VERSION 5.8 ;
BUSBITCHARS "[]" ;
DIVIDERCHAR "/" ;
UNITS
    DATABASE MICRONS 1000 ;
END UNITS

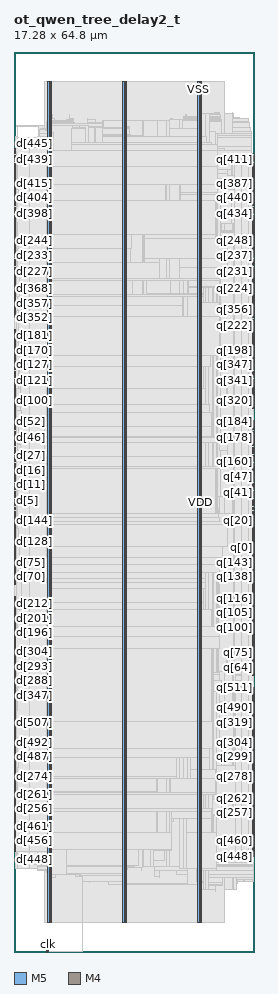
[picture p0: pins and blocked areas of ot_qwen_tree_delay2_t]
MACRO ot_qwen_tree_delay2_t
  FOREIGN ot_qwen_tree_delay2_t 0 0 ;
  CLASS BLOCK ;
  SIZE 17.28 BY 64.8 ;
  PIN clk
    DIRECTION INPUT ;
    USE SIGNAL ;
    PORT
      LAYER M5 ;
        RECT  2.352 0 2.376 0.084 ;
    END
    PORT
      LAYER M5 ;
        RECT  2.352 0.016 2.376 0.037 ;
    END
    PORT
      LAYER M5 ;
        RECT  2.352 0.037 2.472 0.179 ;
    END
  END clk
  PIN d[0]
    DIRECTION INPUT ;
    USE SIGNAL ;
    PORT
      LAYER M4 ;
        RECT  0 32.592 0.084 32.616 ;
    END
  END d[0]
  PIN d[100]
    DIRECTION INPUT ;
    USE SIGNAL ;
    PORT
      LAYER M4 ;
        RECT  0 39.12 0.084 39.144 ;
    END
  END d[100]
  PIN d[101]
    DIRECTION INPUT ;
    USE SIGNAL ;
    PORT
      LAYER M4 ;
        RECT  0 39.216 0.084 39.24 ;
    END
  END d[101]
  PIN d[102]
    DIRECTION INPUT ;
    USE SIGNAL ;
    PORT
      LAYER M4 ;
        RECT  0 39.312 0.084 39.336 ;
    END
  END d[102]
  PIN d[103]
    DIRECTION INPUT ;
    USE SIGNAL ;
    PORT
      LAYER M4 ;
        RECT  0 39.408 0.084 39.432 ;
    END
  END d[103]
  PIN d[104]
    DIRECTION INPUT ;
    USE SIGNAL ;
    PORT
      LAYER M4 ;
        RECT  0 39.504 0.084 39.528 ;
    END
  END d[104]
  PIN d[105]
    DIRECTION INPUT ;
    USE SIGNAL ;
    PORT
      LAYER M4 ;
        RECT  0 39.6 0.084 39.624 ;
    END
  END d[105]
  PIN d[106]
    DIRECTION INPUT ;
    USE SIGNAL ;
    PORT
      LAYER M4 ;
        RECT  0 39.696 0.084 39.72 ;
    END
  END d[106]
  PIN d[107]
    DIRECTION INPUT ;
    USE SIGNAL ;
    PORT
      LAYER M4 ;
        RECT  0 39.792 0.084 39.816 ;
    END
  END d[107]
  PIN d[108]
    DIRECTION INPUT ;
    USE SIGNAL ;
    PORT
      LAYER M4 ;
        RECT  0 39.888 0.084 39.912 ;
    END
  END d[108]
  PIN d[109]
    DIRECTION INPUT ;
    USE SIGNAL ;
    PORT
      LAYER M4 ;
        RECT  0 39.984 0.084 40.008 ;
    END
  END d[109]
  PIN d[10]
    DIRECTION INPUT ;
    USE SIGNAL ;
    PORT
      LAYER M4 ;
        RECT  0 33.552 0.084 33.576 ;
    END
  END d[10]
  PIN d[110]
    DIRECTION INPUT ;
    USE SIGNAL ;
    PORT
      LAYER M4 ;
        RECT  0 40.08 0.084 40.104 ;
    END
  END d[110]
  PIN d[111]
    DIRECTION INPUT ;
    USE SIGNAL ;
    PORT
      LAYER M4 ;
        RECT  0 40.176 0.084 40.2 ;
    END
  END d[111]
  PIN d[112]
    DIRECTION INPUT ;
    USE SIGNAL ;
    PORT
      LAYER M4 ;
        RECT  0 40.272 0.084 40.296 ;
    END
  END d[112]
  PIN d[113]
    DIRECTION INPUT ;
    USE SIGNAL ;
    PORT
      LAYER M4 ;
        RECT  0 40.368 0.084 40.392 ;
    END
  END d[113]
  PIN d[114]
    DIRECTION INPUT ;
    USE SIGNAL ;
    PORT
      LAYER M4 ;
        RECT  0 40.464 0.084 40.488 ;
    END
  END d[114]
  PIN d[115]
    DIRECTION INPUT ;
    USE SIGNAL ;
    PORT
      LAYER M4 ;
        RECT  0 40.56 0.084 40.584 ;
    END
  END d[115]
  PIN d[116]
    DIRECTION INPUT ;
    USE SIGNAL ;
    PORT
      LAYER M4 ;
        RECT  0 40.656 0.084 40.68 ;
    END
  END d[116]
  PIN d[117]
    DIRECTION INPUT ;
    USE SIGNAL ;
    PORT
      LAYER M4 ;
        RECT  0 40.752 0.084 40.776 ;
    END
  END d[117]
  PIN d[118]
    DIRECTION INPUT ;
    USE SIGNAL ;
    PORT
      LAYER M4 ;
        RECT  0 40.848 0.084 40.872 ;
    END
  END d[118]
  PIN d[119]
    DIRECTION INPUT ;
    USE SIGNAL ;
    PORT
      LAYER M4 ;
        RECT  0 40.944 0.084 40.968 ;
    END
  END d[119]
  PIN d[11]
    DIRECTION INPUT ;
    USE SIGNAL ;
    PORT
      LAYER M4 ;
        RECT  0 33.648 0.084 33.672 ;
    END
  END d[11]
  PIN d[120]
    DIRECTION INPUT ;
    USE SIGNAL ;
    PORT
      LAYER M4 ;
        RECT  0 41.04 0.084 41.064 ;
    END
  END d[120]
  PIN d[121]
    DIRECTION INPUT ;
    USE SIGNAL ;
    PORT
      LAYER M4 ;
        RECT  0 41.136 0.084 41.16 ;
    END
  END d[121]
  PIN d[122]
    DIRECTION INPUT ;
    USE SIGNAL ;
    PORT
      LAYER M4 ;
        RECT  0 41.232 0.084 41.256 ;
    END
  END d[122]
  PIN d[123]
    DIRECTION INPUT ;
    USE SIGNAL ;
    PORT
      LAYER M4 ;
        RECT  0 41.328 0.084 41.352 ;
    END
  END d[123]
  PIN d[124]
    DIRECTION INPUT ;
    USE SIGNAL ;
    PORT
      LAYER M4 ;
        RECT  0 41.424 0.084 41.448 ;
    END
  END d[124]
  PIN d[125]
    DIRECTION INPUT ;
    USE SIGNAL ;
    PORT
      LAYER M4 ;
        RECT  0 41.52 0.084 41.544 ;
    END
  END d[125]
  PIN d[126]
    DIRECTION INPUT ;
    USE SIGNAL ;
    PORT
      LAYER M4 ;
        RECT  0 41.616 0.084 41.64 ;
    END
  END d[126]
  PIN d[127]
    DIRECTION INPUT ;
    USE SIGNAL ;
    PORT
      LAYER M4 ;
        RECT  0 41.712 0.084 41.736 ;
    END
  END d[127]
  PIN d[128]
    DIRECTION INPUT ;
    USE SIGNAL ;
    PORT
      LAYER M4 ;
        RECT  0 29.52 0.084 29.544 ;
    END
  END d[128]
  PIN d[129]
    DIRECTION INPUT ;
    USE SIGNAL ;
    PORT
      LAYER M4 ;
        RECT  0 29.616 0.084 29.64 ;
    END
  END d[129]
  PIN d[12]
    DIRECTION INPUT ;
    USE SIGNAL ;
    PORT
      LAYER M4 ;
        RECT  0 33.744 0.084 33.768 ;
    END
  END d[12]
  PIN d[130]
    DIRECTION INPUT ;
    USE SIGNAL ;
    PORT
      LAYER M4 ;
        RECT  0 29.712 0.084 29.736 ;
    END
  END d[130]
  PIN d[131]
    DIRECTION INPUT ;
    USE SIGNAL ;
    PORT
      LAYER M4 ;
        RECT  0 29.808 0.084 29.832 ;
    END
  END d[131]
  PIN d[132]
    DIRECTION INPUT ;
    USE SIGNAL ;
    PORT
      LAYER M4 ;
        RECT  0 29.904 0.084 29.928 ;
    END
  END d[132]
  PIN d[133]
    DIRECTION INPUT ;
    USE SIGNAL ;
    PORT
      LAYER M4 ;
        RECT  0 30 0.084 30.024 ;
    END
  END d[133]
  PIN d[134]
    DIRECTION INPUT ;
    USE SIGNAL ;
    PORT
      LAYER M4 ;
        RECT  0 30.096 0.084 30.12 ;
    END
  END d[134]
  PIN d[135]
    DIRECTION INPUT ;
    USE SIGNAL ;
    PORT
      LAYER M4 ;
        RECT  0 30.192 0.084 30.216 ;
    END
  END d[135]
  PIN d[136]
    DIRECTION INPUT ;
    USE SIGNAL ;
    PORT
      LAYER M4 ;
        RECT  0 30.288 0.084 30.312 ;
    END
  END d[136]
  PIN d[137]
    DIRECTION INPUT ;
    USE SIGNAL ;
    PORT
      LAYER M4 ;
        RECT  0 30.384 0.084 30.408 ;
    END
  END d[137]
  PIN d[138]
    DIRECTION INPUT ;
    USE SIGNAL ;
    PORT
      LAYER M4 ;
        RECT  0 30.48 0.084 30.504 ;
    END
  END d[138]
  PIN d[139]
    DIRECTION INPUT ;
    USE SIGNAL ;
    PORT
      LAYER M4 ;
        RECT  0 30.576 0.084 30.6 ;
    END
  END d[139]
  PIN d[13]
    DIRECTION INPUT ;
    USE SIGNAL ;
    PORT
      LAYER M4 ;
        RECT  0 33.84 0.084 33.864 ;
    END
  END d[13]
  PIN d[140]
    DIRECTION INPUT ;
    USE SIGNAL ;
    PORT
      LAYER M4 ;
        RECT  0 30.672 0.084 30.696 ;
    END
  END d[140]
  PIN d[141]
    DIRECTION INPUT ;
    USE SIGNAL ;
    PORT
      LAYER M4 ;
        RECT  0 30.768 0.084 30.792 ;
    END
  END d[141]
  PIN d[142]
    DIRECTION INPUT ;
    USE SIGNAL ;
    PORT
      LAYER M4 ;
        RECT  0 30.864 0.084 30.888 ;
    END
  END d[142]
  PIN d[143]
    DIRECTION INPUT ;
    USE SIGNAL ;
    PORT
      LAYER M4 ;
        RECT  0 30.96 0.084 30.984 ;
    END
  END d[143]
  PIN d[144]
    DIRECTION INPUT ;
    USE SIGNAL ;
    PORT
      LAYER M4 ;
        RECT  0 31.056 0.084 31.08 ;
    END
  END d[144]
  PIN d[145]
    DIRECTION INPUT ;
    USE SIGNAL ;
    PORT
      LAYER M4 ;
        RECT  0 31.152 0.084 31.176 ;
    END
  END d[145]
  PIN d[146]
    DIRECTION INPUT ;
    USE SIGNAL ;
    PORT
      LAYER M4 ;
        RECT  0 31.248 0.084 31.272 ;
    END
  END d[146]
  PIN d[147]
    DIRECTION INPUT ;
    USE SIGNAL ;
    PORT
      LAYER M4 ;
        RECT  0 31.344 0.084 31.368 ;
    END
  END d[147]
  PIN d[148]
    DIRECTION INPUT ;
    USE SIGNAL ;
    PORT
      LAYER M4 ;
        RECT  0 31.44 0.084 31.464 ;
    END
  END d[148]
  PIN d[149]
    DIRECTION INPUT ;
    USE SIGNAL ;
    PORT
      LAYER M4 ;
        RECT  0 31.536 0.084 31.56 ;
    END
  END d[149]
  PIN d[14]
    DIRECTION INPUT ;
    USE SIGNAL ;
    PORT
      LAYER M4 ;
        RECT  0 33.936 0.084 33.96 ;
    END
  END d[14]
  PIN d[150]
    DIRECTION INPUT ;
    USE SIGNAL ;
    PORT
      LAYER M4 ;
        RECT  0 31.632 0.084 31.656 ;
    END
  END d[150]
  PIN d[151]
    DIRECTION INPUT ;
    USE SIGNAL ;
    PORT
      LAYER M4 ;
        RECT  0 31.728 0.084 31.752 ;
    END
  END d[151]
  PIN d[152]
    DIRECTION INPUT ;
    USE SIGNAL ;
    PORT
      LAYER M4 ;
        RECT  0 31.824 0.084 31.848 ;
    END
  END d[152]
  PIN d[153]
    DIRECTION INPUT ;
    USE SIGNAL ;
    PORT
      LAYER M4 ;
        RECT  0 31.92 0.084 31.944 ;
    END
  END d[153]
  PIN d[154]
    DIRECTION INPUT ;
    USE SIGNAL ;
    PORT
      LAYER M4 ;
        RECT  0 32.016 0.084 32.04 ;
    END
  END d[154]
  PIN d[155]
    DIRECTION INPUT ;
    USE SIGNAL ;
    PORT
      LAYER M4 ;
        RECT  0 32.112 0.084 32.136 ;
    END
  END d[155]
  PIN d[156]
    DIRECTION INPUT ;
    USE SIGNAL ;
    PORT
      LAYER M4 ;
        RECT  0 32.208 0.084 32.232 ;
    END
  END d[156]
  PIN d[157]
    DIRECTION INPUT ;
    USE SIGNAL ;
    PORT
      LAYER M4 ;
        RECT  0 32.304 0.084 32.328 ;
    END
  END d[157]
  PIN d[158]
    DIRECTION INPUT ;
    USE SIGNAL ;
    PORT
      LAYER M4 ;
        RECT  0 32.4 0.084 32.424 ;
    END
  END d[158]
  PIN d[159]
    DIRECTION INPUT ;
    USE SIGNAL ;
    PORT
      LAYER M4 ;
        RECT  0 32.496 0.084 32.52 ;
    END
  END d[159]
  PIN d[15]
    DIRECTION INPUT ;
    USE SIGNAL ;
    PORT
      LAYER M4 ;
        RECT  0 34.032 0.084 34.056 ;
    END
  END d[15]
  PIN d[160]
    DIRECTION INPUT ;
    USE SIGNAL ;
    PORT
      LAYER M4 ;
        RECT  0 41.808 0.084 41.832 ;
    END
  END d[160]
  PIN d[161]
    DIRECTION INPUT ;
    USE SIGNAL ;
    PORT
      LAYER M4 ;
        RECT  0 41.904 0.084 41.928 ;
    END
  END d[161]
  PIN d[162]
    DIRECTION INPUT ;
    USE SIGNAL ;
    PORT
      LAYER M4 ;
        RECT  0 42 0.084 42.024 ;
    END
  END d[162]
  PIN d[163]
    DIRECTION INPUT ;
    USE SIGNAL ;
    PORT
      LAYER M4 ;
        RECT  0 42.096 0.084 42.12 ;
    END
  END d[163]
  PIN d[164]
    DIRECTION INPUT ;
    USE SIGNAL ;
    PORT
      LAYER M4 ;
        RECT  0 42.192 0.084 42.216 ;
    END
  END d[164]
  PIN d[165]
    DIRECTION INPUT ;
    USE SIGNAL ;
    PORT
      LAYER M4 ;
        RECT  0 42.288 0.084 42.312 ;
    END
  END d[165]
  PIN d[166]
    DIRECTION INPUT ;
    USE SIGNAL ;
    PORT
      LAYER M4 ;
        RECT  0 42.384 0.084 42.408 ;
    END
  END d[166]
  PIN d[167]
    DIRECTION INPUT ;
    USE SIGNAL ;
    PORT
      LAYER M4 ;
        RECT  0 42.48 0.084 42.504 ;
    END
  END d[167]
  PIN d[168]
    DIRECTION INPUT ;
    USE SIGNAL ;
    PORT
      LAYER M4 ;
        RECT  0 42.576 0.084 42.6 ;
    END
  END d[168]
  PIN d[169]
    DIRECTION INPUT ;
    USE SIGNAL ;
    PORT
      LAYER M4 ;
        RECT  0 42.672 0.084 42.696 ;
    END
  END d[169]
  PIN d[16]
    DIRECTION INPUT ;
    USE SIGNAL ;
    PORT
      LAYER M4 ;
        RECT  0 34.128 0.084 34.152 ;
    END
  END d[16]
  PIN d[170]
    DIRECTION INPUT ;
    USE SIGNAL ;
    PORT
      LAYER M4 ;
        RECT  0 42.768 0.084 42.792 ;
    END
  END d[170]
  PIN d[171]
    DIRECTION INPUT ;
    USE SIGNAL ;
    PORT
      LAYER M4 ;
        RECT  0 42.864 0.084 42.888 ;
    END
  END d[171]
  PIN d[172]
    DIRECTION INPUT ;
    USE SIGNAL ;
    PORT
      LAYER M4 ;
        RECT  0 42.96 0.084 42.984 ;
    END
  END d[172]
  PIN d[173]
    DIRECTION INPUT ;
    USE SIGNAL ;
    PORT
      LAYER M4 ;
        RECT  0 43.056 0.084 43.08 ;
    END
  END d[173]
  PIN d[174]
    DIRECTION INPUT ;
    USE SIGNAL ;
    PORT
      LAYER M4 ;
        RECT  0 43.152 0.084 43.176 ;
    END
  END d[174]
  PIN d[175]
    DIRECTION INPUT ;
    USE SIGNAL ;
    PORT
      LAYER M4 ;
        RECT  0 43.248 0.084 43.272 ;
    END
  END d[175]
  PIN d[176]
    DIRECTION INPUT ;
    USE SIGNAL ;
    PORT
      LAYER M4 ;
        RECT  0 43.344 0.084 43.368 ;
    END
  END d[176]
  PIN d[177]
    DIRECTION INPUT ;
    USE SIGNAL ;
    PORT
      LAYER M4 ;
        RECT  0 43.44 0.084 43.464 ;
    END
  END d[177]
  PIN d[178]
    DIRECTION INPUT ;
    USE SIGNAL ;
    PORT
      LAYER M4 ;
        RECT  0 43.536 0.084 43.56 ;
    END
  END d[178]
  PIN d[179]
    DIRECTION INPUT ;
    USE SIGNAL ;
    PORT
      LAYER M4 ;
        RECT  0 43.632 0.084 43.656 ;
    END
  END d[179]
  PIN d[17]
    DIRECTION INPUT ;
    USE SIGNAL ;
    PORT
      LAYER M4 ;
        RECT  0 34.224 0.084 34.248 ;
    END
  END d[17]
  PIN d[180]
    DIRECTION INPUT ;
    USE SIGNAL ;
    PORT
      LAYER M4 ;
        RECT  0 43.728 0.084 43.752 ;
    END
  END d[180]
  PIN d[181]
    DIRECTION INPUT ;
    USE SIGNAL ;
    PORT
      LAYER M4 ;
        RECT  0 43.824 0.084 43.848 ;
    END
  END d[181]
  PIN d[182]
    DIRECTION INPUT ;
    USE SIGNAL ;
    PORT
      LAYER M4 ;
        RECT  0 43.92 0.084 43.944 ;
    END
  END d[182]
  PIN d[183]
    DIRECTION INPUT ;
    USE SIGNAL ;
    PORT
      LAYER M4 ;
        RECT  0 44.016 0.084 44.04 ;
    END
  END d[183]
  PIN d[184]
    DIRECTION INPUT ;
    USE SIGNAL ;
    PORT
      LAYER M4 ;
        RECT  0 44.112 0.084 44.136 ;
    END
  END d[184]
  PIN d[185]
    DIRECTION INPUT ;
    USE SIGNAL ;
    PORT
      LAYER M4 ;
        RECT  0 44.208 0.084 44.232 ;
    END
  END d[185]
  PIN d[186]
    DIRECTION INPUT ;
    USE SIGNAL ;
    PORT
      LAYER M4 ;
        RECT  0 44.304 0.084 44.328 ;
    END
  END d[186]
  PIN d[187]
    DIRECTION INPUT ;
    USE SIGNAL ;
    PORT
      LAYER M4 ;
        RECT  0 44.4 0.084 44.424 ;
    END
  END d[187]
  PIN d[188]
    DIRECTION INPUT ;
    USE SIGNAL ;
    PORT
      LAYER M4 ;
        RECT  0 44.496 0.084 44.52 ;
    END
  END d[188]
  PIN d[189]
    DIRECTION INPUT ;
    USE SIGNAL ;
    PORT
      LAYER M4 ;
        RECT  0 44.592 0.084 44.616 ;
    END
  END d[189]
  PIN d[18]
    DIRECTION INPUT ;
    USE SIGNAL ;
    PORT
      LAYER M4 ;
        RECT  0 34.32 0.084 34.344 ;
    END
  END d[18]
  PIN d[190]
    DIRECTION INPUT ;
    USE SIGNAL ;
    PORT
      LAYER M4 ;
        RECT  0 44.688 0.084 44.712 ;
    END
  END d[190]
  PIN d[191]
    DIRECTION INPUT ;
    USE SIGNAL ;
    PORT
      LAYER M4 ;
        RECT  0 44.784 0.084 44.808 ;
    END
  END d[191]
  PIN d[192]
    DIRECTION INPUT ;
    USE SIGNAL ;
    PORT
      LAYER M4 ;
        RECT  0 22.608 0.084 22.632 ;
    END
  END d[192]
  PIN d[193]
    DIRECTION INPUT ;
    USE SIGNAL ;
    PORT
      LAYER M4 ;
        RECT  0 22.704 0.084 22.728 ;
    END
  END d[193]
  PIN d[194]
    DIRECTION INPUT ;
    USE SIGNAL ;
    PORT
      LAYER M4 ;
        RECT  0 22.8 0.084 22.824 ;
    END
  END d[194]
  PIN d[195]
    DIRECTION INPUT ;
    USE SIGNAL ;
    PORT
      LAYER M4 ;
        RECT  0 22.896 0.084 22.92 ;
    END
  END d[195]
  PIN d[196]
    DIRECTION INPUT ;
    USE SIGNAL ;
    PORT
      LAYER M4 ;
        RECT  0 22.992 0.084 23.016 ;
    END
  END d[196]
  PIN d[197]
    DIRECTION INPUT ;
    USE SIGNAL ;
    PORT
      LAYER M4 ;
        RECT  0 23.088 0.084 23.112 ;
    END
  END d[197]
  PIN d[198]
    DIRECTION INPUT ;
    USE SIGNAL ;
    PORT
      LAYER M4 ;
        RECT  0 23.184 0.084 23.208 ;
    END
  END d[198]
  PIN d[199]
    DIRECTION INPUT ;
    USE SIGNAL ;
    PORT
      LAYER M4 ;
        RECT  0 23.28 0.084 23.304 ;
    END
  END d[199]
  PIN d[19]
    DIRECTION INPUT ;
    USE SIGNAL ;
    PORT
      LAYER M4 ;
        RECT  0 34.416 0.084 34.44 ;
    END
  END d[19]
  PIN d[1]
    DIRECTION INPUT ;
    USE SIGNAL ;
    PORT
      LAYER M4 ;
        RECT  0 32.688 0.084 32.712 ;
    END
  END d[1]
  PIN d[200]
    DIRECTION INPUT ;
    USE SIGNAL ;
    PORT
      LAYER M4 ;
        RECT  0 23.376 0.084 23.4 ;
    END
  END d[200]
  PIN d[201]
    DIRECTION INPUT ;
    USE SIGNAL ;
    PORT
      LAYER M4 ;
        RECT  0 23.472 0.084 23.496 ;
    END
  END d[201]
  PIN d[202]
    DIRECTION INPUT ;
    USE SIGNAL ;
    PORT
      LAYER M4 ;
        RECT  0 23.568 0.084 23.592 ;
    END
  END d[202]
  PIN d[203]
    DIRECTION INPUT ;
    USE SIGNAL ;
    PORT
      LAYER M4 ;
        RECT  0 23.664 0.084 23.688 ;
    END
  END d[203]
  PIN d[204]
    DIRECTION INPUT ;
    USE SIGNAL ;
    PORT
      LAYER M4 ;
        RECT  0 23.76 0.084 23.784 ;
    END
  END d[204]
  PIN d[205]
    DIRECTION INPUT ;
    USE SIGNAL ;
    PORT
      LAYER M4 ;
        RECT  0 23.856 0.084 23.88 ;
    END
  END d[205]
  PIN d[206]
    DIRECTION INPUT ;
    USE SIGNAL ;
    PORT
      LAYER M4 ;
        RECT  0 23.952 0.084 23.976 ;
    END
  END d[206]
  PIN d[207]
    DIRECTION INPUT ;
    USE SIGNAL ;
    PORT
      LAYER M4 ;
        RECT  0 24.048 0.084 24.072 ;
    END
  END d[207]
  PIN d[208]
    DIRECTION INPUT ;
    USE SIGNAL ;
    PORT
      LAYER M4 ;
        RECT  0 24.144 0.084 24.168 ;
    END
  END d[208]
  PIN d[209]
    DIRECTION INPUT ;
    USE SIGNAL ;
    PORT
      LAYER M4 ;
        RECT  0 24.24 0.084 24.264 ;
    END
  END d[209]
  PIN d[20]
    DIRECTION INPUT ;
    USE SIGNAL ;
    PORT
      LAYER M4 ;
        RECT  0 34.512 0.084 34.536 ;
    END
  END d[20]
  PIN d[210]
    DIRECTION INPUT ;
    USE SIGNAL ;
    PORT
      LAYER M4 ;
        RECT  0 24.336 0.084 24.36 ;
    END
  END d[210]
  PIN d[211]
    DIRECTION INPUT ;
    USE SIGNAL ;
    PORT
      LAYER M4 ;
        RECT  0 24.432 0.084 24.456 ;
    END
  END d[211]
  PIN d[212]
    DIRECTION INPUT ;
    USE SIGNAL ;
    PORT
      LAYER M4 ;
        RECT  0 24.528 0.084 24.552 ;
    END
  END d[212]
  PIN d[213]
    DIRECTION INPUT ;
    USE SIGNAL ;
    PORT
      LAYER M4 ;
        RECT  0 24.624 0.084 24.648 ;
    END
  END d[213]
  PIN d[214]
    DIRECTION INPUT ;
    USE SIGNAL ;
    PORT
      LAYER M4 ;
        RECT  0 24.72 0.084 24.744 ;
    END
  END d[214]
  PIN d[215]
    DIRECTION INPUT ;
    USE SIGNAL ;
    PORT
      LAYER M4 ;
        RECT  0 24.816 0.084 24.84 ;
    END
  END d[215]
  PIN d[216]
    DIRECTION INPUT ;
    USE SIGNAL ;
    PORT
      LAYER M4 ;
        RECT  0 24.912 0.084 24.936 ;
    END
  END d[216]
  PIN d[217]
    DIRECTION INPUT ;
    USE SIGNAL ;
    PORT
      LAYER M4 ;
        RECT  0 25.008 0.084 25.032 ;
    END
  END d[217]
  PIN d[218]
    DIRECTION INPUT ;
    USE SIGNAL ;
    PORT
      LAYER M4 ;
        RECT  0 25.104 0.084 25.128 ;
    END
  END d[218]
  PIN d[219]
    DIRECTION INPUT ;
    USE SIGNAL ;
    PORT
      LAYER M4 ;
        RECT  0 25.2 0.084 25.224 ;
    END
  END d[219]
  PIN d[21]
    DIRECTION INPUT ;
    USE SIGNAL ;
    PORT
      LAYER M4 ;
        RECT  0 34.608 0.084 34.632 ;
    END
  END d[21]
  PIN d[220]
    DIRECTION INPUT ;
    USE SIGNAL ;
    PORT
      LAYER M4 ;
        RECT  0 25.296 0.084 25.32 ;
    END
  END d[220]
  PIN d[221]
    DIRECTION INPUT ;
    USE SIGNAL ;
    PORT
      LAYER M4 ;
        RECT  0 25.392 0.084 25.416 ;
    END
  END d[221]
  PIN d[222]
    DIRECTION INPUT ;
    USE SIGNAL ;
    PORT
      LAYER M4 ;
        RECT  0 25.488 0.084 25.512 ;
    END
  END d[222]
  PIN d[223]
    DIRECTION INPUT ;
    USE SIGNAL ;
    PORT
      LAYER M4 ;
        RECT  0 25.584 0.084 25.608 ;
    END
  END d[223]
  PIN d[224]
    DIRECTION INPUT ;
    USE SIGNAL ;
    PORT
      LAYER M4 ;
        RECT  0 48.72 0.084 48.744 ;
    END
  END d[224]
  PIN d[225]
    DIRECTION INPUT ;
    USE SIGNAL ;
    PORT
      LAYER M4 ;
        RECT  0 48.816 0.084 48.84 ;
    END
  END d[225]
  PIN d[226]
    DIRECTION INPUT ;
    USE SIGNAL ;
    PORT
      LAYER M4 ;
        RECT  0 48.912 0.084 48.936 ;
    END
  END d[226]
  PIN d[227]
    DIRECTION INPUT ;
    USE SIGNAL ;
    PORT
      LAYER M4 ;
        RECT  0 49.008 0.084 49.032 ;
    END
  END d[227]
  PIN d[228]
    DIRECTION INPUT ;
    USE SIGNAL ;
    PORT
      LAYER M4 ;
        RECT  0 49.104 0.084 49.128 ;
    END
  END d[228]
  PIN d[229]
    DIRECTION INPUT ;
    USE SIGNAL ;
    PORT
      LAYER M4 ;
        RECT  0 49.2 0.084 49.224 ;
    END
  END d[229]
  PIN d[22]
    DIRECTION INPUT ;
    USE SIGNAL ;
    PORT
      LAYER M4 ;
        RECT  0 34.704 0.084 34.728 ;
    END
  END d[22]
  PIN d[230]
    DIRECTION INPUT ;
    USE SIGNAL ;
    PORT
      LAYER M4 ;
        RECT  0 49.296 0.084 49.32 ;
    END
  END d[230]
  PIN d[231]
    DIRECTION INPUT ;
    USE SIGNAL ;
    PORT
      LAYER M4 ;
        RECT  0 49.392 0.084 49.416 ;
    END
  END d[231]
  PIN d[232]
    DIRECTION INPUT ;
    USE SIGNAL ;
    PORT
      LAYER M4 ;
        RECT  0 49.488 0.084 49.512 ;
    END
  END d[232]
  PIN d[233]
    DIRECTION INPUT ;
    USE SIGNAL ;
    PORT
      LAYER M4 ;
        RECT  0 49.584 0.084 49.608 ;
    END
  END d[233]
  PIN d[234]
    DIRECTION INPUT ;
    USE SIGNAL ;
    PORT
      LAYER M4 ;
        RECT  0 49.68 0.084 49.704 ;
    END
  END d[234]
  PIN d[235]
    DIRECTION INPUT ;
    USE SIGNAL ;
    PORT
      LAYER M4 ;
        RECT  0 49.776 0.084 49.8 ;
    END
  END d[235]
  PIN d[236]
    DIRECTION INPUT ;
    USE SIGNAL ;
    PORT
      LAYER M4 ;
        RECT  0 49.872 0.084 49.896 ;
    END
  END d[236]
  PIN d[237]
    DIRECTION INPUT ;
    USE SIGNAL ;
    PORT
      LAYER M4 ;
        RECT  0 49.968 0.084 49.992 ;
    END
  END d[237]
  PIN d[238]
    DIRECTION INPUT ;
    USE SIGNAL ;
    PORT
      LAYER M4 ;
        RECT  0 50.064 0.084 50.088 ;
    END
  END d[238]
  PIN d[239]
    DIRECTION INPUT ;
    USE SIGNAL ;
    PORT
      LAYER M4 ;
        RECT  0 50.16 0.084 50.184 ;
    END
  END d[239]
  PIN d[23]
    DIRECTION INPUT ;
    USE SIGNAL ;
    PORT
      LAYER M4 ;
        RECT  0 34.8 0.084 34.824 ;
    END
  END d[23]
  PIN d[240]
    DIRECTION INPUT ;
    USE SIGNAL ;
    PORT
      LAYER M4 ;
        RECT  0 50.256 0.084 50.28 ;
    END
  END d[240]
  PIN d[241]
    DIRECTION INPUT ;
    USE SIGNAL ;
    PORT
      LAYER M4 ;
        RECT  0 50.352 0.084 50.376 ;
    END
  END d[241]
  PIN d[242]
    DIRECTION INPUT ;
    USE SIGNAL ;
    PORT
      LAYER M4 ;
        RECT  0 50.448 0.084 50.472 ;
    END
  END d[242]
  PIN d[243]
    DIRECTION INPUT ;
    USE SIGNAL ;
    PORT
      LAYER M4 ;
        RECT  0 50.544 0.084 50.568 ;
    END
  END d[243]
  PIN d[244]
    DIRECTION INPUT ;
    USE SIGNAL ;
    PORT
      LAYER M4 ;
        RECT  0 50.64 0.084 50.664 ;
    END
  END d[244]
  PIN d[245]
    DIRECTION INPUT ;
    USE SIGNAL ;
    PORT
      LAYER M4 ;
        RECT  0 50.736 0.084 50.76 ;
    END
  END d[245]
  PIN d[246]
    DIRECTION INPUT ;
    USE SIGNAL ;
    PORT
      LAYER M4 ;
        RECT  0 50.832 0.084 50.856 ;
    END
  END d[246]
  PIN d[247]
    DIRECTION INPUT ;
    USE SIGNAL ;
    PORT
      LAYER M4 ;
        RECT  0 50.928 0.084 50.952 ;
    END
  END d[247]
  PIN d[248]
    DIRECTION INPUT ;
    USE SIGNAL ;
    PORT
      LAYER M4 ;
        RECT  0 51.024 0.084 51.048 ;
    END
  END d[248]
  PIN d[249]
    DIRECTION INPUT ;
    USE SIGNAL ;
    PORT
      LAYER M4 ;
        RECT  0 51.12 0.084 51.144 ;
    END
  END d[249]
  PIN d[24]
    DIRECTION INPUT ;
    USE SIGNAL ;
    PORT
      LAYER M4 ;
        RECT  0 34.896 0.084 34.92 ;
    END
  END d[24]
  PIN d[250]
    DIRECTION INPUT ;
    USE SIGNAL ;
    PORT
      LAYER M4 ;
        RECT  0 51.216 0.084 51.24 ;
    END
  END d[250]
  PIN d[251]
    DIRECTION INPUT ;
    USE SIGNAL ;
    PORT
      LAYER M4 ;
        RECT  0 51.312 0.084 51.336 ;
    END
  END d[251]
  PIN d[252]
    DIRECTION INPUT ;
    USE SIGNAL ;
    PORT
      LAYER M4 ;
        RECT  0 51.408 0.084 51.432 ;
    END
  END d[252]
  PIN d[253]
    DIRECTION INPUT ;
    USE SIGNAL ;
    PORT
      LAYER M4 ;
        RECT  0 51.504 0.084 51.528 ;
    END
  END d[253]
  PIN d[254]
    DIRECTION INPUT ;
    USE SIGNAL ;
    PORT
      LAYER M4 ;
        RECT  0 51.6 0.084 51.624 ;
    END
  END d[254]
  PIN d[255]
    DIRECTION INPUT ;
    USE SIGNAL ;
    PORT
      LAYER M4 ;
        RECT  0 51.696 0.084 51.72 ;
    END
  END d[255]
  PIN d[256]
    DIRECTION INPUT ;
    USE SIGNAL ;
    PORT
      LAYER M4 ;
        RECT  0 10.32 0.084 10.344 ;
    END
  END d[256]
  PIN d[257]
    DIRECTION INPUT ;
    USE SIGNAL ;
    PORT
      LAYER M4 ;
        RECT  0 10.416 0.084 10.44 ;
    END
  END d[257]
  PIN d[258]
    DIRECTION INPUT ;
    USE SIGNAL ;
    PORT
      LAYER M4 ;
        RECT  0 10.512 0.084 10.536 ;
    END
  END d[258]
  PIN d[259]
    DIRECTION INPUT ;
    USE SIGNAL ;
    PORT
      LAYER M4 ;
        RECT  0 10.608 0.084 10.632 ;
    END
  END d[259]
  PIN d[25]
    DIRECTION INPUT ;
    USE SIGNAL ;
    PORT
      LAYER M4 ;
        RECT  0 34.992 0.084 35.016 ;
    END
  END d[25]
  PIN d[260]
    DIRECTION INPUT ;
    USE SIGNAL ;
    PORT
      LAYER M4 ;
        RECT  0 10.704 0.084 10.728 ;
    END
  END d[260]
  PIN d[261]
    DIRECTION INPUT ;
    USE SIGNAL ;
    PORT
      LAYER M4 ;
        RECT  0 10.8 0.084 10.824 ;
    END
  END d[261]
  PIN d[262]
    DIRECTION INPUT ;
    USE SIGNAL ;
    PORT
      LAYER M4 ;
        RECT  0 10.896 0.084 10.92 ;
    END
  END d[262]
  PIN d[263]
    DIRECTION INPUT ;
    USE SIGNAL ;
    PORT
      LAYER M4 ;
        RECT  0 10.992 0.084 11.016 ;
    END
  END d[263]
  PIN d[264]
    DIRECTION INPUT ;
    USE SIGNAL ;
    PORT
      LAYER M4 ;
        RECT  0 11.088 0.084 11.112 ;
    END
  END d[264]
  PIN d[265]
    DIRECTION INPUT ;
    USE SIGNAL ;
    PORT
      LAYER M4 ;
        RECT  0 11.184 0.084 11.208 ;
    END
  END d[265]
  PIN d[266]
    DIRECTION INPUT ;
    USE SIGNAL ;
    PORT
      LAYER M4 ;
        RECT  0 11.28 0.084 11.304 ;
    END
  END d[266]
  PIN d[267]
    DIRECTION INPUT ;
    USE SIGNAL ;
    PORT
      LAYER M4 ;
        RECT  0 11.376 0.084 11.4 ;
    END
  END d[267]
  PIN d[268]
    DIRECTION INPUT ;
    USE SIGNAL ;
    PORT
      LAYER M4 ;
        RECT  0 11.472 0.084 11.496 ;
    END
  END d[268]
  PIN d[269]
    DIRECTION INPUT ;
    USE SIGNAL ;
    PORT
      LAYER M4 ;
        RECT  0 11.568 0.084 11.592 ;
    END
  END d[269]
  PIN d[26]
    DIRECTION INPUT ;
    USE SIGNAL ;
    PORT
      LAYER M4 ;
        RECT  0 35.088 0.084 35.112 ;
    END
  END d[26]
  PIN d[270]
    DIRECTION INPUT ;
    USE SIGNAL ;
    PORT
      LAYER M4 ;
        RECT  0 11.664 0.084 11.688 ;
    END
  END d[270]
  PIN d[271]
    DIRECTION INPUT ;
    USE SIGNAL ;
    PORT
      LAYER M4 ;
        RECT  0 11.76 0.084 11.784 ;
    END
  END d[271]
  PIN d[272]
    DIRECTION INPUT ;
    USE SIGNAL ;
    PORT
      LAYER M4 ;
        RECT  0 11.856 0.084 11.88 ;
    END
  END d[272]
  PIN d[273]
    DIRECTION INPUT ;
    USE SIGNAL ;
    PORT
      LAYER M4 ;
        RECT  0 11.952 0.084 11.976 ;
    END
  END d[273]
  PIN d[274]
    DIRECTION INPUT ;
    USE SIGNAL ;
    PORT
      LAYER M4 ;
        RECT  0 12.048 0.084 12.072 ;
    END
  END d[274]
  PIN d[275]
    DIRECTION INPUT ;
    USE SIGNAL ;
    PORT
      LAYER M4 ;
        RECT  0 12.144 0.084 12.168 ;
    END
  END d[275]
  PIN d[276]
    DIRECTION INPUT ;
    USE SIGNAL ;
    PORT
      LAYER M4 ;
        RECT  0 12.24 0.084 12.264 ;
    END
  END d[276]
  PIN d[277]
    DIRECTION INPUT ;
    USE SIGNAL ;
    PORT
      LAYER M4 ;
        RECT  0 12.336 0.084 12.36 ;
    END
  END d[277]
  PIN d[278]
    DIRECTION INPUT ;
    USE SIGNAL ;
    PORT
      LAYER M4 ;
        RECT  0 12.432 0.084 12.456 ;
    END
  END d[278]
  PIN d[279]
    DIRECTION INPUT ;
    USE SIGNAL ;
    PORT
      LAYER M4 ;
        RECT  0 12.528 0.084 12.552 ;
    END
  END d[279]
  PIN d[27]
    DIRECTION INPUT ;
    USE SIGNAL ;
    PORT
      LAYER M4 ;
        RECT  0 35.184 0.084 35.208 ;
    END
  END d[27]
  PIN d[280]
    DIRECTION INPUT ;
    USE SIGNAL ;
    PORT
      LAYER M4 ;
        RECT  0 12.624 0.084 12.648 ;
    END
  END d[280]
  PIN d[281]
    DIRECTION INPUT ;
    USE SIGNAL ;
    PORT
      LAYER M4 ;
        RECT  0 12.72 0.084 12.744 ;
    END
  END d[281]
  PIN d[282]
    DIRECTION INPUT ;
    USE SIGNAL ;
    PORT
      LAYER M4 ;
        RECT  0 12.816 0.084 12.84 ;
    END
  END d[282]
  PIN d[283]
    DIRECTION INPUT ;
    USE SIGNAL ;
    PORT
      LAYER M4 ;
        RECT  0 12.912 0.084 12.936 ;
    END
  END d[283]
  PIN d[284]
    DIRECTION INPUT ;
    USE SIGNAL ;
    PORT
      LAYER M4 ;
        RECT  0 13.008 0.084 13.032 ;
    END
  END d[284]
  PIN d[285]
    DIRECTION INPUT ;
    USE SIGNAL ;
    PORT
      LAYER M4 ;
        RECT  0 13.104 0.084 13.128 ;
    END
  END d[285]
  PIN d[286]
    DIRECTION INPUT ;
    USE SIGNAL ;
    PORT
      LAYER M4 ;
        RECT  0 13.2 0.084 13.224 ;
    END
  END d[286]
  PIN d[287]
    DIRECTION INPUT ;
    USE SIGNAL ;
    PORT
      LAYER M4 ;
        RECT  0 13.296 0.084 13.32 ;
    END
  END d[287]
  PIN d[288]
    DIRECTION INPUT ;
    USE SIGNAL ;
    PORT
      LAYER M4 ;
        RECT  0 19.536 0.084 19.56 ;
    END
  END d[288]
  PIN d[289]
    DIRECTION INPUT ;
    USE SIGNAL ;
    PORT
      LAYER M4 ;
        RECT  0 19.632 0.084 19.656 ;
    END
  END d[289]
  PIN d[28]
    DIRECTION INPUT ;
    USE SIGNAL ;
    PORT
      LAYER M4 ;
        RECT  0 35.28 0.084 35.304 ;
    END
  END d[28]
  PIN d[290]
    DIRECTION INPUT ;
    USE SIGNAL ;
    PORT
      LAYER M4 ;
        RECT  0 19.728 0.084 19.752 ;
    END
  END d[290]
  PIN d[291]
    DIRECTION INPUT ;
    USE SIGNAL ;
    PORT
      LAYER M4 ;
        RECT  0 19.824 0.084 19.848 ;
    END
  END d[291]
  PIN d[292]
    DIRECTION INPUT ;
    USE SIGNAL ;
    PORT
      LAYER M4 ;
        RECT  0 19.92 0.084 19.944 ;
    END
  END d[292]
  PIN d[293]
    DIRECTION INPUT ;
    USE SIGNAL ;
    PORT
      LAYER M4 ;
        RECT  0 20.016 0.084 20.04 ;
    END
  END d[293]
  PIN d[294]
    DIRECTION INPUT ;
    USE SIGNAL ;
    PORT
      LAYER M4 ;
        RECT  0 20.112 0.084 20.136 ;
    END
  END d[294]
  PIN d[295]
    DIRECTION INPUT ;
    USE SIGNAL ;
    PORT
      LAYER M4 ;
        RECT  0 20.208 0.084 20.232 ;
    END
  END d[295]
  PIN d[296]
    DIRECTION INPUT ;
    USE SIGNAL ;
    PORT
      LAYER M4 ;
        RECT  0 20.304 0.084 20.328 ;
    END
  END d[296]
  PIN d[297]
    DIRECTION INPUT ;
    USE SIGNAL ;
    PORT
      LAYER M4 ;
        RECT  0 20.4 0.084 20.424 ;
    END
  END d[297]
  PIN d[298]
    DIRECTION INPUT ;
    USE SIGNAL ;
    PORT
      LAYER M4 ;
        RECT  0 20.496 0.084 20.52 ;
    END
  END d[298]
  PIN d[299]
    DIRECTION INPUT ;
    USE SIGNAL ;
    PORT
      LAYER M4 ;
        RECT  0 20.592 0.084 20.616 ;
    END
  END d[299]
  PIN d[29]
    DIRECTION INPUT ;
    USE SIGNAL ;
    PORT
      LAYER M4 ;
        RECT  0 35.376 0.084 35.4 ;
    END
  END d[29]
  PIN d[2]
    DIRECTION INPUT ;
    USE SIGNAL ;
    PORT
      LAYER M4 ;
        RECT  0 32.784 0.084 32.808 ;
    END
  END d[2]
  PIN d[300]
    DIRECTION INPUT ;
    USE SIGNAL ;
    PORT
      LAYER M4 ;
        RECT  0 20.688 0.084 20.712 ;
    END
  END d[300]
  PIN d[301]
    DIRECTION INPUT ;
    USE SIGNAL ;
    PORT
      LAYER M4 ;
        RECT  0 20.784 0.084 20.808 ;
    END
  END d[301]
  PIN d[302]
    DIRECTION INPUT ;
    USE SIGNAL ;
    PORT
      LAYER M4 ;
        RECT  0 20.88 0.084 20.904 ;
    END
  END d[302]
  PIN d[303]
    DIRECTION INPUT ;
    USE SIGNAL ;
    PORT
      LAYER M4 ;
        RECT  0 20.976 0.084 21 ;
    END
  END d[303]
  PIN d[304]
    DIRECTION INPUT ;
    USE SIGNAL ;
    PORT
      LAYER M4 ;
        RECT  0 21.072 0.084 21.096 ;
    END
  END d[304]
  PIN d[305]
    DIRECTION INPUT ;
    USE SIGNAL ;
    PORT
      LAYER M4 ;
        RECT  0 21.168 0.084 21.192 ;
    END
  END d[305]
  PIN d[306]
    DIRECTION INPUT ;
    USE SIGNAL ;
    PORT
      LAYER M4 ;
        RECT  0 21.264 0.084 21.288 ;
    END
  END d[306]
  PIN d[307]
    DIRECTION INPUT ;
    USE SIGNAL ;
    PORT
      LAYER M4 ;
        RECT  0 21.36 0.084 21.384 ;
    END
  END d[307]
  PIN d[308]
    DIRECTION INPUT ;
    USE SIGNAL ;
    PORT
      LAYER M4 ;
        RECT  0 21.456 0.084 21.48 ;
    END
  END d[308]
  PIN d[309]
    DIRECTION INPUT ;
    USE SIGNAL ;
    PORT
      LAYER M4 ;
        RECT  0 21.552 0.084 21.576 ;
    END
  END d[309]
  PIN d[30]
    DIRECTION INPUT ;
    USE SIGNAL ;
    PORT
      LAYER M4 ;
        RECT  0 35.472 0.084 35.496 ;
    END
  END d[30]
  PIN d[310]
    DIRECTION INPUT ;
    USE SIGNAL ;
    PORT
      LAYER M4 ;
        RECT  0 21.648 0.084 21.672 ;
    END
  END d[310]
  PIN d[311]
    DIRECTION INPUT ;
    USE SIGNAL ;
    PORT
      LAYER M4 ;
        RECT  0 21.744 0.084 21.768 ;
    END
  END d[311]
  PIN d[312]
    DIRECTION INPUT ;
    USE SIGNAL ;
    PORT
      LAYER M4 ;
        RECT  0 21.84 0.084 21.864 ;
    END
  END d[312]
  PIN d[313]
    DIRECTION INPUT ;
    USE SIGNAL ;
    PORT
      LAYER M4 ;
        RECT  0 21.936 0.084 21.96 ;
    END
  END d[313]
  PIN d[314]
    DIRECTION INPUT ;
    USE SIGNAL ;
    PORT
      LAYER M4 ;
        RECT  0 22.032 0.084 22.056 ;
    END
  END d[314]
  PIN d[315]
    DIRECTION INPUT ;
    USE SIGNAL ;
    PORT
      LAYER M4 ;
        RECT  0 22.128 0.084 22.152 ;
    END
  END d[315]
  PIN d[316]
    DIRECTION INPUT ;
    USE SIGNAL ;
    PORT
      LAYER M4 ;
        RECT  0 22.224 0.084 22.248 ;
    END
  END d[316]
  PIN d[317]
    DIRECTION INPUT ;
    USE SIGNAL ;
    PORT
      LAYER M4 ;
        RECT  0 22.32 0.084 22.344 ;
    END
  END d[317]
  PIN d[318]
    DIRECTION INPUT ;
    USE SIGNAL ;
    PORT
      LAYER M4 ;
        RECT  0 22.416 0.084 22.44 ;
    END
  END d[318]
  PIN d[319]
    DIRECTION INPUT ;
    USE SIGNAL ;
    PORT
      LAYER M4 ;
        RECT  0 22.512 0.084 22.536 ;
    END
  END d[319]
  PIN d[31]
    DIRECTION INPUT ;
    USE SIGNAL ;
    PORT
      LAYER M4 ;
        RECT  0 35.568 0.084 35.592 ;
    END
  END d[31]
  PIN d[320]
    DIRECTION INPUT ;
    USE SIGNAL ;
    PORT
      LAYER M4 ;
        RECT  0 16.464 0.084 16.488 ;
    END
  END d[320]
  PIN d[321]
    DIRECTION INPUT ;
    USE SIGNAL ;
    PORT
      LAYER M4 ;
        RECT  0 16.56 0.084 16.584 ;
    END
  END d[321]
  PIN d[322]
    DIRECTION INPUT ;
    USE SIGNAL ;
    PORT
      LAYER M4 ;
        RECT  0 16.656 0.084 16.68 ;
    END
  END d[322]
  PIN d[323]
    DIRECTION INPUT ;
    USE SIGNAL ;
    PORT
      LAYER M4 ;
        RECT  0 16.752 0.084 16.776 ;
    END
  END d[323]
  PIN d[324]
    DIRECTION INPUT ;
    USE SIGNAL ;
    PORT
      LAYER M4 ;
        RECT  0 16.848 0.084 16.872 ;
    END
  END d[324]
  PIN d[325]
    DIRECTION INPUT ;
    USE SIGNAL ;
    PORT
      LAYER M4 ;
        RECT  0 16.944 0.084 16.968 ;
    END
  END d[325]
  PIN d[326]
    DIRECTION INPUT ;
    USE SIGNAL ;
    PORT
      LAYER M4 ;
        RECT  0 17.04 0.084 17.064 ;
    END
  END d[326]
  PIN d[327]
    DIRECTION INPUT ;
    USE SIGNAL ;
    PORT
      LAYER M4 ;
        RECT  0 17.136 0.084 17.16 ;
    END
  END d[327]
  PIN d[328]
    DIRECTION INPUT ;
    USE SIGNAL ;
    PORT
      LAYER M4 ;
        RECT  0 17.232 0.084 17.256 ;
    END
  END d[328]
  PIN d[329]
    DIRECTION INPUT ;
    USE SIGNAL ;
    PORT
      LAYER M4 ;
        RECT  0 17.328 0.084 17.352 ;
    END
  END d[329]
  PIN d[32]
    DIRECTION INPUT ;
    USE SIGNAL ;
    PORT
      LAYER M4 ;
        RECT  0 35.664 0.084 35.688 ;
    END
  END d[32]
  PIN d[330]
    DIRECTION INPUT ;
    USE SIGNAL ;
    PORT
      LAYER M4 ;
        RECT  0 17.424 0.084 17.448 ;
    END
  END d[330]
  PIN d[331]
    DIRECTION INPUT ;
    USE SIGNAL ;
    PORT
      LAYER M4 ;
        RECT  0 17.52 0.084 17.544 ;
    END
  END d[331]
  PIN d[332]
    DIRECTION INPUT ;
    USE SIGNAL ;
    PORT
      LAYER M4 ;
        RECT  0 17.616 0.084 17.64 ;
    END
  END d[332]
  PIN d[333]
    DIRECTION INPUT ;
    USE SIGNAL ;
    PORT
      LAYER M4 ;
        RECT  0 17.712 0.084 17.736 ;
    END
  END d[333]
  PIN d[334]
    DIRECTION INPUT ;
    USE SIGNAL ;
    PORT
      LAYER M4 ;
        RECT  0 17.808 0.084 17.832 ;
    END
  END d[334]
  PIN d[335]
    DIRECTION INPUT ;
    USE SIGNAL ;
    PORT
      LAYER M4 ;
        RECT  0 17.904 0.084 17.928 ;
    END
  END d[335]
  PIN d[336]
    DIRECTION INPUT ;
    USE SIGNAL ;
    PORT
      LAYER M4 ;
        RECT  0 18 0.084 18.024 ;
    END
  END d[336]
  PIN d[337]
    DIRECTION INPUT ;
    USE SIGNAL ;
    PORT
      LAYER M4 ;
        RECT  0 18.096 0.084 18.12 ;
    END
  END d[337]
  PIN d[338]
    DIRECTION INPUT ;
    USE SIGNAL ;
    PORT
      LAYER M4 ;
        RECT  0 18.192 0.084 18.216 ;
    END
  END d[338]
  PIN d[339]
    DIRECTION INPUT ;
    USE SIGNAL ;
    PORT
      LAYER M4 ;
        RECT  0 18.288 0.084 18.312 ;
    END
  END d[339]
  PIN d[33]
    DIRECTION INPUT ;
    USE SIGNAL ;
    PORT
      LAYER M4 ;
        RECT  0 35.76 0.084 35.784 ;
    END
  END d[33]
  PIN d[340]
    DIRECTION INPUT ;
    USE SIGNAL ;
    PORT
      LAYER M4 ;
        RECT  0 18.384 0.084 18.408 ;
    END
  END d[340]
  PIN d[341]
    DIRECTION INPUT ;
    USE SIGNAL ;
    PORT
      LAYER M4 ;
        RECT  0 18.48 0.084 18.504 ;
    END
  END d[341]
  PIN d[342]
    DIRECTION INPUT ;
    USE SIGNAL ;
    PORT
      LAYER M4 ;
        RECT  0 18.576 0.084 18.6 ;
    END
  END d[342]
  PIN d[343]
    DIRECTION INPUT ;
    USE SIGNAL ;
    PORT
      LAYER M4 ;
        RECT  0 18.672 0.084 18.696 ;
    END
  END d[343]
  PIN d[344]
    DIRECTION INPUT ;
    USE SIGNAL ;
    PORT
      LAYER M4 ;
        RECT  0 18.768 0.084 18.792 ;
    END
  END d[344]
  PIN d[345]
    DIRECTION INPUT ;
    USE SIGNAL ;
    PORT
      LAYER M4 ;
        RECT  0 18.864 0.084 18.888 ;
    END
  END d[345]
  PIN d[346]
    DIRECTION INPUT ;
    USE SIGNAL ;
    PORT
      LAYER M4 ;
        RECT  0 18.96 0.084 18.984 ;
    END
  END d[346]
  PIN d[347]
    DIRECTION INPUT ;
    USE SIGNAL ;
    PORT
      LAYER M4 ;
        RECT  0 19.056 0.084 19.08 ;
    END
  END d[347]
  PIN d[348]
    DIRECTION INPUT ;
    USE SIGNAL ;
    PORT
      LAYER M4 ;
        RECT  0 19.152 0.084 19.176 ;
    END
  END d[348]
  PIN d[349]
    DIRECTION INPUT ;
    USE SIGNAL ;
    PORT
      LAYER M4 ;
        RECT  0 19.248 0.084 19.272 ;
    END
  END d[349]
  PIN d[34]
    DIRECTION INPUT ;
    USE SIGNAL ;
    PORT
      LAYER M4 ;
        RECT  0 35.856 0.084 35.88 ;
    END
  END d[34]
  PIN d[350]
    DIRECTION INPUT ;
    USE SIGNAL ;
    PORT
      LAYER M4 ;
        RECT  0 19.344 0.084 19.368 ;
    END
  END d[350]
  PIN d[351]
    DIRECTION INPUT ;
    USE SIGNAL ;
    PORT
      LAYER M4 ;
        RECT  0 19.44 0.084 19.464 ;
    END
  END d[351]
  PIN d[352]
    DIRECTION INPUT ;
    USE SIGNAL ;
    PORT
      LAYER M4 ;
        RECT  0 45.648 0.084 45.672 ;
    END
  END d[352]
  PIN d[353]
    DIRECTION INPUT ;
    USE SIGNAL ;
    PORT
      LAYER M4 ;
        RECT  0 45.744 0.084 45.768 ;
    END
  END d[353]
  PIN d[354]
    DIRECTION INPUT ;
    USE SIGNAL ;
    PORT
      LAYER M4 ;
        RECT  0 45.84 0.084 45.864 ;
    END
  END d[354]
  PIN d[355]
    DIRECTION INPUT ;
    USE SIGNAL ;
    PORT
      LAYER M4 ;
        RECT  0 45.936 0.084 45.96 ;
    END
  END d[355]
  PIN d[356]
    DIRECTION INPUT ;
    USE SIGNAL ;
    PORT
      LAYER M4 ;
        RECT  0 46.032 0.084 46.056 ;
    END
  END d[356]
  PIN d[357]
    DIRECTION INPUT ;
    USE SIGNAL ;
    PORT
      LAYER M4 ;
        RECT  0 46.128 0.084 46.152 ;
    END
  END d[357]
  PIN d[358]
    DIRECTION INPUT ;
    USE SIGNAL ;
    PORT
      LAYER M4 ;
        RECT  0 46.224 0.084 46.248 ;
    END
  END d[358]
  PIN d[359]
    DIRECTION INPUT ;
    USE SIGNAL ;
    PORT
      LAYER M4 ;
        RECT  0 46.32 0.084 46.344 ;
    END
  END d[359]
  PIN d[35]
    DIRECTION INPUT ;
    USE SIGNAL ;
    PORT
      LAYER M4 ;
        RECT  0 35.952 0.084 35.976 ;
    END
  END d[35]
  PIN d[360]
    DIRECTION INPUT ;
    USE SIGNAL ;
    PORT
      LAYER M4 ;
        RECT  0 46.416 0.084 46.44 ;
    END
  END d[360]
  PIN d[361]
    DIRECTION INPUT ;
    USE SIGNAL ;
    PORT
      LAYER M4 ;
        RECT  0 46.512 0.084 46.536 ;
    END
  END d[361]
  PIN d[362]
    DIRECTION INPUT ;
    USE SIGNAL ;
    PORT
      LAYER M4 ;
        RECT  0 46.608 0.084 46.632 ;
    END
  END d[362]
  PIN d[363]
    DIRECTION INPUT ;
    USE SIGNAL ;
    PORT
      LAYER M4 ;
        RECT  0 46.704 0.084 46.728 ;
    END
  END d[363]
  PIN d[364]
    DIRECTION INPUT ;
    USE SIGNAL ;
    PORT
      LAYER M4 ;
        RECT  0 46.8 0.084 46.824 ;
    END
  END d[364]
  PIN d[365]
    DIRECTION INPUT ;
    USE SIGNAL ;
    PORT
      LAYER M4 ;
        RECT  0 46.896 0.084 46.92 ;
    END
  END d[365]
  PIN d[366]
    DIRECTION INPUT ;
    USE SIGNAL ;
    PORT
      LAYER M4 ;
        RECT  0 46.992 0.084 47.016 ;
    END
  END d[366]
  PIN d[367]
    DIRECTION INPUT ;
    USE SIGNAL ;
    PORT
      LAYER M4 ;
        RECT  0 47.088 0.084 47.112 ;
    END
  END d[367]
  PIN d[368]
    DIRECTION INPUT ;
    USE SIGNAL ;
    PORT
      LAYER M4 ;
        RECT  0 47.184 0.084 47.208 ;
    END
  END d[368]
  PIN d[369]
    DIRECTION INPUT ;
    USE SIGNAL ;
    PORT
      LAYER M4 ;
        RECT  0 47.28 0.084 47.304 ;
    END
  END d[369]
  PIN d[36]
    DIRECTION INPUT ;
    USE SIGNAL ;
    PORT
      LAYER M4 ;
        RECT  0 36.048 0.084 36.072 ;
    END
  END d[36]
  PIN d[370]
    DIRECTION INPUT ;
    USE SIGNAL ;
    PORT
      LAYER M4 ;
        RECT  0 47.376 0.084 47.4 ;
    END
  END d[370]
  PIN d[371]
    DIRECTION INPUT ;
    USE SIGNAL ;
    PORT
      LAYER M4 ;
        RECT  0 47.472 0.084 47.496 ;
    END
  END d[371]
  PIN d[372]
    DIRECTION INPUT ;
    USE SIGNAL ;
    PORT
      LAYER M4 ;
        RECT  0 47.568 0.084 47.592 ;
    END
  END d[372]
  PIN d[373]
    DIRECTION INPUT ;
    USE SIGNAL ;
    PORT
      LAYER M4 ;
        RECT  0 47.664 0.084 47.688 ;
    END
  END d[373]
  PIN d[374]
    DIRECTION INPUT ;
    USE SIGNAL ;
    PORT
      LAYER M4 ;
        RECT  0 47.76 0.084 47.784 ;
    END
  END d[374]
  PIN d[375]
    DIRECTION INPUT ;
    USE SIGNAL ;
    PORT
      LAYER M4 ;
        RECT  0 47.856 0.084 47.88 ;
    END
  END d[375]
  PIN d[376]
    DIRECTION INPUT ;
    USE SIGNAL ;
    PORT
      LAYER M4 ;
        RECT  0 47.952 0.084 47.976 ;
    END
  END d[376]
  PIN d[377]
    DIRECTION INPUT ;
    USE SIGNAL ;
    PORT
      LAYER M4 ;
        RECT  0 48.048 0.084 48.072 ;
    END
  END d[377]
  PIN d[378]
    DIRECTION INPUT ;
    USE SIGNAL ;
    PORT
      LAYER M4 ;
        RECT  0 48.144 0.084 48.168 ;
    END
  END d[378]
  PIN d[379]
    DIRECTION INPUT ;
    USE SIGNAL ;
    PORT
      LAYER M4 ;
        RECT  0 48.24 0.084 48.264 ;
    END
  END d[379]
  PIN d[37]
    DIRECTION INPUT ;
    USE SIGNAL ;
    PORT
      LAYER M4 ;
        RECT  0 36.144 0.084 36.168 ;
    END
  END d[37]
  PIN d[380]
    DIRECTION INPUT ;
    USE SIGNAL ;
    PORT
      LAYER M4 ;
        RECT  0 48.336 0.084 48.36 ;
    END
  END d[380]
  PIN d[381]
    DIRECTION INPUT ;
    USE SIGNAL ;
    PORT
      LAYER M4 ;
        RECT  0 48.432 0.084 48.456 ;
    END
  END d[381]
  PIN d[382]
    DIRECTION INPUT ;
    USE SIGNAL ;
    PORT
      LAYER M4 ;
        RECT  0 48.528 0.084 48.552 ;
    END
  END d[382]
  PIN d[383]
    DIRECTION INPUT ;
    USE SIGNAL ;
    PORT
      LAYER M4 ;
        RECT  0 48.624 0.084 48.648 ;
    END
  END d[383]
  PIN d[384]
    DIRECTION INPUT ;
    USE SIGNAL ;
    PORT
      LAYER M4 ;
        RECT  0 51.792 0.084 51.816 ;
    END
  END d[384]
  PIN d[385]
    DIRECTION INPUT ;
    USE SIGNAL ;
    PORT
      LAYER M4 ;
        RECT  0 51.888 0.084 51.912 ;
    END
  END d[385]
  PIN d[386]
    DIRECTION INPUT ;
    USE SIGNAL ;
    PORT
      LAYER M4 ;
        RECT  0 51.984 0.084 52.008 ;
    END
  END d[386]
  PIN d[387]
    DIRECTION INPUT ;
    USE SIGNAL ;
    PORT
      LAYER M4 ;
        RECT  0 52.08 0.084 52.104 ;
    END
  END d[387]
  PIN d[388]
    DIRECTION INPUT ;
    USE SIGNAL ;
    PORT
      LAYER M4 ;
        RECT  0 52.176 0.084 52.2 ;
    END
  END d[388]
  PIN d[389]
    DIRECTION INPUT ;
    USE SIGNAL ;
    PORT
      LAYER M4 ;
        RECT  0 52.272 0.084 52.296 ;
    END
  END d[389]
  PIN d[38]
    DIRECTION INPUT ;
    USE SIGNAL ;
    PORT
      LAYER M4 ;
        RECT  0 36.24 0.084 36.264 ;
    END
  END d[38]
  PIN d[390]
    DIRECTION INPUT ;
    USE SIGNAL ;
    PORT
      LAYER M4 ;
        RECT  0 52.368 0.084 52.392 ;
    END
  END d[390]
  PIN d[391]
    DIRECTION INPUT ;
    USE SIGNAL ;
    PORT
      LAYER M4 ;
        RECT  0 52.464 0.084 52.488 ;
    END
  END d[391]
  PIN d[392]
    DIRECTION INPUT ;
    USE SIGNAL ;
    PORT
      LAYER M4 ;
        RECT  0 52.56 0.084 52.584 ;
    END
  END d[392]
  PIN d[393]
    DIRECTION INPUT ;
    USE SIGNAL ;
    PORT
      LAYER M4 ;
        RECT  0 52.656 0.084 52.68 ;
    END
  END d[393]
  PIN d[394]
    DIRECTION INPUT ;
    USE SIGNAL ;
    PORT
      LAYER M4 ;
        RECT  0 52.752 0.084 52.776 ;
    END
  END d[394]
  PIN d[395]
    DIRECTION INPUT ;
    USE SIGNAL ;
    PORT
      LAYER M4 ;
        RECT  0 52.848 0.084 52.872 ;
    END
  END d[395]
  PIN d[396]
    DIRECTION INPUT ;
    USE SIGNAL ;
    PORT
      LAYER M4 ;
        RECT  0 52.944 0.084 52.968 ;
    END
  END d[396]
  PIN d[397]
    DIRECTION INPUT ;
    USE SIGNAL ;
    PORT
      LAYER M4 ;
        RECT  0 53.04 0.084 53.064 ;
    END
  END d[397]
  PIN d[398]
    DIRECTION INPUT ;
    USE SIGNAL ;
    PORT
      LAYER M4 ;
        RECT  0 53.136 0.084 53.16 ;
    END
  END d[398]
  PIN d[399]
    DIRECTION INPUT ;
    USE SIGNAL ;
    PORT
      LAYER M4 ;
        RECT  0 53.232 0.084 53.256 ;
    END
  END d[399]
  PIN d[39]
    DIRECTION INPUT ;
    USE SIGNAL ;
    PORT
      LAYER M4 ;
        RECT  0 36.336 0.084 36.36 ;
    END
  END d[39]
  PIN d[3]
    DIRECTION INPUT ;
    USE SIGNAL ;
    PORT
      LAYER M4 ;
        RECT  0 32.88 0.084 32.904 ;
    END
  END d[3]
  PIN d[400]
    DIRECTION INPUT ;
    USE SIGNAL ;
    PORT
      LAYER M4 ;
        RECT  0 53.328 0.084 53.352 ;
    END
  END d[400]
  PIN d[401]
    DIRECTION INPUT ;
    USE SIGNAL ;
    PORT
      LAYER M4 ;
        RECT  0 53.424 0.084 53.448 ;
    END
  END d[401]
  PIN d[402]
    DIRECTION INPUT ;
    USE SIGNAL ;
    PORT
      LAYER M4 ;
        RECT  0 53.52 0.084 53.544 ;
    END
  END d[402]
  PIN d[403]
    DIRECTION INPUT ;
    USE SIGNAL ;
    PORT
      LAYER M4 ;
        RECT  0 53.616 0.084 53.64 ;
    END
  END d[403]
  PIN d[404]
    DIRECTION INPUT ;
    USE SIGNAL ;
    PORT
      LAYER M4 ;
        RECT  0 53.712 0.084 53.736 ;
    END
  END d[404]
  PIN d[405]
    DIRECTION INPUT ;
    USE SIGNAL ;
    PORT
      LAYER M4 ;
        RECT  0 53.808 0.084 53.832 ;
    END
  END d[405]
  PIN d[406]
    DIRECTION INPUT ;
    USE SIGNAL ;
    PORT
      LAYER M4 ;
        RECT  0 53.904 0.084 53.928 ;
    END
  END d[406]
  PIN d[407]
    DIRECTION INPUT ;
    USE SIGNAL ;
    PORT
      LAYER M4 ;
        RECT  0 54 0.084 54.024 ;
    END
  END d[407]
  PIN d[408]
    DIRECTION INPUT ;
    USE SIGNAL ;
    PORT
      LAYER M4 ;
        RECT  0 54.096 0.084 54.12 ;
    END
  END d[408]
  PIN d[409]
    DIRECTION INPUT ;
    USE SIGNAL ;
    PORT
      LAYER M4 ;
        RECT  0 54.192 0.084 54.216 ;
    END
  END d[409]
  PIN d[40]
    DIRECTION INPUT ;
    USE SIGNAL ;
    PORT
      LAYER M4 ;
        RECT  0 36.432 0.084 36.456 ;
    END
  END d[40]
  PIN d[410]
    DIRECTION INPUT ;
    USE SIGNAL ;
    PORT
      LAYER M4 ;
        RECT  0 54.288 0.084 54.312 ;
    END
  END d[410]
  PIN d[411]
    DIRECTION INPUT ;
    USE SIGNAL ;
    PORT
      LAYER M4 ;
        RECT  0 54.384 0.084 54.408 ;
    END
  END d[411]
  PIN d[412]
    DIRECTION INPUT ;
    USE SIGNAL ;
    PORT
      LAYER M4 ;
        RECT  0 54.48 0.084 54.504 ;
    END
  END d[412]
  PIN d[413]
    DIRECTION INPUT ;
    USE SIGNAL ;
    PORT
      LAYER M4 ;
        RECT  0 54.576 0.084 54.6 ;
    END
  END d[413]
  PIN d[414]
    DIRECTION INPUT ;
    USE SIGNAL ;
    PORT
      LAYER M4 ;
        RECT  0 54.672 0.084 54.696 ;
    END
  END d[414]
  PIN d[415]
    DIRECTION INPUT ;
    USE SIGNAL ;
    PORT
      LAYER M4 ;
        RECT  0 54.768 0.084 54.792 ;
    END
  END d[415]
  PIN d[416]
    DIRECTION INPUT ;
    USE SIGNAL ;
    PORT
      LAYER M4 ;
        RECT  0 54.864 0.084 54.888 ;
    END
  END d[416]
  PIN d[417]
    DIRECTION INPUT ;
    USE SIGNAL ;
    PORT
      LAYER M4 ;
        RECT  0 54.96 0.084 54.984 ;
    END
  END d[417]
  PIN d[418]
    DIRECTION INPUT ;
    USE SIGNAL ;
    PORT
      LAYER M4 ;
        RECT  0 55.056 0.084 55.08 ;
    END
  END d[418]
  PIN d[419]
    DIRECTION INPUT ;
    USE SIGNAL ;
    PORT
      LAYER M4 ;
        RECT  0 55.152 0.084 55.176 ;
    END
  END d[419]
  PIN d[41]
    DIRECTION INPUT ;
    USE SIGNAL ;
    PORT
      LAYER M4 ;
        RECT  0 36.528 0.084 36.552 ;
    END
  END d[41]
  PIN d[420]
    DIRECTION INPUT ;
    USE SIGNAL ;
    PORT
      LAYER M4 ;
        RECT  0 55.248 0.084 55.272 ;
    END
  END d[420]
  PIN d[421]
    DIRECTION INPUT ;
    USE SIGNAL ;
    PORT
      LAYER M4 ;
        RECT  0 55.344 0.084 55.368 ;
    END
  END d[421]
  PIN d[422]
    DIRECTION INPUT ;
    USE SIGNAL ;
    PORT
      LAYER M4 ;
        RECT  0 55.44 0.084 55.464 ;
    END
  END d[422]
  PIN d[423]
    DIRECTION INPUT ;
    USE SIGNAL ;
    PORT
      LAYER M4 ;
        RECT  0 55.536 0.084 55.56 ;
    END
  END d[423]
  PIN d[424]
    DIRECTION INPUT ;
    USE SIGNAL ;
    PORT
      LAYER M4 ;
        RECT  0 55.632 0.084 55.656 ;
    END
  END d[424]
  PIN d[425]
    DIRECTION INPUT ;
    USE SIGNAL ;
    PORT
      LAYER M4 ;
        RECT  0 55.728 0.084 55.752 ;
    END
  END d[425]
  PIN d[426]
    DIRECTION INPUT ;
    USE SIGNAL ;
    PORT
      LAYER M4 ;
        RECT  0 55.824 0.084 55.848 ;
    END
  END d[426]
  PIN d[427]
    DIRECTION INPUT ;
    USE SIGNAL ;
    PORT
      LAYER M4 ;
        RECT  0 55.92 0.084 55.944 ;
    END
  END d[427]
  PIN d[428]
    DIRECTION INPUT ;
    USE SIGNAL ;
    PORT
      LAYER M4 ;
        RECT  0 56.016 0.084 56.04 ;
    END
  END d[428]
  PIN d[429]
    DIRECTION INPUT ;
    USE SIGNAL ;
    PORT
      LAYER M4 ;
        RECT  0 56.112 0.084 56.136 ;
    END
  END d[429]
  PIN d[42]
    DIRECTION INPUT ;
    USE SIGNAL ;
    PORT
      LAYER M4 ;
        RECT  0 36.624 0.084 36.648 ;
    END
  END d[42]
  PIN d[430]
    DIRECTION INPUT ;
    USE SIGNAL ;
    PORT
      LAYER M4 ;
        RECT  0 56.208 0.084 56.232 ;
    END
  END d[430]
  PIN d[431]
    DIRECTION INPUT ;
    USE SIGNAL ;
    PORT
      LAYER M4 ;
        RECT  0 56.304 0.084 56.328 ;
    END
  END d[431]
  PIN d[432]
    DIRECTION INPUT ;
    USE SIGNAL ;
    PORT
      LAYER M4 ;
        RECT  0 56.4 0.084 56.424 ;
    END
  END d[432]
  PIN d[433]
    DIRECTION INPUT ;
    USE SIGNAL ;
    PORT
      LAYER M4 ;
        RECT  0 56.496 0.084 56.52 ;
    END
  END d[433]
  PIN d[434]
    DIRECTION INPUT ;
    USE SIGNAL ;
    PORT
      LAYER M4 ;
        RECT  0 56.592 0.084 56.616 ;
    END
  END d[434]
  PIN d[435]
    DIRECTION INPUT ;
    USE SIGNAL ;
    PORT
      LAYER M4 ;
        RECT  0 56.688 0.084 56.712 ;
    END
  END d[435]
  PIN d[436]
    DIRECTION INPUT ;
    USE SIGNAL ;
    PORT
      LAYER M4 ;
        RECT  0 56.784 0.084 56.808 ;
    END
  END d[436]
  PIN d[437]
    DIRECTION INPUT ;
    USE SIGNAL ;
    PORT
      LAYER M4 ;
        RECT  0 56.88 0.084 56.904 ;
    END
  END d[437]
  PIN d[438]
    DIRECTION INPUT ;
    USE SIGNAL ;
    PORT
      LAYER M4 ;
        RECT  0 56.976 0.084 57 ;
    END
  END d[438]
  PIN d[439]
    DIRECTION INPUT ;
    USE SIGNAL ;
    PORT
      LAYER M4 ;
        RECT  0 57.072 0.084 57.096 ;
    END
  END d[439]
  PIN d[43]
    DIRECTION INPUT ;
    USE SIGNAL ;
    PORT
      LAYER M4 ;
        RECT  0 36.72 0.084 36.744 ;
    END
  END d[43]
  PIN d[440]
    DIRECTION INPUT ;
    USE SIGNAL ;
    PORT
      LAYER M4 ;
        RECT  0 57.168 0.084 57.192 ;
    END
  END d[440]
  PIN d[441]
    DIRECTION INPUT ;
    USE SIGNAL ;
    PORT
      LAYER M4 ;
        RECT  0 57.264 0.084 57.288 ;
    END
  END d[441]
  PIN d[442]
    DIRECTION INPUT ;
    USE SIGNAL ;
    PORT
      LAYER M4 ;
        RECT  0 57.36 0.084 57.384 ;
    END
  END d[442]
  PIN d[443]
    DIRECTION INPUT ;
    USE SIGNAL ;
    PORT
      LAYER M4 ;
        RECT  0 57.456 0.084 57.48 ;
    END
  END d[443]
  PIN d[444]
    DIRECTION INPUT ;
    USE SIGNAL ;
    PORT
      LAYER M4 ;
        RECT  0 57.552 0.084 57.576 ;
    END
  END d[444]
  PIN d[445]
    DIRECTION INPUT ;
    USE SIGNAL ;
    PORT
      LAYER M4 ;
        RECT  0 57.648 0.084 57.672 ;
    END
  END d[445]
  PIN d[446]
    DIRECTION INPUT ;
    USE SIGNAL ;
    PORT
      LAYER M4 ;
        RECT  0 57.744 0.084 57.768 ;
    END
  END d[446]
  PIN d[447]
    DIRECTION INPUT ;
    USE SIGNAL ;
    PORT
      LAYER M4 ;
        RECT  0 57.84 0.084 57.864 ;
    END
  END d[447]
  PIN d[448]
    DIRECTION INPUT ;
    USE SIGNAL ;
    PORT
      LAYER M4 ;
        RECT  0 7.248 0.084 7.272 ;
    END
  END d[448]
  PIN d[449]
    DIRECTION INPUT ;
    USE SIGNAL ;
    PORT
      LAYER M4 ;
        RECT  0 7.344 0.084 7.368 ;
    END
  END d[449]
  PIN d[44]
    DIRECTION INPUT ;
    USE SIGNAL ;
    PORT
      LAYER M4 ;
        RECT  0 36.816 0.084 36.84 ;
    END
  END d[44]
  PIN d[450]
    DIRECTION INPUT ;
    USE SIGNAL ;
    PORT
      LAYER M4 ;
        RECT  0 7.44 0.084 7.464 ;
    END
  END d[450]
  PIN d[451]
    DIRECTION INPUT ;
    USE SIGNAL ;
    PORT
      LAYER M4 ;
        RECT  0 7.536 0.084 7.56 ;
    END
  END d[451]
  PIN d[452]
    DIRECTION INPUT ;
    USE SIGNAL ;
    PORT
      LAYER M4 ;
        RECT  0 7.632 0.084 7.656 ;
    END
  END d[452]
  PIN d[453]
    DIRECTION INPUT ;
    USE SIGNAL ;
    PORT
      LAYER M4 ;
        RECT  0 7.728 0.084 7.752 ;
    END
  END d[453]
  PIN d[454]
    DIRECTION INPUT ;
    USE SIGNAL ;
    PORT
      LAYER M4 ;
        RECT  0 7.824 0.084 7.848 ;
    END
  END d[454]
  PIN d[455]
    DIRECTION INPUT ;
    USE SIGNAL ;
    PORT
      LAYER M4 ;
        RECT  0 7.92 0.084 7.944 ;
    END
  END d[455]
  PIN d[456]
    DIRECTION INPUT ;
    USE SIGNAL ;
    PORT
      LAYER M4 ;
        RECT  0 8.016 0.084 8.04 ;
    END
  END d[456]
  PIN d[457]
    DIRECTION INPUT ;
    USE SIGNAL ;
    PORT
      LAYER M4 ;
        RECT  0 8.112 0.084 8.136 ;
    END
  END d[457]
  PIN d[458]
    DIRECTION INPUT ;
    USE SIGNAL ;
    PORT
      LAYER M4 ;
        RECT  0 8.208 0.084 8.232 ;
    END
  END d[458]
  PIN d[459]
    DIRECTION INPUT ;
    USE SIGNAL ;
    PORT
      LAYER M4 ;
        RECT  0 8.304 0.084 8.328 ;
    END
  END d[459]
  PIN d[45]
    DIRECTION INPUT ;
    USE SIGNAL ;
    PORT
      LAYER M4 ;
        RECT  0 36.912 0.084 36.936 ;
    END
  END d[45]
  PIN d[460]
    DIRECTION INPUT ;
    USE SIGNAL ;
    PORT
      LAYER M4 ;
        RECT  0 8.4 0.084 8.424 ;
    END
  END d[460]
  PIN d[461]
    DIRECTION INPUT ;
    USE SIGNAL ;
    PORT
      LAYER M4 ;
        RECT  0 8.496 0.084 8.52 ;
    END
  END d[461]
  PIN d[462]
    DIRECTION INPUT ;
    USE SIGNAL ;
    PORT
      LAYER M4 ;
        RECT  0 8.592 0.084 8.616 ;
    END
  END d[462]
  PIN d[463]
    DIRECTION INPUT ;
    USE SIGNAL ;
    PORT
      LAYER M4 ;
        RECT  0 8.688 0.084 8.712 ;
    END
  END d[463]
  PIN d[464]
    DIRECTION INPUT ;
    USE SIGNAL ;
    PORT
      LAYER M4 ;
        RECT  0 8.784 0.084 8.808 ;
    END
  END d[464]
  PIN d[465]
    DIRECTION INPUT ;
    USE SIGNAL ;
    PORT
      LAYER M4 ;
        RECT  0 8.88 0.084 8.904 ;
    END
  END d[465]
  PIN d[466]
    DIRECTION INPUT ;
    USE SIGNAL ;
    PORT
      LAYER M4 ;
        RECT  0 8.976 0.084 9 ;
    END
  END d[466]
  PIN d[467]
    DIRECTION INPUT ;
    USE SIGNAL ;
    PORT
      LAYER M4 ;
        RECT  0 9.072 0.084 9.096 ;
    END
  END d[467]
  PIN d[468]
    DIRECTION INPUT ;
    USE SIGNAL ;
    PORT
      LAYER M4 ;
        RECT  0 9.168 0.084 9.192 ;
    END
  END d[468]
  PIN d[469]
    DIRECTION INPUT ;
    USE SIGNAL ;
    PORT
      LAYER M4 ;
        RECT  0 9.264 0.084 9.288 ;
    END
  END d[469]
  PIN d[46]
    DIRECTION INPUT ;
    USE SIGNAL ;
    PORT
      LAYER M4 ;
        RECT  0 37.008 0.084 37.032 ;
    END
  END d[46]
  PIN d[470]
    DIRECTION INPUT ;
    USE SIGNAL ;
    PORT
      LAYER M4 ;
        RECT  0 9.36 0.084 9.384 ;
    END
  END d[470]
  PIN d[471]
    DIRECTION INPUT ;
    USE SIGNAL ;
    PORT
      LAYER M4 ;
        RECT  0 9.456 0.084 9.48 ;
    END
  END d[471]
  PIN d[472]
    DIRECTION INPUT ;
    USE SIGNAL ;
    PORT
      LAYER M4 ;
        RECT  0 9.552 0.084 9.576 ;
    END
  END d[472]
  PIN d[473]
    DIRECTION INPUT ;
    USE SIGNAL ;
    PORT
      LAYER M4 ;
        RECT  0 9.648 0.084 9.672 ;
    END
  END d[473]
  PIN d[474]
    DIRECTION INPUT ;
    USE SIGNAL ;
    PORT
      LAYER M4 ;
        RECT  0 9.744 0.084 9.768 ;
    END
  END d[474]
  PIN d[475]
    DIRECTION INPUT ;
    USE SIGNAL ;
    PORT
      LAYER M4 ;
        RECT  0 9.84 0.084 9.864 ;
    END
  END d[475]
  PIN d[476]
    DIRECTION INPUT ;
    USE SIGNAL ;
    PORT
      LAYER M4 ;
        RECT  0 9.936 0.084 9.96 ;
    END
  END d[476]
  PIN d[477]
    DIRECTION INPUT ;
    USE SIGNAL ;
    PORT
      LAYER M4 ;
        RECT  0 10.032 0.084 10.056 ;
    END
  END d[477]
  PIN d[478]
    DIRECTION INPUT ;
    USE SIGNAL ;
    PORT
      LAYER M4 ;
        RECT  0 10.128 0.084 10.152 ;
    END
  END d[478]
  PIN d[479]
    DIRECTION INPUT ;
    USE SIGNAL ;
    PORT
      LAYER M4 ;
        RECT  0 10.224 0.084 10.248 ;
    END
  END d[479]
  PIN d[47]
    DIRECTION INPUT ;
    USE SIGNAL ;
    PORT
      LAYER M4 ;
        RECT  0 37.104 0.084 37.128 ;
    END
  END d[47]
  PIN d[480]
    DIRECTION INPUT ;
    USE SIGNAL ;
    PORT
      LAYER M4 ;
        RECT  0 13.392 0.084 13.416 ;
    END
  END d[480]
  PIN d[481]
    DIRECTION INPUT ;
    USE SIGNAL ;
    PORT
      LAYER M4 ;
        RECT  0 13.488 0.084 13.512 ;
    END
  END d[481]
  PIN d[482]
    DIRECTION INPUT ;
    USE SIGNAL ;
    PORT
      LAYER M4 ;
        RECT  0 13.584 0.084 13.608 ;
    END
  END d[482]
  PIN d[483]
    DIRECTION INPUT ;
    USE SIGNAL ;
    PORT
      LAYER M4 ;
        RECT  0 13.68 0.084 13.704 ;
    END
  END d[483]
  PIN d[484]
    DIRECTION INPUT ;
    USE SIGNAL ;
    PORT
      LAYER M4 ;
        RECT  0 13.776 0.084 13.8 ;
    END
  END d[484]
  PIN d[485]
    DIRECTION INPUT ;
    USE SIGNAL ;
    PORT
      LAYER M4 ;
        RECT  0 13.872 0.084 13.896 ;
    END
  END d[485]
  PIN d[486]
    DIRECTION INPUT ;
    USE SIGNAL ;
    PORT
      LAYER M4 ;
        RECT  0 13.968 0.084 13.992 ;
    END
  END d[486]
  PIN d[487]
    DIRECTION INPUT ;
    USE SIGNAL ;
    PORT
      LAYER M4 ;
        RECT  0 14.064 0.084 14.088 ;
    END
  END d[487]
  PIN d[488]
    DIRECTION INPUT ;
    USE SIGNAL ;
    PORT
      LAYER M4 ;
        RECT  0 14.16 0.084 14.184 ;
    END
  END d[488]
  PIN d[489]
    DIRECTION INPUT ;
    USE SIGNAL ;
    PORT
      LAYER M4 ;
        RECT  0 14.256 0.084 14.28 ;
    END
  END d[489]
  PIN d[48]
    DIRECTION INPUT ;
    USE SIGNAL ;
    PORT
      LAYER M4 ;
        RECT  0 37.2 0.084 37.224 ;
    END
  END d[48]
  PIN d[490]
    DIRECTION INPUT ;
    USE SIGNAL ;
    PORT
      LAYER M4 ;
        RECT  0 14.352 0.084 14.376 ;
    END
  END d[490]
  PIN d[491]
    DIRECTION INPUT ;
    USE SIGNAL ;
    PORT
      LAYER M4 ;
        RECT  0 14.448 0.084 14.472 ;
    END
  END d[491]
  PIN d[492]
    DIRECTION INPUT ;
    USE SIGNAL ;
    PORT
      LAYER M4 ;
        RECT  0 14.544 0.084 14.568 ;
    END
  END d[492]
  PIN d[493]
    DIRECTION INPUT ;
    USE SIGNAL ;
    PORT
      LAYER M4 ;
        RECT  0 14.64 0.084 14.664 ;
    END
  END d[493]
  PIN d[494]
    DIRECTION INPUT ;
    USE SIGNAL ;
    PORT
      LAYER M4 ;
        RECT  0 14.736 0.084 14.76 ;
    END
  END d[494]
  PIN d[495]
    DIRECTION INPUT ;
    USE SIGNAL ;
    PORT
      LAYER M4 ;
        RECT  0 14.832 0.084 14.856 ;
    END
  END d[495]
  PIN d[496]
    DIRECTION INPUT ;
    USE SIGNAL ;
    PORT
      LAYER M4 ;
        RECT  0 14.928 0.084 14.952 ;
    END
  END d[496]
  PIN d[497]
    DIRECTION INPUT ;
    USE SIGNAL ;
    PORT
      LAYER M4 ;
        RECT  0 15.024 0.084 15.048 ;
    END
  END d[497]
  PIN d[498]
    DIRECTION INPUT ;
    USE SIGNAL ;
    PORT
      LAYER M4 ;
        RECT  0 15.12 0.084 15.144 ;
    END
  END d[498]
  PIN d[499]
    DIRECTION INPUT ;
    USE SIGNAL ;
    PORT
      LAYER M4 ;
        RECT  0 15.216 0.084 15.24 ;
    END
  END d[499]
  PIN d[49]
    DIRECTION INPUT ;
    USE SIGNAL ;
    PORT
      LAYER M4 ;
        RECT  0 37.296 0.084 37.32 ;
    END
  END d[49]
  PIN d[4]
    DIRECTION INPUT ;
    USE SIGNAL ;
    PORT
      LAYER M4 ;
        RECT  0 32.976 0.084 33 ;
    END
  END d[4]
  PIN d[500]
    DIRECTION INPUT ;
    USE SIGNAL ;
    PORT
      LAYER M4 ;
        RECT  0 15.312 0.084 15.336 ;
    END
  END d[500]
  PIN d[501]
    DIRECTION INPUT ;
    USE SIGNAL ;
    PORT
      LAYER M4 ;
        RECT  0 15.408 0.084 15.432 ;
    END
  END d[501]
  PIN d[502]
    DIRECTION INPUT ;
    USE SIGNAL ;
    PORT
      LAYER M4 ;
        RECT  0 15.504 0.084 15.528 ;
    END
  END d[502]
  PIN d[503]
    DIRECTION INPUT ;
    USE SIGNAL ;
    PORT
      LAYER M4 ;
        RECT  0 15.6 0.084 15.624 ;
    END
  END d[503]
  PIN d[504]
    DIRECTION INPUT ;
    USE SIGNAL ;
    PORT
      LAYER M4 ;
        RECT  0 15.696 0.084 15.72 ;
    END
  END d[504]
  PIN d[505]
    DIRECTION INPUT ;
    USE SIGNAL ;
    PORT
      LAYER M4 ;
        RECT  0 15.792 0.084 15.816 ;
    END
  END d[505]
  PIN d[506]
    DIRECTION INPUT ;
    USE SIGNAL ;
    PORT
      LAYER M4 ;
        RECT  0 15.888 0.084 15.912 ;
    END
  END d[506]
  PIN d[507]
    DIRECTION INPUT ;
    USE SIGNAL ;
    PORT
      LAYER M4 ;
        RECT  0 15.984 0.084 16.008 ;
    END
  END d[507]
  PIN d[508]
    DIRECTION INPUT ;
    USE SIGNAL ;
    PORT
      LAYER M4 ;
        RECT  0 16.08 0.084 16.104 ;
    END
  END d[508]
  PIN d[509]
    DIRECTION INPUT ;
    USE SIGNAL ;
    PORT
      LAYER M4 ;
        RECT  0 16.176 0.084 16.2 ;
    END
  END d[509]
  PIN d[50]
    DIRECTION INPUT ;
    USE SIGNAL ;
    PORT
      LAYER M4 ;
        RECT  0 37.392 0.084 37.416 ;
    END
  END d[50]
  PIN d[510]
    DIRECTION INPUT ;
    USE SIGNAL ;
    PORT
      LAYER M4 ;
        RECT  0 16.272 0.084 16.296 ;
    END
  END d[510]
  PIN d[511]
    DIRECTION INPUT ;
    USE SIGNAL ;
    PORT
      LAYER M4 ;
        RECT  0 16.368 0.084 16.392 ;
    END
  END d[511]
  PIN d[51]
    DIRECTION INPUT ;
    USE SIGNAL ;
    PORT
      LAYER M4 ;
        RECT  0 37.488 0.084 37.512 ;
    END
  END d[51]
  PIN d[52]
    DIRECTION INPUT ;
    USE SIGNAL ;
    PORT
      LAYER M4 ;
        RECT  0 37.584 0.084 37.608 ;
    END
  END d[52]
  PIN d[53]
    DIRECTION INPUT ;
    USE SIGNAL ;
    PORT
      LAYER M4 ;
        RECT  0 37.68 0.084 37.704 ;
    END
  END d[53]
  PIN d[54]
    DIRECTION INPUT ;
    USE SIGNAL ;
    PORT
      LAYER M4 ;
        RECT  0 37.776 0.084 37.8 ;
    END
  END d[54]
  PIN d[55]
    DIRECTION INPUT ;
    USE SIGNAL ;
    PORT
      LAYER M4 ;
        RECT  0 37.872 0.084 37.896 ;
    END
  END d[55]
  PIN d[56]
    DIRECTION INPUT ;
    USE SIGNAL ;
    PORT
      LAYER M4 ;
        RECT  0 37.968 0.084 37.992 ;
    END
  END d[56]
  PIN d[57]
    DIRECTION INPUT ;
    USE SIGNAL ;
    PORT
      LAYER M4 ;
        RECT  0 38.064 0.084 38.088 ;
    END
  END d[57]
  PIN d[58]
    DIRECTION INPUT ;
    USE SIGNAL ;
    PORT
      LAYER M4 ;
        RECT  0 38.16 0.084 38.184 ;
    END
  END d[58]
  PIN d[59]
    DIRECTION INPUT ;
    USE SIGNAL ;
    PORT
      LAYER M4 ;
        RECT  0 38.256 0.084 38.28 ;
    END
  END d[59]
  PIN d[5]
    DIRECTION INPUT ;
    USE SIGNAL ;
    PORT
      LAYER M4 ;
        RECT  0 33.072 0.084 33.096 ;
    END
  END d[5]
  PIN d[60]
    DIRECTION INPUT ;
    USE SIGNAL ;
    PORT
      LAYER M4 ;
        RECT  0 38.352 0.084 38.376 ;
    END
  END d[60]
  PIN d[61]
    DIRECTION INPUT ;
    USE SIGNAL ;
    PORT
      LAYER M4 ;
        RECT  0 38.448 0.084 38.472 ;
    END
  END d[61]
  PIN d[62]
    DIRECTION INPUT ;
    USE SIGNAL ;
    PORT
      LAYER M4 ;
        RECT  0 38.544 0.084 38.568 ;
    END
  END d[62]
  PIN d[63]
    DIRECTION INPUT ;
    USE SIGNAL ;
    PORT
      LAYER M4 ;
        RECT  0 38.64 0.084 38.664 ;
    END
  END d[63]
  PIN d[64]
    DIRECTION INPUT ;
    USE SIGNAL ;
    PORT
      LAYER M4 ;
        RECT  0 26.448 0.084 26.472 ;
    END
  END d[64]
  PIN d[65]
    DIRECTION INPUT ;
    USE SIGNAL ;
    PORT
      LAYER M4 ;
        RECT  0 26.544 0.084 26.568 ;
    END
  END d[65]
  PIN d[66]
    DIRECTION INPUT ;
    USE SIGNAL ;
    PORT
      LAYER M4 ;
        RECT  0 26.64 0.084 26.664 ;
    END
  END d[66]
  PIN d[67]
    DIRECTION INPUT ;
    USE SIGNAL ;
    PORT
      LAYER M4 ;
        RECT  0 26.736 0.084 26.76 ;
    END
  END d[67]
  PIN d[68]
    DIRECTION INPUT ;
    USE SIGNAL ;
    PORT
      LAYER M4 ;
        RECT  0 26.832 0.084 26.856 ;
    END
  END d[68]
  PIN d[69]
    DIRECTION INPUT ;
    USE SIGNAL ;
    PORT
      LAYER M4 ;
        RECT  0 26.928 0.084 26.952 ;
    END
  END d[69]
  PIN d[6]
    DIRECTION INPUT ;
    USE SIGNAL ;
    PORT
      LAYER M4 ;
        RECT  0 33.168 0.084 33.192 ;
    END
  END d[6]
  PIN d[70]
    DIRECTION INPUT ;
    USE SIGNAL ;
    PORT
      LAYER M4 ;
        RECT  0 27.024 0.084 27.048 ;
    END
  END d[70]
  PIN d[71]
    DIRECTION INPUT ;
    USE SIGNAL ;
    PORT
      LAYER M4 ;
        RECT  0 27.12 0.084 27.144 ;
    END
  END d[71]
  PIN d[72]
    DIRECTION INPUT ;
    USE SIGNAL ;
    PORT
      LAYER M4 ;
        RECT  0 27.216 0.084 27.24 ;
    END
  END d[72]
  PIN d[73]
    DIRECTION INPUT ;
    USE SIGNAL ;
    PORT
      LAYER M4 ;
        RECT  0 27.312 0.084 27.336 ;
    END
  END d[73]
  PIN d[74]
    DIRECTION INPUT ;
    USE SIGNAL ;
    PORT
      LAYER M4 ;
        RECT  0 27.408 0.084 27.432 ;
    END
  END d[74]
  PIN d[75]
    DIRECTION INPUT ;
    USE SIGNAL ;
    PORT
      LAYER M4 ;
        RECT  0 27.504 0.084 27.528 ;
    END
  END d[75]
  PIN d[76]
    DIRECTION INPUT ;
    USE SIGNAL ;
    PORT
      LAYER M4 ;
        RECT  0 27.6 0.084 27.624 ;
    END
  END d[76]
  PIN d[77]
    DIRECTION INPUT ;
    USE SIGNAL ;
    PORT
      LAYER M4 ;
        RECT  0 27.696 0.084 27.72 ;
    END
  END d[77]
  PIN d[78]
    DIRECTION INPUT ;
    USE SIGNAL ;
    PORT
      LAYER M4 ;
        RECT  0 27.792 0.084 27.816 ;
    END
  END d[78]
  PIN d[79]
    DIRECTION INPUT ;
    USE SIGNAL ;
    PORT
      LAYER M4 ;
        RECT  0 27.888 0.084 27.912 ;
    END
  END d[79]
  PIN d[7]
    DIRECTION INPUT ;
    USE SIGNAL ;
    PORT
      LAYER M4 ;
        RECT  0 33.264 0.084 33.288 ;
    END
  END d[7]
  PIN d[80]
    DIRECTION INPUT ;
    USE SIGNAL ;
    PORT
      LAYER M4 ;
        RECT  0 27.984 0.084 28.008 ;
    END
  END d[80]
  PIN d[81]
    DIRECTION INPUT ;
    USE SIGNAL ;
    PORT
      LAYER M4 ;
        RECT  0 28.08 0.084 28.104 ;
    END
  END d[81]
  PIN d[82]
    DIRECTION INPUT ;
    USE SIGNAL ;
    PORT
      LAYER M4 ;
        RECT  0 28.176 0.084 28.2 ;
    END
  END d[82]
  PIN d[83]
    DIRECTION INPUT ;
    USE SIGNAL ;
    PORT
      LAYER M4 ;
        RECT  0 28.272 0.084 28.296 ;
    END
  END d[83]
  PIN d[84]
    DIRECTION INPUT ;
    USE SIGNAL ;
    PORT
      LAYER M4 ;
        RECT  0 28.368 0.084 28.392 ;
    END
  END d[84]
  PIN d[85]
    DIRECTION INPUT ;
    USE SIGNAL ;
    PORT
      LAYER M4 ;
        RECT  0 28.464 0.084 28.488 ;
    END
  END d[85]
  PIN d[86]
    DIRECTION INPUT ;
    USE SIGNAL ;
    PORT
      LAYER M4 ;
        RECT  0 28.56 0.084 28.584 ;
    END
  END d[86]
  PIN d[87]
    DIRECTION INPUT ;
    USE SIGNAL ;
    PORT
      LAYER M4 ;
        RECT  0 28.656 0.084 28.68 ;
    END
  END d[87]
  PIN d[88]
    DIRECTION INPUT ;
    USE SIGNAL ;
    PORT
      LAYER M4 ;
        RECT  0 28.752 0.084 28.776 ;
    END
  END d[88]
  PIN d[89]
    DIRECTION INPUT ;
    USE SIGNAL ;
    PORT
      LAYER M4 ;
        RECT  0 28.848 0.084 28.872 ;
    END
  END d[89]
  PIN d[8]
    DIRECTION INPUT ;
    USE SIGNAL ;
    PORT
      LAYER M4 ;
        RECT  0 33.36 0.084 33.384 ;
    END
  END d[8]
  PIN d[90]
    DIRECTION INPUT ;
    USE SIGNAL ;
    PORT
      LAYER M4 ;
        RECT  0 28.944 0.084 28.968 ;
    END
  END d[90]
  PIN d[91]
    DIRECTION INPUT ;
    USE SIGNAL ;
    PORT
      LAYER M4 ;
        RECT  0 29.04 0.084 29.064 ;
    END
  END d[91]
  PIN d[92]
    DIRECTION INPUT ;
    USE SIGNAL ;
    PORT
      LAYER M4 ;
        RECT  0 29.136 0.084 29.16 ;
    END
  END d[92]
  PIN d[93]
    DIRECTION INPUT ;
    USE SIGNAL ;
    PORT
      LAYER M4 ;
        RECT  0 29.232 0.084 29.256 ;
    END
  END d[93]
  PIN d[94]
    DIRECTION INPUT ;
    USE SIGNAL ;
    PORT
      LAYER M4 ;
        RECT  0 29.328 0.084 29.352 ;
    END
  END d[94]
  PIN d[95]
    DIRECTION INPUT ;
    USE SIGNAL ;
    PORT
      LAYER M4 ;
        RECT  0 29.424 0.084 29.448 ;
    END
  END d[95]
  PIN d[96]
    DIRECTION INPUT ;
    USE SIGNAL ;
    PORT
      LAYER M4 ;
        RECT  0 38.736 0.084 38.76 ;
    END
  END d[96]
  PIN d[97]
    DIRECTION INPUT ;
    USE SIGNAL ;
    PORT
      LAYER M4 ;
        RECT  0 38.832 0.084 38.856 ;
    END
  END d[97]
  PIN d[98]
    DIRECTION INPUT ;
    USE SIGNAL ;
    PORT
      LAYER M4 ;
        RECT  0 38.928 0.084 38.952 ;
    END
  END d[98]
  PIN d[99]
    DIRECTION INPUT ;
    USE SIGNAL ;
    PORT
      LAYER M4 ;
        RECT  0 39.024 0.084 39.048 ;
    END
  END d[99]
  PIN d[9]
    DIRECTION INPUT ;
    USE SIGNAL ;
    PORT
      LAYER M4 ;
        RECT  0 33.456 0.084 33.48 ;
    END
  END d[9]
  PIN q[0]
    DIRECTION OUTPUT ;
    USE SIGNAL ;
    PORT
      LAYER M4 ;
        RECT  17.196 29.136 17.28 29.16 ;
    END
  END q[0]
  PIN q[100]
    DIRECTION OUTPUT ;
    USE SIGNAL ;
    PORT
      LAYER M4 ;
        RECT  17.196 23.376 17.28 23.4 ;
    END
  END q[100]
  PIN q[101]
    DIRECTION OUTPUT ;
    USE SIGNAL ;
    PORT
      LAYER M4 ;
        RECT  17.196 23.472 17.28 23.496 ;
    END
  END q[101]
  PIN q[102]
    DIRECTION OUTPUT ;
    USE SIGNAL ;
    PORT
      LAYER M4 ;
        RECT  17.196 23.568 17.28 23.592 ;
    END
  END q[102]
  PIN q[103]
    DIRECTION OUTPUT ;
    USE SIGNAL ;
    PORT
      LAYER M4 ;
        RECT  17.196 23.664 17.28 23.688 ;
    END
  END q[103]
  PIN q[104]
    DIRECTION OUTPUT ;
    USE SIGNAL ;
    PORT
      LAYER M4 ;
        RECT  17.196 23.76 17.28 23.784 ;
    END
  END q[104]
  PIN q[105]
    DIRECTION OUTPUT ;
    USE SIGNAL ;
    PORT
      LAYER M4 ;
        RECT  17.196 23.856 17.28 23.88 ;
    END
  END q[105]
  PIN q[106]
    DIRECTION OUTPUT ;
    USE SIGNAL ;
    PORT
      LAYER M4 ;
        RECT  17.196 23.952 17.28 23.976 ;
    END
  END q[106]
  PIN q[107]
    DIRECTION OUTPUT ;
    USE SIGNAL ;
    PORT
      LAYER M4 ;
        RECT  17.196 24.048 17.28 24.072 ;
    END
  END q[107]
  PIN q[108]
    DIRECTION OUTPUT ;
    USE SIGNAL ;
    PORT
      LAYER M4 ;
        RECT  17.196 24.144 17.28 24.168 ;
    END
  END q[108]
  PIN q[109]
    DIRECTION OUTPUT ;
    USE SIGNAL ;
    PORT
      LAYER M4 ;
        RECT  17.196 24.24 17.28 24.264 ;
    END
  END q[109]
  PIN q[10]
    DIRECTION OUTPUT ;
    USE SIGNAL ;
    PORT
      LAYER M4 ;
        RECT  17.196 30.096 17.28 30.12 ;
    END
  END q[10]
  PIN q[110]
    DIRECTION OUTPUT ;
    USE SIGNAL ;
    PORT
      LAYER M4 ;
        RECT  17.196 24.336 17.28 24.36 ;
    END
  END q[110]
  PIN q[111]
    DIRECTION OUTPUT ;
    USE SIGNAL ;
    PORT
      LAYER M4 ;
        RECT  17.196 24.432 17.28 24.456 ;
    END
  END q[111]
  PIN q[112]
    DIRECTION OUTPUT ;
    USE SIGNAL ;
    PORT
      LAYER M4 ;
        RECT  17.196 24.528 17.28 24.552 ;
    END
  END q[112]
  PIN q[113]
    DIRECTION OUTPUT ;
    USE SIGNAL ;
    PORT
      LAYER M4 ;
        RECT  17.196 24.624 17.28 24.648 ;
    END
  END q[113]
  PIN q[114]
    DIRECTION OUTPUT ;
    USE SIGNAL ;
    PORT
      LAYER M4 ;
        RECT  17.196 24.72 17.28 24.744 ;
    END
  END q[114]
  PIN q[115]
    DIRECTION OUTPUT ;
    USE SIGNAL ;
    PORT
      LAYER M4 ;
        RECT  17.196 24.816 17.28 24.84 ;
    END
  END q[115]
  PIN q[116]
    DIRECTION OUTPUT ;
    USE SIGNAL ;
    PORT
      LAYER M4 ;
        RECT  17.196 24.912 17.28 24.936 ;
    END
  END q[116]
  PIN q[117]
    DIRECTION OUTPUT ;
    USE SIGNAL ;
    PORT
      LAYER M4 ;
        RECT  17.196 25.008 17.28 25.032 ;
    END
  END q[117]
  PIN q[118]
    DIRECTION OUTPUT ;
    USE SIGNAL ;
    PORT
      LAYER M4 ;
        RECT  17.196 25.104 17.28 25.128 ;
    END
  END q[118]
  PIN q[119]
    DIRECTION OUTPUT ;
    USE SIGNAL ;
    PORT
      LAYER M4 ;
        RECT  17.196 25.2 17.28 25.224 ;
    END
  END q[119]
  PIN q[11]
    DIRECTION OUTPUT ;
    USE SIGNAL ;
    PORT
      LAYER M4 ;
        RECT  17.196 30.192 17.28 30.216 ;
    END
  END q[11]
  PIN q[120]
    DIRECTION OUTPUT ;
    USE SIGNAL ;
    PORT
      LAYER M4 ;
        RECT  17.196 25.296 17.28 25.32 ;
    END
  END q[120]
  PIN q[121]
    DIRECTION OUTPUT ;
    USE SIGNAL ;
    PORT
      LAYER M4 ;
        RECT  17.196 25.392 17.28 25.416 ;
    END
  END q[121]
  PIN q[122]
    DIRECTION OUTPUT ;
    USE SIGNAL ;
    PORT
      LAYER M4 ;
        RECT  17.196 25.488 17.28 25.512 ;
    END
  END q[122]
  PIN q[123]
    DIRECTION OUTPUT ;
    USE SIGNAL ;
    PORT
      LAYER M4 ;
        RECT  17.196 25.584 17.28 25.608 ;
    END
  END q[123]
  PIN q[124]
    DIRECTION OUTPUT ;
    USE SIGNAL ;
    PORT
      LAYER M4 ;
        RECT  17.196 25.68 17.28 25.704 ;
    END
  END q[124]
  PIN q[125]
    DIRECTION OUTPUT ;
    USE SIGNAL ;
    PORT
      LAYER M4 ;
        RECT  17.196 25.776 17.28 25.8 ;
    END
  END q[125]
  PIN q[126]
    DIRECTION OUTPUT ;
    USE SIGNAL ;
    PORT
      LAYER M4 ;
        RECT  17.196 25.872 17.28 25.896 ;
    END
  END q[126]
  PIN q[127]
    DIRECTION OUTPUT ;
    USE SIGNAL ;
    PORT
      LAYER M4 ;
        RECT  17.196 25.968 17.28 25.992 ;
    END
  END q[127]
  PIN q[128]
    DIRECTION OUTPUT ;
    USE SIGNAL ;
    PORT
      LAYER M4 ;
        RECT  17.196 26.064 17.28 26.088 ;
    END
  END q[128]
  PIN q[129]
    DIRECTION OUTPUT ;
    USE SIGNAL ;
    PORT
      LAYER M4 ;
        RECT  17.196 26.16 17.28 26.184 ;
    END
  END q[129]
  PIN q[12]
    DIRECTION OUTPUT ;
    USE SIGNAL ;
    PORT
      LAYER M4 ;
        RECT  17.196 30.288 17.28 30.312 ;
    END
  END q[12]
  PIN q[130]
    DIRECTION OUTPUT ;
    USE SIGNAL ;
    PORT
      LAYER M4 ;
        RECT  17.196 26.256 17.28 26.28 ;
    END
  END q[130]
  PIN q[131]
    DIRECTION OUTPUT ;
    USE SIGNAL ;
    PORT
      LAYER M4 ;
        RECT  17.196 26.352 17.28 26.376 ;
    END
  END q[131]
  PIN q[132]
    DIRECTION OUTPUT ;
    USE SIGNAL ;
    PORT
      LAYER M4 ;
        RECT  17.196 26.448 17.28 26.472 ;
    END
  END q[132]
  PIN q[133]
    DIRECTION OUTPUT ;
    USE SIGNAL ;
    PORT
      LAYER M4 ;
        RECT  17.196 26.544 17.28 26.568 ;
    END
  END q[133]
  PIN q[134]
    DIRECTION OUTPUT ;
    USE SIGNAL ;
    PORT
      LAYER M4 ;
        RECT  17.196 26.64 17.28 26.664 ;
    END
  END q[134]
  PIN q[135]
    DIRECTION OUTPUT ;
    USE SIGNAL ;
    PORT
      LAYER M4 ;
        RECT  17.196 26.736 17.28 26.76 ;
    END
  END q[135]
  PIN q[136]
    DIRECTION OUTPUT ;
    USE SIGNAL ;
    PORT
      LAYER M4 ;
        RECT  17.196 26.832 17.28 26.856 ;
    END
  END q[136]
  PIN q[137]
    DIRECTION OUTPUT ;
    USE SIGNAL ;
    PORT
      LAYER M4 ;
        RECT  17.196 26.928 17.28 26.952 ;
    END
  END q[137]
  PIN q[138]
    DIRECTION OUTPUT ;
    USE SIGNAL ;
    PORT
      LAYER M4 ;
        RECT  17.196 27.024 17.28 27.048 ;
    END
  END q[138]
  PIN q[139]
    DIRECTION OUTPUT ;
    USE SIGNAL ;
    PORT
      LAYER M4 ;
        RECT  17.196 27.12 17.28 27.144 ;
    END
  END q[139]
  PIN q[13]
    DIRECTION OUTPUT ;
    USE SIGNAL ;
    PORT
      LAYER M4 ;
        RECT  17.196 30.384 17.28 30.408 ;
    END
  END q[13]
  PIN q[140]
    DIRECTION OUTPUT ;
    USE SIGNAL ;
    PORT
      LAYER M4 ;
        RECT  17.196 27.216 17.28 27.24 ;
    END
  END q[140]
  PIN q[141]
    DIRECTION OUTPUT ;
    USE SIGNAL ;
    PORT
      LAYER M4 ;
        RECT  17.196 27.312 17.28 27.336 ;
    END
  END q[141]
  PIN q[142]
    DIRECTION OUTPUT ;
    USE SIGNAL ;
    PORT
      LAYER M4 ;
        RECT  17.196 27.408 17.28 27.432 ;
    END
  END q[142]
  PIN q[143]
    DIRECTION OUTPUT ;
    USE SIGNAL ;
    PORT
      LAYER M4 ;
        RECT  17.196 27.504 17.28 27.528 ;
    END
  END q[143]
  PIN q[144]
    DIRECTION OUTPUT ;
    USE SIGNAL ;
    PORT
      LAYER M4 ;
        RECT  17.196 27.6 17.28 27.624 ;
    END
  END q[144]
  PIN q[145]
    DIRECTION OUTPUT ;
    USE SIGNAL ;
    PORT
      LAYER M4 ;
        RECT  17.196 27.696 17.28 27.72 ;
    END
  END q[145]
  PIN q[146]
    DIRECTION OUTPUT ;
    USE SIGNAL ;
    PORT
      LAYER M4 ;
        RECT  17.196 27.792 17.28 27.816 ;
    END
  END q[146]
  PIN q[147]
    DIRECTION OUTPUT ;
    USE SIGNAL ;
    PORT
      LAYER M4 ;
        RECT  17.196 27.888 17.28 27.912 ;
    END
  END q[147]
  PIN q[148]
    DIRECTION OUTPUT ;
    USE SIGNAL ;
    PORT
      LAYER M4 ;
        RECT  17.196 27.984 17.28 28.008 ;
    END
  END q[148]
  PIN q[149]
    DIRECTION OUTPUT ;
    USE SIGNAL ;
    PORT
      LAYER M4 ;
        RECT  17.196 28.08 17.28 28.104 ;
    END
  END q[149]
  PIN q[14]
    DIRECTION OUTPUT ;
    USE SIGNAL ;
    PORT
      LAYER M4 ;
        RECT  17.196 30.48 17.28 30.504 ;
    END
  END q[14]
  PIN q[150]
    DIRECTION OUTPUT ;
    USE SIGNAL ;
    PORT
      LAYER M4 ;
        RECT  17.196 28.176 17.28 28.2 ;
    END
  END q[150]
  PIN q[151]
    DIRECTION OUTPUT ;
    USE SIGNAL ;
    PORT
      LAYER M4 ;
        RECT  17.196 28.272 17.28 28.296 ;
    END
  END q[151]
  PIN q[152]
    DIRECTION OUTPUT ;
    USE SIGNAL ;
    PORT
      LAYER M4 ;
        RECT  17.196 28.368 17.28 28.392 ;
    END
  END q[152]
  PIN q[153]
    DIRECTION OUTPUT ;
    USE SIGNAL ;
    PORT
      LAYER M4 ;
        RECT  17.196 28.464 17.28 28.488 ;
    END
  END q[153]
  PIN q[154]
    DIRECTION OUTPUT ;
    USE SIGNAL ;
    PORT
      LAYER M4 ;
        RECT  17.196 28.56 17.28 28.584 ;
    END
  END q[154]
  PIN q[155]
    DIRECTION OUTPUT ;
    USE SIGNAL ;
    PORT
      LAYER M4 ;
        RECT  17.196 28.656 17.28 28.68 ;
    END
  END q[155]
  PIN q[156]
    DIRECTION OUTPUT ;
    USE SIGNAL ;
    PORT
      LAYER M4 ;
        RECT  17.196 28.752 17.28 28.776 ;
    END
  END q[156]
  PIN q[157]
    DIRECTION OUTPUT ;
    USE SIGNAL ;
    PORT
      LAYER M4 ;
        RECT  17.196 28.848 17.28 28.872 ;
    END
  END q[157]
  PIN q[158]
    DIRECTION OUTPUT ;
    USE SIGNAL ;
    PORT
      LAYER M4 ;
        RECT  17.196 28.944 17.28 28.968 ;
    END
  END q[158]
  PIN q[159]
    DIRECTION OUTPUT ;
    USE SIGNAL ;
    PORT
      LAYER M4 ;
        RECT  17.196 29.04 17.28 29.064 ;
    END
  END q[159]
  PIN q[15]
    DIRECTION OUTPUT ;
    USE SIGNAL ;
    PORT
      LAYER M4 ;
        RECT  17.196 30.576 17.28 30.6 ;
    END
  END q[15]
  PIN q[160]
    DIRECTION OUTPUT ;
    USE SIGNAL ;
    PORT
      LAYER M4 ;
        RECT  17.196 35.28 17.28 35.304 ;
    END
  END q[160]
  PIN q[161]
    DIRECTION OUTPUT ;
    USE SIGNAL ;
    PORT
      LAYER M4 ;
        RECT  17.196 35.376 17.28 35.4 ;
    END
  END q[161]
  PIN q[162]
    DIRECTION OUTPUT ;
    USE SIGNAL ;
    PORT
      LAYER M4 ;
        RECT  17.196 35.472 17.28 35.496 ;
    END
  END q[162]
  PIN q[163]
    DIRECTION OUTPUT ;
    USE SIGNAL ;
    PORT
      LAYER M4 ;
        RECT  17.196 35.568 17.28 35.592 ;
    END
  END q[163]
  PIN q[164]
    DIRECTION OUTPUT ;
    USE SIGNAL ;
    PORT
      LAYER M4 ;
        RECT  17.196 35.664 17.28 35.688 ;
    END
  END q[164]
  PIN q[165]
    DIRECTION OUTPUT ;
    USE SIGNAL ;
    PORT
      LAYER M4 ;
        RECT  17.196 35.76 17.28 35.784 ;
    END
  END q[165]
  PIN q[166]
    DIRECTION OUTPUT ;
    USE SIGNAL ;
    PORT
      LAYER M4 ;
        RECT  17.196 35.856 17.28 35.88 ;
    END
  END q[166]
  PIN q[167]
    DIRECTION OUTPUT ;
    USE SIGNAL ;
    PORT
      LAYER M4 ;
        RECT  17.196 35.952 17.28 35.976 ;
    END
  END q[167]
  PIN q[168]
    DIRECTION OUTPUT ;
    USE SIGNAL ;
    PORT
      LAYER M4 ;
        RECT  17.196 36.048 17.28 36.072 ;
    END
  END q[168]
  PIN q[169]
    DIRECTION OUTPUT ;
    USE SIGNAL ;
    PORT
      LAYER M4 ;
        RECT  17.196 36.144 17.28 36.168 ;
    END
  END q[169]
  PIN q[16]
    DIRECTION OUTPUT ;
    USE SIGNAL ;
    PORT
      LAYER M4 ;
        RECT  17.196 30.672 17.28 30.696 ;
    END
  END q[16]
  PIN q[170]
    DIRECTION OUTPUT ;
    USE SIGNAL ;
    PORT
      LAYER M4 ;
        RECT  17.196 36.24 17.28 36.264 ;
    END
  END q[170]
  PIN q[171]
    DIRECTION OUTPUT ;
    USE SIGNAL ;
    PORT
      LAYER M4 ;
        RECT  17.196 36.336 17.28 36.36 ;
    END
  END q[171]
  PIN q[172]
    DIRECTION OUTPUT ;
    USE SIGNAL ;
    PORT
      LAYER M4 ;
        RECT  17.196 36.432 17.28 36.456 ;
    END
  END q[172]
  PIN q[173]
    DIRECTION OUTPUT ;
    USE SIGNAL ;
    PORT
      LAYER M4 ;
        RECT  17.196 36.528 17.28 36.552 ;
    END
  END q[173]
  PIN q[174]
    DIRECTION OUTPUT ;
    USE SIGNAL ;
    PORT
      LAYER M4 ;
        RECT  17.196 36.624 17.28 36.648 ;
    END
  END q[174]
  PIN q[175]
    DIRECTION OUTPUT ;
    USE SIGNAL ;
    PORT
      LAYER M4 ;
        RECT  17.196 36.72 17.28 36.744 ;
    END
  END q[175]
  PIN q[176]
    DIRECTION OUTPUT ;
    USE SIGNAL ;
    PORT
      LAYER M4 ;
        RECT  17.196 36.816 17.28 36.84 ;
    END
  END q[176]
  PIN q[177]
    DIRECTION OUTPUT ;
    USE SIGNAL ;
    PORT
      LAYER M4 ;
        RECT  17.196 36.912 17.28 36.936 ;
    END
  END q[177]
  PIN q[178]
    DIRECTION OUTPUT ;
    USE SIGNAL ;
    PORT
      LAYER M4 ;
        RECT  17.196 37.008 17.28 37.032 ;
    END
  END q[178]
  PIN q[179]
    DIRECTION OUTPUT ;
    USE SIGNAL ;
    PORT
      LAYER M4 ;
        RECT  17.196 37.104 17.28 37.128 ;
    END
  END q[179]
  PIN q[17]
    DIRECTION OUTPUT ;
    USE SIGNAL ;
    PORT
      LAYER M4 ;
        RECT  17.196 30.768 17.28 30.792 ;
    END
  END q[17]
  PIN q[180]
    DIRECTION OUTPUT ;
    USE SIGNAL ;
    PORT
      LAYER M4 ;
        RECT  17.196 37.2 17.28 37.224 ;
    END
  END q[180]
  PIN q[181]
    DIRECTION OUTPUT ;
    USE SIGNAL ;
    PORT
      LAYER M4 ;
        RECT  17.196 37.296 17.28 37.32 ;
    END
  END q[181]
  PIN q[182]
    DIRECTION OUTPUT ;
    USE SIGNAL ;
    PORT
      LAYER M4 ;
        RECT  17.196 37.392 17.28 37.416 ;
    END
  END q[182]
  PIN q[183]
    DIRECTION OUTPUT ;
    USE SIGNAL ;
    PORT
      LAYER M4 ;
        RECT  17.196 37.488 17.28 37.512 ;
    END
  END q[183]
  PIN q[184]
    DIRECTION OUTPUT ;
    USE SIGNAL ;
    PORT
      LAYER M4 ;
        RECT  17.196 37.584 17.28 37.608 ;
    END
  END q[184]
  PIN q[185]
    DIRECTION OUTPUT ;
    USE SIGNAL ;
    PORT
      LAYER M4 ;
        RECT  17.196 37.68 17.28 37.704 ;
    END
  END q[185]
  PIN q[186]
    DIRECTION OUTPUT ;
    USE SIGNAL ;
    PORT
      LAYER M4 ;
        RECT  17.196 37.776 17.28 37.8 ;
    END
  END q[186]
  PIN q[187]
    DIRECTION OUTPUT ;
    USE SIGNAL ;
    PORT
      LAYER M4 ;
        RECT  17.196 37.872 17.28 37.896 ;
    END
  END q[187]
  PIN q[188]
    DIRECTION OUTPUT ;
    USE SIGNAL ;
    PORT
      LAYER M4 ;
        RECT  17.196 37.968 17.28 37.992 ;
    END
  END q[188]
  PIN q[189]
    DIRECTION OUTPUT ;
    USE SIGNAL ;
    PORT
      LAYER M4 ;
        RECT  17.196 38.064 17.28 38.088 ;
    END
  END q[189]
  PIN q[18]
    DIRECTION OUTPUT ;
    USE SIGNAL ;
    PORT
      LAYER M4 ;
        RECT  17.196 30.864 17.28 30.888 ;
    END
  END q[18]
  PIN q[190]
    DIRECTION OUTPUT ;
    USE SIGNAL ;
    PORT
      LAYER M4 ;
        RECT  17.196 38.16 17.28 38.184 ;
    END
  END q[190]
  PIN q[191]
    DIRECTION OUTPUT ;
    USE SIGNAL ;
    PORT
      LAYER M4 ;
        RECT  17.196 38.256 17.28 38.28 ;
    END
  END q[191]
  PIN q[192]
    DIRECTION OUTPUT ;
    USE SIGNAL ;
    PORT
      LAYER M4 ;
        RECT  17.196 42.192 17.28 42.216 ;
    END
  END q[192]
  PIN q[193]
    DIRECTION OUTPUT ;
    USE SIGNAL ;
    PORT
      LAYER M4 ;
        RECT  17.196 42.288 17.28 42.312 ;
    END
  END q[193]
  PIN q[194]
    DIRECTION OUTPUT ;
    USE SIGNAL ;
    PORT
      LAYER M4 ;
        RECT  17.196 42.384 17.28 42.408 ;
    END
  END q[194]
  PIN q[195]
    DIRECTION OUTPUT ;
    USE SIGNAL ;
    PORT
      LAYER M4 ;
        RECT  17.196 42.48 17.28 42.504 ;
    END
  END q[195]
  PIN q[196]
    DIRECTION OUTPUT ;
    USE SIGNAL ;
    PORT
      LAYER M4 ;
        RECT  17.196 42.576 17.28 42.6 ;
    END
  END q[196]
  PIN q[197]
    DIRECTION OUTPUT ;
    USE SIGNAL ;
    PORT
      LAYER M4 ;
        RECT  17.196 42.672 17.28 42.696 ;
    END
  END q[197]
  PIN q[198]
    DIRECTION OUTPUT ;
    USE SIGNAL ;
    PORT
      LAYER M4 ;
        RECT  17.196 42.768 17.28 42.792 ;
    END
  END q[198]
  PIN q[199]
    DIRECTION OUTPUT ;
    USE SIGNAL ;
    PORT
      LAYER M4 ;
        RECT  17.196 42.864 17.28 42.888 ;
    END
  END q[199]
  PIN q[19]
    DIRECTION OUTPUT ;
    USE SIGNAL ;
    PORT
      LAYER M4 ;
        RECT  17.196 30.96 17.28 30.984 ;
    END
  END q[19]
  PIN q[1]
    DIRECTION OUTPUT ;
    USE SIGNAL ;
    PORT
      LAYER M4 ;
        RECT  17.196 29.232 17.28 29.256 ;
    END
  END q[1]
  PIN q[200]
    DIRECTION OUTPUT ;
    USE SIGNAL ;
    PORT
      LAYER M4 ;
        RECT  17.196 42.96 17.28 42.984 ;
    END
  END q[200]
  PIN q[201]
    DIRECTION OUTPUT ;
    USE SIGNAL ;
    PORT
      LAYER M4 ;
        RECT  17.196 43.056 17.28 43.08 ;
    END
  END q[201]
  PIN q[202]
    DIRECTION OUTPUT ;
    USE SIGNAL ;
    PORT
      LAYER M4 ;
        RECT  17.196 43.152 17.28 43.176 ;
    END
  END q[202]
  PIN q[203]
    DIRECTION OUTPUT ;
    USE SIGNAL ;
    PORT
      LAYER M4 ;
        RECT  17.196 43.248 17.28 43.272 ;
    END
  END q[203]
  PIN q[204]
    DIRECTION OUTPUT ;
    USE SIGNAL ;
    PORT
      LAYER M4 ;
        RECT  17.196 43.344 17.28 43.368 ;
    END
  END q[204]
  PIN q[205]
    DIRECTION OUTPUT ;
    USE SIGNAL ;
    PORT
      LAYER M4 ;
        RECT  17.196 43.44 17.28 43.464 ;
    END
  END q[205]
  PIN q[206]
    DIRECTION OUTPUT ;
    USE SIGNAL ;
    PORT
      LAYER M4 ;
        RECT  17.196 43.536 17.28 43.56 ;
    END
  END q[206]
  PIN q[207]
    DIRECTION OUTPUT ;
    USE SIGNAL ;
    PORT
      LAYER M4 ;
        RECT  17.196 43.632 17.28 43.656 ;
    END
  END q[207]
  PIN q[208]
    DIRECTION OUTPUT ;
    USE SIGNAL ;
    PORT
      LAYER M4 ;
        RECT  17.196 43.728 17.28 43.752 ;
    END
  END q[208]
  PIN q[209]
    DIRECTION OUTPUT ;
    USE SIGNAL ;
    PORT
      LAYER M4 ;
        RECT  17.196 43.824 17.28 43.848 ;
    END
  END q[209]
  PIN q[20]
    DIRECTION OUTPUT ;
    USE SIGNAL ;
    PORT
      LAYER M4 ;
        RECT  17.196 31.056 17.28 31.08 ;
    END
  END q[20]
  PIN q[210]
    DIRECTION OUTPUT ;
    USE SIGNAL ;
    PORT
      LAYER M4 ;
        RECT  17.196 43.92 17.28 43.944 ;
    END
  END q[210]
  PIN q[211]
    DIRECTION OUTPUT ;
    USE SIGNAL ;
    PORT
      LAYER M4 ;
        RECT  17.196 44.016 17.28 44.04 ;
    END
  END q[211]
  PIN q[212]
    DIRECTION OUTPUT ;
    USE SIGNAL ;
    PORT
      LAYER M4 ;
        RECT  17.196 44.112 17.28 44.136 ;
    END
  END q[212]
  PIN q[213]
    DIRECTION OUTPUT ;
    USE SIGNAL ;
    PORT
      LAYER M4 ;
        RECT  17.196 44.208 17.28 44.232 ;
    END
  END q[213]
  PIN q[214]
    DIRECTION OUTPUT ;
    USE SIGNAL ;
    PORT
      LAYER M4 ;
        RECT  17.196 44.304 17.28 44.328 ;
    END
  END q[214]
  PIN q[215]
    DIRECTION OUTPUT ;
    USE SIGNAL ;
    PORT
      LAYER M4 ;
        RECT  17.196 44.4 17.28 44.424 ;
    END
  END q[215]
  PIN q[216]
    DIRECTION OUTPUT ;
    USE SIGNAL ;
    PORT
      LAYER M4 ;
        RECT  17.196 44.496 17.28 44.52 ;
    END
  END q[216]
  PIN q[217]
    DIRECTION OUTPUT ;
    USE SIGNAL ;
    PORT
      LAYER M4 ;
        RECT  17.196 44.592 17.28 44.616 ;
    END
  END q[217]
  PIN q[218]
    DIRECTION OUTPUT ;
    USE SIGNAL ;
    PORT
      LAYER M4 ;
        RECT  17.196 44.688 17.28 44.712 ;
    END
  END q[218]
  PIN q[219]
    DIRECTION OUTPUT ;
    USE SIGNAL ;
    PORT
      LAYER M4 ;
        RECT  17.196 44.784 17.28 44.808 ;
    END
  END q[219]
  PIN q[21]
    DIRECTION OUTPUT ;
    USE SIGNAL ;
    PORT
      LAYER M4 ;
        RECT  17.196 31.152 17.28 31.176 ;
    END
  END q[21]
  PIN q[220]
    DIRECTION OUTPUT ;
    USE SIGNAL ;
    PORT
      LAYER M4 ;
        RECT  17.196 44.88 17.28 44.904 ;
    END
  END q[220]
  PIN q[221]
    DIRECTION OUTPUT ;
    USE SIGNAL ;
    PORT
      LAYER M4 ;
        RECT  17.196 44.976 17.28 45 ;
    END
  END q[221]
  PIN q[222]
    DIRECTION OUTPUT ;
    USE SIGNAL ;
    PORT
      LAYER M4 ;
        RECT  17.196 45.072 17.28 45.096 ;
    END
  END q[222]
  PIN q[223]
    DIRECTION OUTPUT ;
    USE SIGNAL ;
    PORT
      LAYER M4 ;
        RECT  17.196 45.168 17.28 45.192 ;
    END
  END q[223]
  PIN q[224]
    DIRECTION OUTPUT ;
    USE SIGNAL ;
    PORT
      LAYER M4 ;
        RECT  17.196 48.336 17.28 48.36 ;
    END
  END q[224]
  PIN q[225]
    DIRECTION OUTPUT ;
    USE SIGNAL ;
    PORT
      LAYER M4 ;
        RECT  17.196 48.432 17.28 48.456 ;
    END
  END q[225]
  PIN q[226]
    DIRECTION OUTPUT ;
    USE SIGNAL ;
    PORT
      LAYER M4 ;
        RECT  17.196 48.528 17.28 48.552 ;
    END
  END q[226]
  PIN q[227]
    DIRECTION OUTPUT ;
    USE SIGNAL ;
    PORT
      LAYER M4 ;
        RECT  17.196 48.624 17.28 48.648 ;
    END
  END q[227]
  PIN q[228]
    DIRECTION OUTPUT ;
    USE SIGNAL ;
    PORT
      LAYER M4 ;
        RECT  17.196 48.72 17.28 48.744 ;
    END
  END q[228]
  PIN q[229]
    DIRECTION OUTPUT ;
    USE SIGNAL ;
    PORT
      LAYER M4 ;
        RECT  17.196 48.816 17.28 48.84 ;
    END
  END q[229]
  PIN q[22]
    DIRECTION OUTPUT ;
    USE SIGNAL ;
    PORT
      LAYER M4 ;
        RECT  17.196 31.248 17.28 31.272 ;
    END
  END q[22]
  PIN q[230]
    DIRECTION OUTPUT ;
    USE SIGNAL ;
    PORT
      LAYER M4 ;
        RECT  17.196 48.912 17.28 48.936 ;
    END
  END q[230]
  PIN q[231]
    DIRECTION OUTPUT ;
    USE SIGNAL ;
    PORT
      LAYER M4 ;
        RECT  17.196 49.008 17.28 49.032 ;
    END
  END q[231]
  PIN q[232]
    DIRECTION OUTPUT ;
    USE SIGNAL ;
    PORT
      LAYER M4 ;
        RECT  17.196 49.104 17.28 49.128 ;
    END
  END q[232]
  PIN q[233]
    DIRECTION OUTPUT ;
    USE SIGNAL ;
    PORT
      LAYER M4 ;
        RECT  17.196 49.2 17.28 49.224 ;
    END
  END q[233]
  PIN q[234]
    DIRECTION OUTPUT ;
    USE SIGNAL ;
    PORT
      LAYER M4 ;
        RECT  17.196 49.296 17.28 49.32 ;
    END
  END q[234]
  PIN q[235]
    DIRECTION OUTPUT ;
    USE SIGNAL ;
    PORT
      LAYER M4 ;
        RECT  17.196 49.392 17.28 49.416 ;
    END
  END q[235]
  PIN q[236]
    DIRECTION OUTPUT ;
    USE SIGNAL ;
    PORT
      LAYER M4 ;
        RECT  17.196 49.488 17.28 49.512 ;
    END
  END q[236]
  PIN q[237]
    DIRECTION OUTPUT ;
    USE SIGNAL ;
    PORT
      LAYER M4 ;
        RECT  17.196 49.584 17.28 49.608 ;
    END
  END q[237]
  PIN q[238]
    DIRECTION OUTPUT ;
    USE SIGNAL ;
    PORT
      LAYER M4 ;
        RECT  17.196 49.68 17.28 49.704 ;
    END
  END q[238]
  PIN q[239]
    DIRECTION OUTPUT ;
    USE SIGNAL ;
    PORT
      LAYER M4 ;
        RECT  17.196 49.776 17.28 49.8 ;
    END
  END q[239]
  PIN q[23]
    DIRECTION OUTPUT ;
    USE SIGNAL ;
    PORT
      LAYER M4 ;
        RECT  17.196 31.344 17.28 31.368 ;
    END
  END q[23]
  PIN q[240]
    DIRECTION OUTPUT ;
    USE SIGNAL ;
    PORT
      LAYER M4 ;
        RECT  17.196 49.872 17.28 49.896 ;
    END
  END q[240]
  PIN q[241]
    DIRECTION OUTPUT ;
    USE SIGNAL ;
    PORT
      LAYER M4 ;
        RECT  17.196 49.968 17.28 49.992 ;
    END
  END q[241]
  PIN q[242]
    DIRECTION OUTPUT ;
    USE SIGNAL ;
    PORT
      LAYER M4 ;
        RECT  17.196 50.064 17.28 50.088 ;
    END
  END q[242]
  PIN q[243]
    DIRECTION OUTPUT ;
    USE SIGNAL ;
    PORT
      LAYER M4 ;
        RECT  17.196 50.16 17.28 50.184 ;
    END
  END q[243]
  PIN q[244]
    DIRECTION OUTPUT ;
    USE SIGNAL ;
    PORT
      LAYER M4 ;
        RECT  17.196 50.256 17.28 50.28 ;
    END
  END q[244]
  PIN q[245]
    DIRECTION OUTPUT ;
    USE SIGNAL ;
    PORT
      LAYER M4 ;
        RECT  17.196 50.352 17.28 50.376 ;
    END
  END q[245]
  PIN q[246]
    DIRECTION OUTPUT ;
    USE SIGNAL ;
    PORT
      LAYER M4 ;
        RECT  17.196 50.448 17.28 50.472 ;
    END
  END q[246]
  PIN q[247]
    DIRECTION OUTPUT ;
    USE SIGNAL ;
    PORT
      LAYER M4 ;
        RECT  17.196 50.544 17.28 50.568 ;
    END
  END q[247]
  PIN q[248]
    DIRECTION OUTPUT ;
    USE SIGNAL ;
    PORT
      LAYER M4 ;
        RECT  17.196 50.64 17.28 50.664 ;
    END
  END q[248]
  PIN q[249]
    DIRECTION OUTPUT ;
    USE SIGNAL ;
    PORT
      LAYER M4 ;
        RECT  17.196 50.736 17.28 50.76 ;
    END
  END q[249]
  PIN q[24]
    DIRECTION OUTPUT ;
    USE SIGNAL ;
    PORT
      LAYER M4 ;
        RECT  17.196 31.44 17.28 31.464 ;
    END
  END q[24]
  PIN q[250]
    DIRECTION OUTPUT ;
    USE SIGNAL ;
    PORT
      LAYER M4 ;
        RECT  17.196 50.832 17.28 50.856 ;
    END
  END q[250]
  PIN q[251]
    DIRECTION OUTPUT ;
    USE SIGNAL ;
    PORT
      LAYER M4 ;
        RECT  17.196 50.928 17.28 50.952 ;
    END
  END q[251]
  PIN q[252]
    DIRECTION OUTPUT ;
    USE SIGNAL ;
    PORT
      LAYER M4 ;
        RECT  17.196 51.024 17.28 51.048 ;
    END
  END q[252]
  PIN q[253]
    DIRECTION OUTPUT ;
    USE SIGNAL ;
    PORT
      LAYER M4 ;
        RECT  17.196 51.12 17.28 51.144 ;
    END
  END q[253]
  PIN q[254]
    DIRECTION OUTPUT ;
    USE SIGNAL ;
    PORT
      LAYER M4 ;
        RECT  17.196 51.216 17.28 51.24 ;
    END
  END q[254]
  PIN q[255]
    DIRECTION OUTPUT ;
    USE SIGNAL ;
    PORT
      LAYER M4 ;
        RECT  17.196 51.312 17.28 51.336 ;
    END
  END q[255]
  PIN q[256]
    DIRECTION OUTPUT ;
    USE SIGNAL ;
    PORT
      LAYER M4 ;
        RECT  17.196 9.936 17.28 9.96 ;
    END
  END q[256]
  PIN q[257]
    DIRECTION OUTPUT ;
    USE SIGNAL ;
    PORT
      LAYER M4 ;
        RECT  17.196 10.032 17.28 10.056 ;
    END
  END q[257]
  PIN q[258]
    DIRECTION OUTPUT ;
    USE SIGNAL ;
    PORT
      LAYER M4 ;
        RECT  17.196 10.128 17.28 10.152 ;
    END
  END q[258]
  PIN q[259]
    DIRECTION OUTPUT ;
    USE SIGNAL ;
    PORT
      LAYER M4 ;
        RECT  17.196 10.224 17.28 10.248 ;
    END
  END q[259]
  PIN q[25]
    DIRECTION OUTPUT ;
    USE SIGNAL ;
    PORT
      LAYER M4 ;
        RECT  17.196 31.536 17.28 31.56 ;
    END
  END q[25]
  PIN q[260]
    DIRECTION OUTPUT ;
    USE SIGNAL ;
    PORT
      LAYER M4 ;
        RECT  17.196 10.32 17.28 10.344 ;
    END
  END q[260]
  PIN q[261]
    DIRECTION OUTPUT ;
    USE SIGNAL ;
    PORT
      LAYER M4 ;
        RECT  17.196 10.416 17.28 10.44 ;
    END
  END q[261]
  PIN q[262]
    DIRECTION OUTPUT ;
    USE SIGNAL ;
    PORT
      LAYER M4 ;
        RECT  17.196 10.512 17.28 10.536 ;
    END
  END q[262]
  PIN q[263]
    DIRECTION OUTPUT ;
    USE SIGNAL ;
    PORT
      LAYER M4 ;
        RECT  17.196 10.608 17.28 10.632 ;
    END
  END q[263]
  PIN q[264]
    DIRECTION OUTPUT ;
    USE SIGNAL ;
    PORT
      LAYER M4 ;
        RECT  17.196 10.704 17.28 10.728 ;
    END
  END q[264]
  PIN q[265]
    DIRECTION OUTPUT ;
    USE SIGNAL ;
    PORT
      LAYER M4 ;
        RECT  17.196 10.8 17.28 10.824 ;
    END
  END q[265]
  PIN q[266]
    DIRECTION OUTPUT ;
    USE SIGNAL ;
    PORT
      LAYER M4 ;
        RECT  17.196 10.896 17.28 10.92 ;
    END
  END q[266]
  PIN q[267]
    DIRECTION OUTPUT ;
    USE SIGNAL ;
    PORT
      LAYER M4 ;
        RECT  17.196 10.992 17.28 11.016 ;
    END
  END q[267]
  PIN q[268]
    DIRECTION OUTPUT ;
    USE SIGNAL ;
    PORT
      LAYER M4 ;
        RECT  17.196 11.088 17.28 11.112 ;
    END
  END q[268]
  PIN q[269]
    DIRECTION OUTPUT ;
    USE SIGNAL ;
    PORT
      LAYER M4 ;
        RECT  17.196 11.184 17.28 11.208 ;
    END
  END q[269]
  PIN q[26]
    DIRECTION OUTPUT ;
    USE SIGNAL ;
    PORT
      LAYER M4 ;
        RECT  17.196 31.632 17.28 31.656 ;
    END
  END q[26]
  PIN q[270]
    DIRECTION OUTPUT ;
    USE SIGNAL ;
    PORT
      LAYER M4 ;
        RECT  17.196 11.28 17.28 11.304 ;
    END
  END q[270]
  PIN q[271]
    DIRECTION OUTPUT ;
    USE SIGNAL ;
    PORT
      LAYER M4 ;
        RECT  17.196 11.376 17.28 11.4 ;
    END
  END q[271]
  PIN q[272]
    DIRECTION OUTPUT ;
    USE SIGNAL ;
    PORT
      LAYER M4 ;
        RECT  17.196 11.472 17.28 11.496 ;
    END
  END q[272]
  PIN q[273]
    DIRECTION OUTPUT ;
    USE SIGNAL ;
    PORT
      LAYER M4 ;
        RECT  17.196 11.568 17.28 11.592 ;
    END
  END q[273]
  PIN q[274]
    DIRECTION OUTPUT ;
    USE SIGNAL ;
    PORT
      LAYER M4 ;
        RECT  17.196 11.664 17.28 11.688 ;
    END
  END q[274]
  PIN q[275]
    DIRECTION OUTPUT ;
    USE SIGNAL ;
    PORT
      LAYER M4 ;
        RECT  17.196 11.76 17.28 11.784 ;
    END
  END q[275]
  PIN q[276]
    DIRECTION OUTPUT ;
    USE SIGNAL ;
    PORT
      LAYER M4 ;
        RECT  17.196 11.856 17.28 11.88 ;
    END
  END q[276]
  PIN q[277]
    DIRECTION OUTPUT ;
    USE SIGNAL ;
    PORT
      LAYER M4 ;
        RECT  17.196 11.952 17.28 11.976 ;
    END
  END q[277]
  PIN q[278]
    DIRECTION OUTPUT ;
    USE SIGNAL ;
    PORT
      LAYER M4 ;
        RECT  17.196 12.048 17.28 12.072 ;
    END
  END q[278]
  PIN q[279]
    DIRECTION OUTPUT ;
    USE SIGNAL ;
    PORT
      LAYER M4 ;
        RECT  17.196 12.144 17.28 12.168 ;
    END
  END q[279]
  PIN q[27]
    DIRECTION OUTPUT ;
    USE SIGNAL ;
    PORT
      LAYER M4 ;
        RECT  17.196 31.728 17.28 31.752 ;
    END
  END q[27]
  PIN q[280]
    DIRECTION OUTPUT ;
    USE SIGNAL ;
    PORT
      LAYER M4 ;
        RECT  17.196 12.24 17.28 12.264 ;
    END
  END q[280]
  PIN q[281]
    DIRECTION OUTPUT ;
    USE SIGNAL ;
    PORT
      LAYER M4 ;
        RECT  17.196 12.336 17.28 12.36 ;
    END
  END q[281]
  PIN q[282]
    DIRECTION OUTPUT ;
    USE SIGNAL ;
    PORT
      LAYER M4 ;
        RECT  17.196 12.432 17.28 12.456 ;
    END
  END q[282]
  PIN q[283]
    DIRECTION OUTPUT ;
    USE SIGNAL ;
    PORT
      LAYER M4 ;
        RECT  17.196 12.528 17.28 12.552 ;
    END
  END q[283]
  PIN q[284]
    DIRECTION OUTPUT ;
    USE SIGNAL ;
    PORT
      LAYER M4 ;
        RECT  17.196 12.624 17.28 12.648 ;
    END
  END q[284]
  PIN q[285]
    DIRECTION OUTPUT ;
    USE SIGNAL ;
    PORT
      LAYER M4 ;
        RECT  17.196 12.72 17.28 12.744 ;
    END
  END q[285]
  PIN q[286]
    DIRECTION OUTPUT ;
    USE SIGNAL ;
    PORT
      LAYER M4 ;
        RECT  17.196 12.816 17.28 12.84 ;
    END
  END q[286]
  PIN q[287]
    DIRECTION OUTPUT ;
    USE SIGNAL ;
    PORT
      LAYER M4 ;
        RECT  17.196 12.912 17.28 12.936 ;
    END
  END q[287]
  PIN q[288]
    DIRECTION OUTPUT ;
    USE SIGNAL ;
    PORT
      LAYER M4 ;
        RECT  17.196 13.008 17.28 13.032 ;
    END
  END q[288]
  PIN q[289]
    DIRECTION OUTPUT ;
    USE SIGNAL ;
    PORT
      LAYER M4 ;
        RECT  17.196 13.104 17.28 13.128 ;
    END
  END q[289]
  PIN q[28]
    DIRECTION OUTPUT ;
    USE SIGNAL ;
    PORT
      LAYER M4 ;
        RECT  17.196 31.824 17.28 31.848 ;
    END
  END q[28]
  PIN q[290]
    DIRECTION OUTPUT ;
    USE SIGNAL ;
    PORT
      LAYER M4 ;
        RECT  17.196 13.2 17.28 13.224 ;
    END
  END q[290]
  PIN q[291]
    DIRECTION OUTPUT ;
    USE SIGNAL ;
    PORT
      LAYER M4 ;
        RECT  17.196 13.296 17.28 13.32 ;
    END
  END q[291]
  PIN q[292]
    DIRECTION OUTPUT ;
    USE SIGNAL ;
    PORT
      LAYER M4 ;
        RECT  17.196 13.392 17.28 13.416 ;
    END
  END q[292]
  PIN q[293]
    DIRECTION OUTPUT ;
    USE SIGNAL ;
    PORT
      LAYER M4 ;
        RECT  17.196 13.488 17.28 13.512 ;
    END
  END q[293]
  PIN q[294]
    DIRECTION OUTPUT ;
    USE SIGNAL ;
    PORT
      LAYER M4 ;
        RECT  17.196 13.584 17.28 13.608 ;
    END
  END q[294]
  PIN q[295]
    DIRECTION OUTPUT ;
    USE SIGNAL ;
    PORT
      LAYER M4 ;
        RECT  17.196 13.68 17.28 13.704 ;
    END
  END q[295]
  PIN q[296]
    DIRECTION OUTPUT ;
    USE SIGNAL ;
    PORT
      LAYER M4 ;
        RECT  17.196 13.776 17.28 13.8 ;
    END
  END q[296]
  PIN q[297]
    DIRECTION OUTPUT ;
    USE SIGNAL ;
    PORT
      LAYER M4 ;
        RECT  17.196 13.872 17.28 13.896 ;
    END
  END q[297]
  PIN q[298]
    DIRECTION OUTPUT ;
    USE SIGNAL ;
    PORT
      LAYER M4 ;
        RECT  17.196 13.968 17.28 13.992 ;
    END
  END q[298]
  PIN q[299]
    DIRECTION OUTPUT ;
    USE SIGNAL ;
    PORT
      LAYER M4 ;
        RECT  17.196 14.064 17.28 14.088 ;
    END
  END q[299]
  PIN q[29]
    DIRECTION OUTPUT ;
    USE SIGNAL ;
    PORT
      LAYER M4 ;
        RECT  17.196 31.92 17.28 31.944 ;
    END
  END q[29]
  PIN q[2]
    DIRECTION OUTPUT ;
    USE SIGNAL ;
    PORT
      LAYER M4 ;
        RECT  17.196 29.328 17.28 29.352 ;
    END
  END q[2]
  PIN q[300]
    DIRECTION OUTPUT ;
    USE SIGNAL ;
    PORT
      LAYER M4 ;
        RECT  17.196 14.16 17.28 14.184 ;
    END
  END q[300]
  PIN q[301]
    DIRECTION OUTPUT ;
    USE SIGNAL ;
    PORT
      LAYER M4 ;
        RECT  17.196 14.256 17.28 14.28 ;
    END
  END q[301]
  PIN q[302]
    DIRECTION OUTPUT ;
    USE SIGNAL ;
    PORT
      LAYER M4 ;
        RECT  17.196 14.352 17.28 14.376 ;
    END
  END q[302]
  PIN q[303]
    DIRECTION OUTPUT ;
    USE SIGNAL ;
    PORT
      LAYER M4 ;
        RECT  17.196 14.448 17.28 14.472 ;
    END
  END q[303]
  PIN q[304]
    DIRECTION OUTPUT ;
    USE SIGNAL ;
    PORT
      LAYER M4 ;
        RECT  17.196 14.544 17.28 14.568 ;
    END
  END q[304]
  PIN q[305]
    DIRECTION OUTPUT ;
    USE SIGNAL ;
    PORT
      LAYER M4 ;
        RECT  17.196 14.64 17.28 14.664 ;
    END
  END q[305]
  PIN q[306]
    DIRECTION OUTPUT ;
    USE SIGNAL ;
    PORT
      LAYER M4 ;
        RECT  17.196 14.736 17.28 14.76 ;
    END
  END q[306]
  PIN q[307]
    DIRECTION OUTPUT ;
    USE SIGNAL ;
    PORT
      LAYER M4 ;
        RECT  17.196 14.832 17.28 14.856 ;
    END
  END q[307]
  PIN q[308]
    DIRECTION OUTPUT ;
    USE SIGNAL ;
    PORT
      LAYER M4 ;
        RECT  17.196 14.928 17.28 14.952 ;
    END
  END q[308]
  PIN q[309]
    DIRECTION OUTPUT ;
    USE SIGNAL ;
    PORT
      LAYER M4 ;
        RECT  17.196 15.024 17.28 15.048 ;
    END
  END q[309]
  PIN q[30]
    DIRECTION OUTPUT ;
    USE SIGNAL ;
    PORT
      LAYER M4 ;
        RECT  17.196 32.016 17.28 32.04 ;
    END
  END q[30]
  PIN q[310]
    DIRECTION OUTPUT ;
    USE SIGNAL ;
    PORT
      LAYER M4 ;
        RECT  17.196 15.12 17.28 15.144 ;
    END
  END q[310]
  PIN q[311]
    DIRECTION OUTPUT ;
    USE SIGNAL ;
    PORT
      LAYER M4 ;
        RECT  17.196 15.216 17.28 15.24 ;
    END
  END q[311]
  PIN q[312]
    DIRECTION OUTPUT ;
    USE SIGNAL ;
    PORT
      LAYER M4 ;
        RECT  17.196 15.312 17.28 15.336 ;
    END
  END q[312]
  PIN q[313]
    DIRECTION OUTPUT ;
    USE SIGNAL ;
    PORT
      LAYER M4 ;
        RECT  17.196 15.408 17.28 15.432 ;
    END
  END q[313]
  PIN q[314]
    DIRECTION OUTPUT ;
    USE SIGNAL ;
    PORT
      LAYER M4 ;
        RECT  17.196 15.504 17.28 15.528 ;
    END
  END q[314]
  PIN q[315]
    DIRECTION OUTPUT ;
    USE SIGNAL ;
    PORT
      LAYER M4 ;
        RECT  17.196 15.6 17.28 15.624 ;
    END
  END q[315]
  PIN q[316]
    DIRECTION OUTPUT ;
    USE SIGNAL ;
    PORT
      LAYER M4 ;
        RECT  17.196 15.696 17.28 15.72 ;
    END
  END q[316]
  PIN q[317]
    DIRECTION OUTPUT ;
    USE SIGNAL ;
    PORT
      LAYER M4 ;
        RECT  17.196 15.792 17.28 15.816 ;
    END
  END q[317]
  PIN q[318]
    DIRECTION OUTPUT ;
    USE SIGNAL ;
    PORT
      LAYER M4 ;
        RECT  17.196 15.888 17.28 15.912 ;
    END
  END q[318]
  PIN q[319]
    DIRECTION OUTPUT ;
    USE SIGNAL ;
    PORT
      LAYER M4 ;
        RECT  17.196 15.984 17.28 16.008 ;
    END
  END q[319]
  PIN q[31]
    DIRECTION OUTPUT ;
    USE SIGNAL ;
    PORT
      LAYER M4 ;
        RECT  17.196 32.112 17.28 32.136 ;
    END
  END q[31]
  PIN q[320]
    DIRECTION OUTPUT ;
    USE SIGNAL ;
    PORT
      LAYER M4 ;
        RECT  17.196 39.12 17.28 39.144 ;
    END
  END q[320]
  PIN q[321]
    DIRECTION OUTPUT ;
    USE SIGNAL ;
    PORT
      LAYER M4 ;
        RECT  17.196 39.216 17.28 39.24 ;
    END
  END q[321]
  PIN q[322]
    DIRECTION OUTPUT ;
    USE SIGNAL ;
    PORT
      LAYER M4 ;
        RECT  17.196 39.312 17.28 39.336 ;
    END
  END q[322]
  PIN q[323]
    DIRECTION OUTPUT ;
    USE SIGNAL ;
    PORT
      LAYER M4 ;
        RECT  17.196 39.408 17.28 39.432 ;
    END
  END q[323]
  PIN q[324]
    DIRECTION OUTPUT ;
    USE SIGNAL ;
    PORT
      LAYER M4 ;
        RECT  17.196 39.504 17.28 39.528 ;
    END
  END q[324]
  PIN q[325]
    DIRECTION OUTPUT ;
    USE SIGNAL ;
    PORT
      LAYER M4 ;
        RECT  17.196 39.6 17.28 39.624 ;
    END
  END q[325]
  PIN q[326]
    DIRECTION OUTPUT ;
    USE SIGNAL ;
    PORT
      LAYER M4 ;
        RECT  17.196 39.696 17.28 39.72 ;
    END
  END q[326]
  PIN q[327]
    DIRECTION OUTPUT ;
    USE SIGNAL ;
    PORT
      LAYER M4 ;
        RECT  17.196 39.792 17.28 39.816 ;
    END
  END q[327]
  PIN q[328]
    DIRECTION OUTPUT ;
    USE SIGNAL ;
    PORT
      LAYER M4 ;
        RECT  17.196 39.888 17.28 39.912 ;
    END
  END q[328]
  PIN q[329]
    DIRECTION OUTPUT ;
    USE SIGNAL ;
    PORT
      LAYER M4 ;
        RECT  17.196 39.984 17.28 40.008 ;
    END
  END q[329]
  PIN q[32]
    DIRECTION OUTPUT ;
    USE SIGNAL ;
    PORT
      LAYER M4 ;
        RECT  17.196 32.208 17.28 32.232 ;
    END
  END q[32]
  PIN q[330]
    DIRECTION OUTPUT ;
    USE SIGNAL ;
    PORT
      LAYER M4 ;
        RECT  17.196 40.08 17.28 40.104 ;
    END
  END q[330]
  PIN q[331]
    DIRECTION OUTPUT ;
    USE SIGNAL ;
    PORT
      LAYER M4 ;
        RECT  17.196 40.176 17.28 40.2 ;
    END
  END q[331]
  PIN q[332]
    DIRECTION OUTPUT ;
    USE SIGNAL ;
    PORT
      LAYER M4 ;
        RECT  17.196 40.272 17.28 40.296 ;
    END
  END q[332]
  PIN q[333]
    DIRECTION OUTPUT ;
    USE SIGNAL ;
    PORT
      LAYER M4 ;
        RECT  17.196 40.368 17.28 40.392 ;
    END
  END q[333]
  PIN q[334]
    DIRECTION OUTPUT ;
    USE SIGNAL ;
    PORT
      LAYER M4 ;
        RECT  17.196 40.464 17.28 40.488 ;
    END
  END q[334]
  PIN q[335]
    DIRECTION OUTPUT ;
    USE SIGNAL ;
    PORT
      LAYER M4 ;
        RECT  17.196 40.56 17.28 40.584 ;
    END
  END q[335]
  PIN q[336]
    DIRECTION OUTPUT ;
    USE SIGNAL ;
    PORT
      LAYER M4 ;
        RECT  17.196 40.656 17.28 40.68 ;
    END
  END q[336]
  PIN q[337]
    DIRECTION OUTPUT ;
    USE SIGNAL ;
    PORT
      LAYER M4 ;
        RECT  17.196 40.752 17.28 40.776 ;
    END
  END q[337]
  PIN q[338]
    DIRECTION OUTPUT ;
    USE SIGNAL ;
    PORT
      LAYER M4 ;
        RECT  17.196 40.848 17.28 40.872 ;
    END
  END q[338]
  PIN q[339]
    DIRECTION OUTPUT ;
    USE SIGNAL ;
    PORT
      LAYER M4 ;
        RECT  17.196 40.944 17.28 40.968 ;
    END
  END q[339]
  PIN q[33]
    DIRECTION OUTPUT ;
    USE SIGNAL ;
    PORT
      LAYER M4 ;
        RECT  17.196 32.304 17.28 32.328 ;
    END
  END q[33]
  PIN q[340]
    DIRECTION OUTPUT ;
    USE SIGNAL ;
    PORT
      LAYER M4 ;
        RECT  17.196 41.04 17.28 41.064 ;
    END
  END q[340]
  PIN q[341]
    DIRECTION OUTPUT ;
    USE SIGNAL ;
    PORT
      LAYER M4 ;
        RECT  17.196 41.136 17.28 41.16 ;
    END
  END q[341]
  PIN q[342]
    DIRECTION OUTPUT ;
    USE SIGNAL ;
    PORT
      LAYER M4 ;
        RECT  17.196 41.232 17.28 41.256 ;
    END
  END q[342]
  PIN q[343]
    DIRECTION OUTPUT ;
    USE SIGNAL ;
    PORT
      LAYER M4 ;
        RECT  17.196 41.328 17.28 41.352 ;
    END
  END q[343]
  PIN q[344]
    DIRECTION OUTPUT ;
    USE SIGNAL ;
    PORT
      LAYER M4 ;
        RECT  17.196 41.424 17.28 41.448 ;
    END
  END q[344]
  PIN q[345]
    DIRECTION OUTPUT ;
    USE SIGNAL ;
    PORT
      LAYER M4 ;
        RECT  17.196 41.52 17.28 41.544 ;
    END
  END q[345]
  PIN q[346]
    DIRECTION OUTPUT ;
    USE SIGNAL ;
    PORT
      LAYER M4 ;
        RECT  17.196 41.616 17.28 41.64 ;
    END
  END q[346]
  PIN q[347]
    DIRECTION OUTPUT ;
    USE SIGNAL ;
    PORT
      LAYER M4 ;
        RECT  17.196 41.712 17.28 41.736 ;
    END
  END q[347]
  PIN q[348]
    DIRECTION OUTPUT ;
    USE SIGNAL ;
    PORT
      LAYER M4 ;
        RECT  17.196 41.808 17.28 41.832 ;
    END
  END q[348]
  PIN q[349]
    DIRECTION OUTPUT ;
    USE SIGNAL ;
    PORT
      LAYER M4 ;
        RECT  17.196 41.904 17.28 41.928 ;
    END
  END q[349]
  PIN q[34]
    DIRECTION OUTPUT ;
    USE SIGNAL ;
    PORT
      LAYER M4 ;
        RECT  17.196 32.4 17.28 32.424 ;
    END
  END q[34]
  PIN q[350]
    DIRECTION OUTPUT ;
    USE SIGNAL ;
    PORT
      LAYER M4 ;
        RECT  17.196 42 17.28 42.024 ;
    END
  END q[350]
  PIN q[351]
    DIRECTION OUTPUT ;
    USE SIGNAL ;
    PORT
      LAYER M4 ;
        RECT  17.196 42.096 17.28 42.12 ;
    END
  END q[351]
  PIN q[352]
    DIRECTION OUTPUT ;
    USE SIGNAL ;
    PORT
      LAYER M4 ;
        RECT  17.196 45.264 17.28 45.288 ;
    END
  END q[352]
  PIN q[353]
    DIRECTION OUTPUT ;
    USE SIGNAL ;
    PORT
      LAYER M4 ;
        RECT  17.196 45.36 17.28 45.384 ;
    END
  END q[353]
  PIN q[354]
    DIRECTION OUTPUT ;
    USE SIGNAL ;
    PORT
      LAYER M4 ;
        RECT  17.196 45.456 17.28 45.48 ;
    END
  END q[354]
  PIN q[355]
    DIRECTION OUTPUT ;
    USE SIGNAL ;
    PORT
      LAYER M4 ;
        RECT  17.196 45.552 17.28 45.576 ;
    END
  END q[355]
  PIN q[356]
    DIRECTION OUTPUT ;
    USE SIGNAL ;
    PORT
      LAYER M4 ;
        RECT  17.196 45.648 17.28 45.672 ;
    END
  END q[356]
  PIN q[357]
    DIRECTION OUTPUT ;
    USE SIGNAL ;
    PORT
      LAYER M4 ;
        RECT  17.196 45.744 17.28 45.768 ;
    END
  END q[357]
  PIN q[358]
    DIRECTION OUTPUT ;
    USE SIGNAL ;
    PORT
      LAYER M4 ;
        RECT  17.196 45.84 17.28 45.864 ;
    END
  END q[358]
  PIN q[359]
    DIRECTION OUTPUT ;
    USE SIGNAL ;
    PORT
      LAYER M4 ;
        RECT  17.196 45.936 17.28 45.96 ;
    END
  END q[359]
  PIN q[35]
    DIRECTION OUTPUT ;
    USE SIGNAL ;
    PORT
      LAYER M4 ;
        RECT  17.196 32.496 17.28 32.52 ;
    END
  END q[35]
  PIN q[360]
    DIRECTION OUTPUT ;
    USE SIGNAL ;
    PORT
      LAYER M4 ;
        RECT  17.196 46.032 17.28 46.056 ;
    END
  END q[360]
  PIN q[361]
    DIRECTION OUTPUT ;
    USE SIGNAL ;
    PORT
      LAYER M4 ;
        RECT  17.196 46.128 17.28 46.152 ;
    END
  END q[361]
  PIN q[362]
    DIRECTION OUTPUT ;
    USE SIGNAL ;
    PORT
      LAYER M4 ;
        RECT  17.196 46.224 17.28 46.248 ;
    END
  END q[362]
  PIN q[363]
    DIRECTION OUTPUT ;
    USE SIGNAL ;
    PORT
      LAYER M4 ;
        RECT  17.196 46.32 17.28 46.344 ;
    END
  END q[363]
  PIN q[364]
    DIRECTION OUTPUT ;
    USE SIGNAL ;
    PORT
      LAYER M4 ;
        RECT  17.196 46.416 17.28 46.44 ;
    END
  END q[364]
  PIN q[365]
    DIRECTION OUTPUT ;
    USE SIGNAL ;
    PORT
      LAYER M4 ;
        RECT  17.196 46.512 17.28 46.536 ;
    END
  END q[365]
  PIN q[366]
    DIRECTION OUTPUT ;
    USE SIGNAL ;
    PORT
      LAYER M4 ;
        RECT  17.196 46.608 17.28 46.632 ;
    END
  END q[366]
  PIN q[367]
    DIRECTION OUTPUT ;
    USE SIGNAL ;
    PORT
      LAYER M4 ;
        RECT  17.196 46.704 17.28 46.728 ;
    END
  END q[367]
  PIN q[368]
    DIRECTION OUTPUT ;
    USE SIGNAL ;
    PORT
      LAYER M4 ;
        RECT  17.196 46.8 17.28 46.824 ;
    END
  END q[368]
  PIN q[369]
    DIRECTION OUTPUT ;
    USE SIGNAL ;
    PORT
      LAYER M4 ;
        RECT  17.196 46.896 17.28 46.92 ;
    END
  END q[369]
  PIN q[36]
    DIRECTION OUTPUT ;
    USE SIGNAL ;
    PORT
      LAYER M4 ;
        RECT  17.196 32.592 17.28 32.616 ;
    END
  END q[36]
  PIN q[370]
    DIRECTION OUTPUT ;
    USE SIGNAL ;
    PORT
      LAYER M4 ;
        RECT  17.196 46.992 17.28 47.016 ;
    END
  END q[370]
  PIN q[371]
    DIRECTION OUTPUT ;
    USE SIGNAL ;
    PORT
      LAYER M4 ;
        RECT  17.196 47.088 17.28 47.112 ;
    END
  END q[371]
  PIN q[372]
    DIRECTION OUTPUT ;
    USE SIGNAL ;
    PORT
      LAYER M4 ;
        RECT  17.196 47.184 17.28 47.208 ;
    END
  END q[372]
  PIN q[373]
    DIRECTION OUTPUT ;
    USE SIGNAL ;
    PORT
      LAYER M4 ;
        RECT  17.196 47.28 17.28 47.304 ;
    END
  END q[373]
  PIN q[374]
    DIRECTION OUTPUT ;
    USE SIGNAL ;
    PORT
      LAYER M4 ;
        RECT  17.196 47.376 17.28 47.4 ;
    END
  END q[374]
  PIN q[375]
    DIRECTION OUTPUT ;
    USE SIGNAL ;
    PORT
      LAYER M4 ;
        RECT  17.196 47.472 17.28 47.496 ;
    END
  END q[375]
  PIN q[376]
    DIRECTION OUTPUT ;
    USE SIGNAL ;
    PORT
      LAYER M4 ;
        RECT  17.196 47.568 17.28 47.592 ;
    END
  END q[376]
  PIN q[377]
    DIRECTION OUTPUT ;
    USE SIGNAL ;
    PORT
      LAYER M4 ;
        RECT  17.196 47.664 17.28 47.688 ;
    END
  END q[377]
  PIN q[378]
    DIRECTION OUTPUT ;
    USE SIGNAL ;
    PORT
      LAYER M4 ;
        RECT  17.196 47.76 17.28 47.784 ;
    END
  END q[378]
  PIN q[379]
    DIRECTION OUTPUT ;
    USE SIGNAL ;
    PORT
      LAYER M4 ;
        RECT  17.196 47.856 17.28 47.88 ;
    END
  END q[379]
  PIN q[37]
    DIRECTION OUTPUT ;
    USE SIGNAL ;
    PORT
      LAYER M4 ;
        RECT  17.196 32.688 17.28 32.712 ;
    END
  END q[37]
  PIN q[380]
    DIRECTION OUTPUT ;
    USE SIGNAL ;
    PORT
      LAYER M4 ;
        RECT  17.196 47.952 17.28 47.976 ;
    END
  END q[380]
  PIN q[381]
    DIRECTION OUTPUT ;
    USE SIGNAL ;
    PORT
      LAYER M4 ;
        RECT  17.196 48.048 17.28 48.072 ;
    END
  END q[381]
  PIN q[382]
    DIRECTION OUTPUT ;
    USE SIGNAL ;
    PORT
      LAYER M4 ;
        RECT  17.196 48.144 17.28 48.168 ;
    END
  END q[382]
  PIN q[383]
    DIRECTION OUTPUT ;
    USE SIGNAL ;
    PORT
      LAYER M4 ;
        RECT  17.196 48.24 17.28 48.264 ;
    END
  END q[383]
  PIN q[384]
    DIRECTION OUTPUT ;
    USE SIGNAL ;
    PORT
      LAYER M4 ;
        RECT  17.196 54.48 17.28 54.504 ;
    END
  END q[384]
  PIN q[385]
    DIRECTION OUTPUT ;
    USE SIGNAL ;
    PORT
      LAYER M4 ;
        RECT  17.196 54.576 17.28 54.6 ;
    END
  END q[385]
  PIN q[386]
    DIRECTION OUTPUT ;
    USE SIGNAL ;
    PORT
      LAYER M4 ;
        RECT  17.196 54.672 17.28 54.696 ;
    END
  END q[386]
  PIN q[387]
    DIRECTION OUTPUT ;
    USE SIGNAL ;
    PORT
      LAYER M4 ;
        RECT  17.196 54.768 17.28 54.792 ;
    END
  END q[387]
  PIN q[388]
    DIRECTION OUTPUT ;
    USE SIGNAL ;
    PORT
      LAYER M4 ;
        RECT  17.196 54.864 17.28 54.888 ;
    END
  END q[388]
  PIN q[389]
    DIRECTION OUTPUT ;
    USE SIGNAL ;
    PORT
      LAYER M4 ;
        RECT  17.196 54.96 17.28 54.984 ;
    END
  END q[389]
  PIN q[38]
    DIRECTION OUTPUT ;
    USE SIGNAL ;
    PORT
      LAYER M4 ;
        RECT  17.196 32.784 17.28 32.808 ;
    END
  END q[38]
  PIN q[390]
    DIRECTION OUTPUT ;
    USE SIGNAL ;
    PORT
      LAYER M4 ;
        RECT  17.196 55.056 17.28 55.08 ;
    END
  END q[390]
  PIN q[391]
    DIRECTION OUTPUT ;
    USE SIGNAL ;
    PORT
      LAYER M4 ;
        RECT  17.196 55.152 17.28 55.176 ;
    END
  END q[391]
  PIN q[392]
    DIRECTION OUTPUT ;
    USE SIGNAL ;
    PORT
      LAYER M4 ;
        RECT  17.196 55.248 17.28 55.272 ;
    END
  END q[392]
  PIN q[393]
    DIRECTION OUTPUT ;
    USE SIGNAL ;
    PORT
      LAYER M4 ;
        RECT  17.196 55.344 17.28 55.368 ;
    END
  END q[393]
  PIN q[394]
    DIRECTION OUTPUT ;
    USE SIGNAL ;
    PORT
      LAYER M4 ;
        RECT  17.196 55.44 17.28 55.464 ;
    END
  END q[394]
  PIN q[395]
    DIRECTION OUTPUT ;
    USE SIGNAL ;
    PORT
      LAYER M4 ;
        RECT  17.196 55.536 17.28 55.56 ;
    END
  END q[395]
  PIN q[396]
    DIRECTION OUTPUT ;
    USE SIGNAL ;
    PORT
      LAYER M4 ;
        RECT  17.196 55.632 17.28 55.656 ;
    END
  END q[396]
  PIN q[397]
    DIRECTION OUTPUT ;
    USE SIGNAL ;
    PORT
      LAYER M4 ;
        RECT  17.196 55.728 17.28 55.752 ;
    END
  END q[397]
  PIN q[398]
    DIRECTION OUTPUT ;
    USE SIGNAL ;
    PORT
      LAYER M4 ;
        RECT  17.196 55.824 17.28 55.848 ;
    END
  END q[398]
  PIN q[399]
    DIRECTION OUTPUT ;
    USE SIGNAL ;
    PORT
      LAYER M4 ;
        RECT  17.196 55.92 17.28 55.944 ;
    END
  END q[399]
  PIN q[39]
    DIRECTION OUTPUT ;
    USE SIGNAL ;
    PORT
      LAYER M4 ;
        RECT  17.196 32.88 17.28 32.904 ;
    END
  END q[39]
  PIN q[3]
    DIRECTION OUTPUT ;
    USE SIGNAL ;
    PORT
      LAYER M4 ;
        RECT  17.196 29.424 17.28 29.448 ;
    END
  END q[3]
  PIN q[400]
    DIRECTION OUTPUT ;
    USE SIGNAL ;
    PORT
      LAYER M4 ;
        RECT  17.196 56.016 17.28 56.04 ;
    END
  END q[400]
  PIN q[401]
    DIRECTION OUTPUT ;
    USE SIGNAL ;
    PORT
      LAYER M4 ;
        RECT  17.196 56.112 17.28 56.136 ;
    END
  END q[401]
  PIN q[402]
    DIRECTION OUTPUT ;
    USE SIGNAL ;
    PORT
      LAYER M4 ;
        RECT  17.196 56.208 17.28 56.232 ;
    END
  END q[402]
  PIN q[403]
    DIRECTION OUTPUT ;
    USE SIGNAL ;
    PORT
      LAYER M4 ;
        RECT  17.196 56.304 17.28 56.328 ;
    END
  END q[403]
  PIN q[404]
    DIRECTION OUTPUT ;
    USE SIGNAL ;
    PORT
      LAYER M4 ;
        RECT  17.196 56.4 17.28 56.424 ;
    END
  END q[404]
  PIN q[405]
    DIRECTION OUTPUT ;
    USE SIGNAL ;
    PORT
      LAYER M4 ;
        RECT  17.196 56.496 17.28 56.52 ;
    END
  END q[405]
  PIN q[406]
    DIRECTION OUTPUT ;
    USE SIGNAL ;
    PORT
      LAYER M4 ;
        RECT  17.196 56.592 17.28 56.616 ;
    END
  END q[406]
  PIN q[407]
    DIRECTION OUTPUT ;
    USE SIGNAL ;
    PORT
      LAYER M4 ;
        RECT  17.196 56.688 17.28 56.712 ;
    END
  END q[407]
  PIN q[408]
    DIRECTION OUTPUT ;
    USE SIGNAL ;
    PORT
      LAYER M4 ;
        RECT  17.196 56.784 17.28 56.808 ;
    END
  END q[408]
  PIN q[409]
    DIRECTION OUTPUT ;
    USE SIGNAL ;
    PORT
      LAYER M4 ;
        RECT  17.196 56.88 17.28 56.904 ;
    END
  END q[409]
  PIN q[40]
    DIRECTION OUTPUT ;
    USE SIGNAL ;
    PORT
      LAYER M4 ;
        RECT  17.196 32.976 17.28 33 ;
    END
  END q[40]
  PIN q[410]
    DIRECTION OUTPUT ;
    USE SIGNAL ;
    PORT
      LAYER M4 ;
        RECT  17.196 56.976 17.28 57 ;
    END
  END q[410]
  PIN q[411]
    DIRECTION OUTPUT ;
    USE SIGNAL ;
    PORT
      LAYER M4 ;
        RECT  17.196 57.072 17.28 57.096 ;
    END
  END q[411]
  PIN q[412]
    DIRECTION OUTPUT ;
    USE SIGNAL ;
    PORT
      LAYER M4 ;
        RECT  17.196 57.168 17.28 57.192 ;
    END
  END q[412]
  PIN q[413]
    DIRECTION OUTPUT ;
    USE SIGNAL ;
    PORT
      LAYER M4 ;
        RECT  17.196 57.264 17.28 57.288 ;
    END
  END q[413]
  PIN q[414]
    DIRECTION OUTPUT ;
    USE SIGNAL ;
    PORT
      LAYER M4 ;
        RECT  17.196 57.36 17.28 57.384 ;
    END
  END q[414]
  PIN q[415]
    DIRECTION OUTPUT ;
    USE SIGNAL ;
    PORT
      LAYER M4 ;
        RECT  17.196 57.456 17.28 57.48 ;
    END
  END q[415]
  PIN q[416]
    DIRECTION OUTPUT ;
    USE SIGNAL ;
    PORT
      LAYER M4 ;
        RECT  17.196 51.408 17.28 51.432 ;
    END
  END q[416]
  PIN q[417]
    DIRECTION OUTPUT ;
    USE SIGNAL ;
    PORT
      LAYER M4 ;
        RECT  17.196 51.504 17.28 51.528 ;
    END
  END q[417]
  PIN q[418]
    DIRECTION OUTPUT ;
    USE SIGNAL ;
    PORT
      LAYER M4 ;
        RECT  17.196 51.6 17.28 51.624 ;
    END
  END q[418]
  PIN q[419]
    DIRECTION OUTPUT ;
    USE SIGNAL ;
    PORT
      LAYER M4 ;
        RECT  17.196 51.696 17.28 51.72 ;
    END
  END q[419]
  PIN q[41]
    DIRECTION OUTPUT ;
    USE SIGNAL ;
    PORT
      LAYER M4 ;
        RECT  17.196 33.072 17.28 33.096 ;
    END
  END q[41]
  PIN q[420]
    DIRECTION OUTPUT ;
    USE SIGNAL ;
    PORT
      LAYER M4 ;
        RECT  17.196 51.792 17.28 51.816 ;
    END
  END q[420]
  PIN q[421]
    DIRECTION OUTPUT ;
    USE SIGNAL ;
    PORT
      LAYER M4 ;
        RECT  17.196 51.888 17.28 51.912 ;
    END
  END q[421]
  PIN q[422]
    DIRECTION OUTPUT ;
    USE SIGNAL ;
    PORT
      LAYER M4 ;
        RECT  17.196 51.984 17.28 52.008 ;
    END
  END q[422]
  PIN q[423]
    DIRECTION OUTPUT ;
    USE SIGNAL ;
    PORT
      LAYER M4 ;
        RECT  17.196 52.08 17.28 52.104 ;
    END
  END q[423]
  PIN q[424]
    DIRECTION OUTPUT ;
    USE SIGNAL ;
    PORT
      LAYER M4 ;
        RECT  17.196 52.176 17.28 52.2 ;
    END
  END q[424]
  PIN q[425]
    DIRECTION OUTPUT ;
    USE SIGNAL ;
    PORT
      LAYER M4 ;
        RECT  17.196 52.272 17.28 52.296 ;
    END
  END q[425]
  PIN q[426]
    DIRECTION OUTPUT ;
    USE SIGNAL ;
    PORT
      LAYER M4 ;
        RECT  17.196 52.368 17.28 52.392 ;
    END
  END q[426]
  PIN q[427]
    DIRECTION OUTPUT ;
    USE SIGNAL ;
    PORT
      LAYER M4 ;
        RECT  17.196 52.464 17.28 52.488 ;
    END
  END q[427]
  PIN q[428]
    DIRECTION OUTPUT ;
    USE SIGNAL ;
    PORT
      LAYER M4 ;
        RECT  17.196 52.56 17.28 52.584 ;
    END
  END q[428]
  PIN q[429]
    DIRECTION OUTPUT ;
    USE SIGNAL ;
    PORT
      LAYER M4 ;
        RECT  17.196 52.656 17.28 52.68 ;
    END
  END q[429]
  PIN q[42]
    DIRECTION OUTPUT ;
    USE SIGNAL ;
    PORT
      LAYER M4 ;
        RECT  17.196 33.168 17.28 33.192 ;
    END
  END q[42]
  PIN q[430]
    DIRECTION OUTPUT ;
    USE SIGNAL ;
    PORT
      LAYER M4 ;
        RECT  17.196 52.752 17.28 52.776 ;
    END
  END q[430]
  PIN q[431]
    DIRECTION OUTPUT ;
    USE SIGNAL ;
    PORT
      LAYER M4 ;
        RECT  17.196 52.848 17.28 52.872 ;
    END
  END q[431]
  PIN q[432]
    DIRECTION OUTPUT ;
    USE SIGNAL ;
    PORT
      LAYER M4 ;
        RECT  17.196 52.944 17.28 52.968 ;
    END
  END q[432]
  PIN q[433]
    DIRECTION OUTPUT ;
    USE SIGNAL ;
    PORT
      LAYER M4 ;
        RECT  17.196 53.04 17.28 53.064 ;
    END
  END q[433]
  PIN q[434]
    DIRECTION OUTPUT ;
    USE SIGNAL ;
    PORT
      LAYER M4 ;
        RECT  17.196 53.136 17.28 53.16 ;
    END
  END q[434]
  PIN q[435]
    DIRECTION OUTPUT ;
    USE SIGNAL ;
    PORT
      LAYER M4 ;
        RECT  17.196 53.232 17.28 53.256 ;
    END
  END q[435]
  PIN q[436]
    DIRECTION OUTPUT ;
    USE SIGNAL ;
    PORT
      LAYER M4 ;
        RECT  17.196 53.328 17.28 53.352 ;
    END
  END q[436]
  PIN q[437]
    DIRECTION OUTPUT ;
    USE SIGNAL ;
    PORT
      LAYER M4 ;
        RECT  17.196 53.424 17.28 53.448 ;
    END
  END q[437]
  PIN q[438]
    DIRECTION OUTPUT ;
    USE SIGNAL ;
    PORT
      LAYER M4 ;
        RECT  17.196 53.52 17.28 53.544 ;
    END
  END q[438]
  PIN q[439]
    DIRECTION OUTPUT ;
    USE SIGNAL ;
    PORT
      LAYER M4 ;
        RECT  17.196 53.616 17.28 53.64 ;
    END
  END q[439]
  PIN q[43]
    DIRECTION OUTPUT ;
    USE SIGNAL ;
    PORT
      LAYER M4 ;
        RECT  17.196 33.264 17.28 33.288 ;
    END
  END q[43]
  PIN q[440]
    DIRECTION OUTPUT ;
    USE SIGNAL ;
    PORT
      LAYER M4 ;
        RECT  17.196 53.712 17.28 53.736 ;
    END
  END q[440]
  PIN q[441]
    DIRECTION OUTPUT ;
    USE SIGNAL ;
    PORT
      LAYER M4 ;
        RECT  17.196 53.808 17.28 53.832 ;
    END
  END q[441]
  PIN q[442]
    DIRECTION OUTPUT ;
    USE SIGNAL ;
    PORT
      LAYER M4 ;
        RECT  17.196 53.904 17.28 53.928 ;
    END
  END q[442]
  PIN q[443]
    DIRECTION OUTPUT ;
    USE SIGNAL ;
    PORT
      LAYER M4 ;
        RECT  17.196 54 17.28 54.024 ;
    END
  END q[443]
  PIN q[444]
    DIRECTION OUTPUT ;
    USE SIGNAL ;
    PORT
      LAYER M4 ;
        RECT  17.196 54.096 17.28 54.12 ;
    END
  END q[444]
  PIN q[445]
    DIRECTION OUTPUT ;
    USE SIGNAL ;
    PORT
      LAYER M4 ;
        RECT  17.196 54.192 17.28 54.216 ;
    END
  END q[445]
  PIN q[446]
    DIRECTION OUTPUT ;
    USE SIGNAL ;
    PORT
      LAYER M4 ;
        RECT  17.196 54.288 17.28 54.312 ;
    END
  END q[446]
  PIN q[447]
    DIRECTION OUTPUT ;
    USE SIGNAL ;
    PORT
      LAYER M4 ;
        RECT  17.196 54.384 17.28 54.408 ;
    END
  END q[447]
  PIN q[448]
    DIRECTION OUTPUT ;
    USE SIGNAL ;
    PORT
      LAYER M4 ;
        RECT  17.196 6.864 17.28 6.888 ;
    END
  END q[448]
  PIN q[449]
    DIRECTION OUTPUT ;
    USE SIGNAL ;
    PORT
      LAYER M4 ;
        RECT  17.196 6.96 17.28 6.984 ;
    END
  END q[449]
  PIN q[44]
    DIRECTION OUTPUT ;
    USE SIGNAL ;
    PORT
      LAYER M4 ;
        RECT  17.196 33.36 17.28 33.384 ;
    END
  END q[44]
  PIN q[450]
    DIRECTION OUTPUT ;
    USE SIGNAL ;
    PORT
      LAYER M4 ;
        RECT  17.196 7.056 17.28 7.08 ;
    END
  END q[450]
  PIN q[451]
    DIRECTION OUTPUT ;
    USE SIGNAL ;
    PORT
      LAYER M4 ;
        RECT  17.196 7.152 17.28 7.176 ;
    END
  END q[451]
  PIN q[452]
    DIRECTION OUTPUT ;
    USE SIGNAL ;
    PORT
      LAYER M4 ;
        RECT  17.196 7.248 17.28 7.272 ;
    END
  END q[452]
  PIN q[453]
    DIRECTION OUTPUT ;
    USE SIGNAL ;
    PORT
      LAYER M4 ;
        RECT  17.196 7.344 17.28 7.368 ;
    END
  END q[453]
  PIN q[454]
    DIRECTION OUTPUT ;
    USE SIGNAL ;
    PORT
      LAYER M4 ;
        RECT  17.196 7.44 17.28 7.464 ;
    END
  END q[454]
  PIN q[455]
    DIRECTION OUTPUT ;
    USE SIGNAL ;
    PORT
      LAYER M4 ;
        RECT  17.196 7.536 17.28 7.56 ;
    END
  END q[455]
  PIN q[456]
    DIRECTION OUTPUT ;
    USE SIGNAL ;
    PORT
      LAYER M4 ;
        RECT  17.196 7.632 17.28 7.656 ;
    END
  END q[456]
  PIN q[457]
    DIRECTION OUTPUT ;
    USE SIGNAL ;
    PORT
      LAYER M4 ;
        RECT  17.196 7.728 17.28 7.752 ;
    END
  END q[457]
  PIN q[458]
    DIRECTION OUTPUT ;
    USE SIGNAL ;
    PORT
      LAYER M4 ;
        RECT  17.196 7.824 17.28 7.848 ;
    END
  END q[458]
  PIN q[459]
    DIRECTION OUTPUT ;
    USE SIGNAL ;
    PORT
      LAYER M4 ;
        RECT  17.196 7.92 17.28 7.944 ;
    END
  END q[459]
  PIN q[45]
    DIRECTION OUTPUT ;
    USE SIGNAL ;
    PORT
      LAYER M4 ;
        RECT  17.196 33.456 17.28 33.48 ;
    END
  END q[45]
  PIN q[460]
    DIRECTION OUTPUT ;
    USE SIGNAL ;
    PORT
      LAYER M4 ;
        RECT  17.196 8.016 17.28 8.04 ;
    END
  END q[460]
  PIN q[461]
    DIRECTION OUTPUT ;
    USE SIGNAL ;
    PORT
      LAYER M4 ;
        RECT  17.196 8.112 17.28 8.136 ;
    END
  END q[461]
  PIN q[462]
    DIRECTION OUTPUT ;
    USE SIGNAL ;
    PORT
      LAYER M4 ;
        RECT  17.196 8.208 17.28 8.232 ;
    END
  END q[462]
  PIN q[463]
    DIRECTION OUTPUT ;
    USE SIGNAL ;
    PORT
      LAYER M4 ;
        RECT  17.196 8.304 17.28 8.328 ;
    END
  END q[463]
  PIN q[464]
    DIRECTION OUTPUT ;
    USE SIGNAL ;
    PORT
      LAYER M4 ;
        RECT  17.196 8.4 17.28 8.424 ;
    END
  END q[464]
  PIN q[465]
    DIRECTION OUTPUT ;
    USE SIGNAL ;
    PORT
      LAYER M4 ;
        RECT  17.196 8.496 17.28 8.52 ;
    END
  END q[465]
  PIN q[466]
    DIRECTION OUTPUT ;
    USE SIGNAL ;
    PORT
      LAYER M4 ;
        RECT  17.196 8.592 17.28 8.616 ;
    END
  END q[466]
  PIN q[467]
    DIRECTION OUTPUT ;
    USE SIGNAL ;
    PORT
      LAYER M4 ;
        RECT  17.196 8.688 17.28 8.712 ;
    END
  END q[467]
  PIN q[468]
    DIRECTION OUTPUT ;
    USE SIGNAL ;
    PORT
      LAYER M4 ;
        RECT  17.196 8.784 17.28 8.808 ;
    END
  END q[468]
  PIN q[469]
    DIRECTION OUTPUT ;
    USE SIGNAL ;
    PORT
      LAYER M4 ;
        RECT  17.196 8.88 17.28 8.904 ;
    END
  END q[469]
  PIN q[46]
    DIRECTION OUTPUT ;
    USE SIGNAL ;
    PORT
      LAYER M4 ;
        RECT  17.196 33.552 17.28 33.576 ;
    END
  END q[46]
  PIN q[470]
    DIRECTION OUTPUT ;
    USE SIGNAL ;
    PORT
      LAYER M4 ;
        RECT  17.196 8.976 17.28 9 ;
    END
  END q[470]
  PIN q[471]
    DIRECTION OUTPUT ;
    USE SIGNAL ;
    PORT
      LAYER M4 ;
        RECT  17.196 9.072 17.28 9.096 ;
    END
  END q[471]
  PIN q[472]
    DIRECTION OUTPUT ;
    USE SIGNAL ;
    PORT
      LAYER M4 ;
        RECT  17.196 9.168 17.28 9.192 ;
    END
  END q[472]
  PIN q[473]
    DIRECTION OUTPUT ;
    USE SIGNAL ;
    PORT
      LAYER M4 ;
        RECT  17.196 9.264 17.28 9.288 ;
    END
  END q[473]
  PIN q[474]
    DIRECTION OUTPUT ;
    USE SIGNAL ;
    PORT
      LAYER M4 ;
        RECT  17.196 9.36 17.28 9.384 ;
    END
  END q[474]
  PIN q[475]
    DIRECTION OUTPUT ;
    USE SIGNAL ;
    PORT
      LAYER M4 ;
        RECT  17.196 9.456 17.28 9.48 ;
    END
  END q[475]
  PIN q[476]
    DIRECTION OUTPUT ;
    USE SIGNAL ;
    PORT
      LAYER M4 ;
        RECT  17.196 9.552 17.28 9.576 ;
    END
  END q[476]
  PIN q[477]
    DIRECTION OUTPUT ;
    USE SIGNAL ;
    PORT
      LAYER M4 ;
        RECT  17.196 9.648 17.28 9.672 ;
    END
  END q[477]
  PIN q[478]
    DIRECTION OUTPUT ;
    USE SIGNAL ;
    PORT
      LAYER M4 ;
        RECT  17.196 9.744 17.28 9.768 ;
    END
  END q[478]
  PIN q[479]
    DIRECTION OUTPUT ;
    USE SIGNAL ;
    PORT
      LAYER M4 ;
        RECT  17.196 9.84 17.28 9.864 ;
    END
  END q[479]
  PIN q[47]
    DIRECTION OUTPUT ;
    USE SIGNAL ;
    PORT
      LAYER M4 ;
        RECT  17.196 33.648 17.28 33.672 ;
    END
  END q[47]
  PIN q[480]
    DIRECTION OUTPUT ;
    USE SIGNAL ;
    PORT
      LAYER M4 ;
        RECT  17.196 16.08 17.28 16.104 ;
    END
  END q[480]
  PIN q[481]
    DIRECTION OUTPUT ;
    USE SIGNAL ;
    PORT
      LAYER M4 ;
        RECT  17.196 16.176 17.28 16.2 ;
    END
  END q[481]
  PIN q[482]
    DIRECTION OUTPUT ;
    USE SIGNAL ;
    PORT
      LAYER M4 ;
        RECT  17.196 16.272 17.28 16.296 ;
    END
  END q[482]
  PIN q[483]
    DIRECTION OUTPUT ;
    USE SIGNAL ;
    PORT
      LAYER M4 ;
        RECT  17.196 16.368 17.28 16.392 ;
    END
  END q[483]
  PIN q[484]
    DIRECTION OUTPUT ;
    USE SIGNAL ;
    PORT
      LAYER M4 ;
        RECT  17.196 16.464 17.28 16.488 ;
    END
  END q[484]
  PIN q[485]
    DIRECTION OUTPUT ;
    USE SIGNAL ;
    PORT
      LAYER M4 ;
        RECT  17.196 16.56 17.28 16.584 ;
    END
  END q[485]
  PIN q[486]
    DIRECTION OUTPUT ;
    USE SIGNAL ;
    PORT
      LAYER M4 ;
        RECT  17.196 16.656 17.28 16.68 ;
    END
  END q[486]
  PIN q[487]
    DIRECTION OUTPUT ;
    USE SIGNAL ;
    PORT
      LAYER M4 ;
        RECT  17.196 16.752 17.28 16.776 ;
    END
  END q[487]
  PIN q[488]
    DIRECTION OUTPUT ;
    USE SIGNAL ;
    PORT
      LAYER M4 ;
        RECT  17.196 16.848 17.28 16.872 ;
    END
  END q[488]
  PIN q[489]
    DIRECTION OUTPUT ;
    USE SIGNAL ;
    PORT
      LAYER M4 ;
        RECT  17.196 16.944 17.28 16.968 ;
    END
  END q[489]
  PIN q[48]
    DIRECTION OUTPUT ;
    USE SIGNAL ;
    PORT
      LAYER M4 ;
        RECT  17.196 33.744 17.28 33.768 ;
    END
  END q[48]
  PIN q[490]
    DIRECTION OUTPUT ;
    USE SIGNAL ;
    PORT
      LAYER M4 ;
        RECT  17.196 17.04 17.28 17.064 ;
    END
  END q[490]
  PIN q[491]
    DIRECTION OUTPUT ;
    USE SIGNAL ;
    PORT
      LAYER M4 ;
        RECT  17.196 17.136 17.28 17.16 ;
    END
  END q[491]
  PIN q[492]
    DIRECTION OUTPUT ;
    USE SIGNAL ;
    PORT
      LAYER M4 ;
        RECT  17.196 17.232 17.28 17.256 ;
    END
  END q[492]
  PIN q[493]
    DIRECTION OUTPUT ;
    USE SIGNAL ;
    PORT
      LAYER M4 ;
        RECT  17.196 17.328 17.28 17.352 ;
    END
  END q[493]
  PIN q[494]
    DIRECTION OUTPUT ;
    USE SIGNAL ;
    PORT
      LAYER M4 ;
        RECT  17.196 17.424 17.28 17.448 ;
    END
  END q[494]
  PIN q[495]
    DIRECTION OUTPUT ;
    USE SIGNAL ;
    PORT
      LAYER M4 ;
        RECT  17.196 17.52 17.28 17.544 ;
    END
  END q[495]
  PIN q[496]
    DIRECTION OUTPUT ;
    USE SIGNAL ;
    PORT
      LAYER M4 ;
        RECT  17.196 17.616 17.28 17.64 ;
    END
  END q[496]
  PIN q[497]
    DIRECTION OUTPUT ;
    USE SIGNAL ;
    PORT
      LAYER M4 ;
        RECT  17.196 17.712 17.28 17.736 ;
    END
  END q[497]
  PIN q[498]
    DIRECTION OUTPUT ;
    USE SIGNAL ;
    PORT
      LAYER M4 ;
        RECT  17.196 17.808 17.28 17.832 ;
    END
  END q[498]
  PIN q[499]
    DIRECTION OUTPUT ;
    USE SIGNAL ;
    PORT
      LAYER M4 ;
        RECT  17.196 17.904 17.28 17.928 ;
    END
  END q[499]
  PIN q[49]
    DIRECTION OUTPUT ;
    USE SIGNAL ;
    PORT
      LAYER M4 ;
        RECT  17.196 33.84 17.28 33.864 ;
    END
  END q[49]
  PIN q[4]
    DIRECTION OUTPUT ;
    USE SIGNAL ;
    PORT
      LAYER M4 ;
        RECT  17.196 29.52 17.28 29.544 ;
    END
  END q[4]
  PIN q[500]
    DIRECTION OUTPUT ;
    USE SIGNAL ;
    PORT
      LAYER M4 ;
        RECT  17.196 18 17.28 18.024 ;
    END
  END q[500]
  PIN q[501]
    DIRECTION OUTPUT ;
    USE SIGNAL ;
    PORT
      LAYER M4 ;
        RECT  17.196 18.096 17.28 18.12 ;
    END
  END q[501]
  PIN q[502]
    DIRECTION OUTPUT ;
    USE SIGNAL ;
    PORT
      LAYER M4 ;
        RECT  17.196 18.192 17.28 18.216 ;
    END
  END q[502]
  PIN q[503]
    DIRECTION OUTPUT ;
    USE SIGNAL ;
    PORT
      LAYER M4 ;
        RECT  17.196 18.288 17.28 18.312 ;
    END
  END q[503]
  PIN q[504]
    DIRECTION OUTPUT ;
    USE SIGNAL ;
    PORT
      LAYER M4 ;
        RECT  17.196 18.384 17.28 18.408 ;
    END
  END q[504]
  PIN q[505]
    DIRECTION OUTPUT ;
    USE SIGNAL ;
    PORT
      LAYER M4 ;
        RECT  17.196 18.48 17.28 18.504 ;
    END
  END q[505]
  PIN q[506]
    DIRECTION OUTPUT ;
    USE SIGNAL ;
    PORT
      LAYER M4 ;
        RECT  17.196 18.576 17.28 18.6 ;
    END
  END q[506]
  PIN q[507]
    DIRECTION OUTPUT ;
    USE SIGNAL ;
    PORT
      LAYER M4 ;
        RECT  17.196 18.672 17.28 18.696 ;
    END
  END q[507]
  PIN q[508]
    DIRECTION OUTPUT ;
    USE SIGNAL ;
    PORT
      LAYER M4 ;
        RECT  17.196 18.768 17.28 18.792 ;
    END
  END q[508]
  PIN q[509]
    DIRECTION OUTPUT ;
    USE SIGNAL ;
    PORT
      LAYER M4 ;
        RECT  17.196 18.864 17.28 18.888 ;
    END
  END q[509]
  PIN q[50]
    DIRECTION OUTPUT ;
    USE SIGNAL ;
    PORT
      LAYER M4 ;
        RECT  17.196 33.936 17.28 33.96 ;
    END
  END q[50]
  PIN q[510]
    DIRECTION OUTPUT ;
    USE SIGNAL ;
    PORT
      LAYER M4 ;
        RECT  17.196 18.96 17.28 18.984 ;
    END
  END q[510]
  PIN q[511]
    DIRECTION OUTPUT ;
    USE SIGNAL ;
    PORT
      LAYER M4 ;
        RECT  17.196 19.056 17.28 19.08 ;
    END
  END q[511]
  PIN q[51]
    DIRECTION OUTPUT ;
    USE SIGNAL ;
    PORT
      LAYER M4 ;
        RECT  17.196 34.032 17.28 34.056 ;
    END
  END q[51]
  PIN q[52]
    DIRECTION OUTPUT ;
    USE SIGNAL ;
    PORT
      LAYER M4 ;
        RECT  17.196 34.128 17.28 34.152 ;
    END
  END q[52]
  PIN q[53]
    DIRECTION OUTPUT ;
    USE SIGNAL ;
    PORT
      LAYER M4 ;
        RECT  17.196 34.224 17.28 34.248 ;
    END
  END q[53]
  PIN q[54]
    DIRECTION OUTPUT ;
    USE SIGNAL ;
    PORT
      LAYER M4 ;
        RECT  17.196 34.32 17.28 34.344 ;
    END
  END q[54]
  PIN q[55]
    DIRECTION OUTPUT ;
    USE SIGNAL ;
    PORT
      LAYER M4 ;
        RECT  17.196 34.416 17.28 34.44 ;
    END
  END q[55]
  PIN q[56]
    DIRECTION OUTPUT ;
    USE SIGNAL ;
    PORT
      LAYER M4 ;
        RECT  17.196 34.512 17.28 34.536 ;
    END
  END q[56]
  PIN q[57]
    DIRECTION OUTPUT ;
    USE SIGNAL ;
    PORT
      LAYER M4 ;
        RECT  17.196 34.608 17.28 34.632 ;
    END
  END q[57]
  PIN q[58]
    DIRECTION OUTPUT ;
    USE SIGNAL ;
    PORT
      LAYER M4 ;
        RECT  17.196 34.704 17.28 34.728 ;
    END
  END q[58]
  PIN q[59]
    DIRECTION OUTPUT ;
    USE SIGNAL ;
    PORT
      LAYER M4 ;
        RECT  17.196 34.8 17.28 34.824 ;
    END
  END q[59]
  PIN q[5]
    DIRECTION OUTPUT ;
    USE SIGNAL ;
    PORT
      LAYER M4 ;
        RECT  17.196 29.616 17.28 29.64 ;
    END
  END q[5]
  PIN q[60]
    DIRECTION OUTPUT ;
    USE SIGNAL ;
    PORT
      LAYER M4 ;
        RECT  17.196 34.896 17.28 34.92 ;
    END
  END q[60]
  PIN q[61]
    DIRECTION OUTPUT ;
    USE SIGNAL ;
    PORT
      LAYER M4 ;
        RECT  17.196 34.992 17.28 35.016 ;
    END
  END q[61]
  PIN q[62]
    DIRECTION OUTPUT ;
    USE SIGNAL ;
    PORT
      LAYER M4 ;
        RECT  17.196 35.088 17.28 35.112 ;
    END
  END q[62]
  PIN q[63]
    DIRECTION OUTPUT ;
    USE SIGNAL ;
    PORT
      LAYER M4 ;
        RECT  17.196 35.184 17.28 35.208 ;
    END
  END q[63]
  PIN q[64]
    DIRECTION OUTPUT ;
    USE SIGNAL ;
    PORT
      LAYER M4 ;
        RECT  17.196 19.92 17.28 19.944 ;
    END
  END q[64]
  PIN q[65]
    DIRECTION OUTPUT ;
    USE SIGNAL ;
    PORT
      LAYER M4 ;
        RECT  17.196 20.016 17.28 20.04 ;
    END
  END q[65]
  PIN q[66]
    DIRECTION OUTPUT ;
    USE SIGNAL ;
    PORT
      LAYER M4 ;
        RECT  17.196 20.112 17.28 20.136 ;
    END
  END q[66]
  PIN q[67]
    DIRECTION OUTPUT ;
    USE SIGNAL ;
    PORT
      LAYER M4 ;
        RECT  17.196 20.208 17.28 20.232 ;
    END
  END q[67]
  PIN q[68]
    DIRECTION OUTPUT ;
    USE SIGNAL ;
    PORT
      LAYER M4 ;
        RECT  17.196 20.304 17.28 20.328 ;
    END
  END q[68]
  PIN q[69]
    DIRECTION OUTPUT ;
    USE SIGNAL ;
    PORT
      LAYER M4 ;
        RECT  17.196 20.4 17.28 20.424 ;
    END
  END q[69]
  PIN q[6]
    DIRECTION OUTPUT ;
    USE SIGNAL ;
    PORT
      LAYER M4 ;
        RECT  17.196 29.712 17.28 29.736 ;
    END
  END q[6]
  PIN q[70]
    DIRECTION OUTPUT ;
    USE SIGNAL ;
    PORT
      LAYER M4 ;
        RECT  17.196 20.496 17.28 20.52 ;
    END
  END q[70]
  PIN q[71]
    DIRECTION OUTPUT ;
    USE SIGNAL ;
    PORT
      LAYER M4 ;
        RECT  17.196 20.592 17.28 20.616 ;
    END
  END q[71]
  PIN q[72]
    DIRECTION OUTPUT ;
    USE SIGNAL ;
    PORT
      LAYER M4 ;
        RECT  17.196 20.688 17.28 20.712 ;
    END
  END q[72]
  PIN q[73]
    DIRECTION OUTPUT ;
    USE SIGNAL ;
    PORT
      LAYER M4 ;
        RECT  17.196 20.784 17.28 20.808 ;
    END
  END q[73]
  PIN q[74]
    DIRECTION OUTPUT ;
    USE SIGNAL ;
    PORT
      LAYER M4 ;
        RECT  17.196 20.88 17.28 20.904 ;
    END
  END q[74]
  PIN q[75]
    DIRECTION OUTPUT ;
    USE SIGNAL ;
    PORT
      LAYER M4 ;
        RECT  17.196 20.976 17.28 21 ;
    END
  END q[75]
  PIN q[76]
    DIRECTION OUTPUT ;
    USE SIGNAL ;
    PORT
      LAYER M4 ;
        RECT  17.196 21.072 17.28 21.096 ;
    END
  END q[76]
  PIN q[77]
    DIRECTION OUTPUT ;
    USE SIGNAL ;
    PORT
      LAYER M4 ;
        RECT  17.196 21.168 17.28 21.192 ;
    END
  END q[77]
  PIN q[78]
    DIRECTION OUTPUT ;
    USE SIGNAL ;
    PORT
      LAYER M4 ;
        RECT  17.196 21.264 17.28 21.288 ;
    END
  END q[78]
  PIN q[79]
    DIRECTION OUTPUT ;
    USE SIGNAL ;
    PORT
      LAYER M4 ;
        RECT  17.196 21.36 17.28 21.384 ;
    END
  END q[79]
  PIN q[7]
    DIRECTION OUTPUT ;
    USE SIGNAL ;
    PORT
      LAYER M4 ;
        RECT  17.196 29.808 17.28 29.832 ;
    END
  END q[7]
  PIN q[80]
    DIRECTION OUTPUT ;
    USE SIGNAL ;
    PORT
      LAYER M4 ;
        RECT  17.196 21.456 17.28 21.48 ;
    END
  END q[80]
  PIN q[81]
    DIRECTION OUTPUT ;
    USE SIGNAL ;
    PORT
      LAYER M4 ;
        RECT  17.196 21.552 17.28 21.576 ;
    END
  END q[81]
  PIN q[82]
    DIRECTION OUTPUT ;
    USE SIGNAL ;
    PORT
      LAYER M4 ;
        RECT  17.196 21.648 17.28 21.672 ;
    END
  END q[82]
  PIN q[83]
    DIRECTION OUTPUT ;
    USE SIGNAL ;
    PORT
      LAYER M4 ;
        RECT  17.196 21.744 17.28 21.768 ;
    END
  END q[83]
  PIN q[84]
    DIRECTION OUTPUT ;
    USE SIGNAL ;
    PORT
      LAYER M4 ;
        RECT  17.196 21.84 17.28 21.864 ;
    END
  END q[84]
  PIN q[85]
    DIRECTION OUTPUT ;
    USE SIGNAL ;
    PORT
      LAYER M4 ;
        RECT  17.196 21.936 17.28 21.96 ;
    END
  END q[85]
  PIN q[86]
    DIRECTION OUTPUT ;
    USE SIGNAL ;
    PORT
      LAYER M4 ;
        RECT  17.196 22.032 17.28 22.056 ;
    END
  END q[86]
  PIN q[87]
    DIRECTION OUTPUT ;
    USE SIGNAL ;
    PORT
      LAYER M4 ;
        RECT  17.196 22.128 17.28 22.152 ;
    END
  END q[87]
  PIN q[88]
    DIRECTION OUTPUT ;
    USE SIGNAL ;
    PORT
      LAYER M4 ;
        RECT  17.196 22.224 17.28 22.248 ;
    END
  END q[88]
  PIN q[89]
    DIRECTION OUTPUT ;
    USE SIGNAL ;
    PORT
      LAYER M4 ;
        RECT  17.196 22.32 17.28 22.344 ;
    END
  END q[89]
  PIN q[8]
    DIRECTION OUTPUT ;
    USE SIGNAL ;
    PORT
      LAYER M4 ;
        RECT  17.196 29.904 17.28 29.928 ;
    END
  END q[8]
  PIN q[90]
    DIRECTION OUTPUT ;
    USE SIGNAL ;
    PORT
      LAYER M4 ;
        RECT  17.196 22.416 17.28 22.44 ;
    END
  END q[90]
  PIN q[91]
    DIRECTION OUTPUT ;
    USE SIGNAL ;
    PORT
      LAYER M4 ;
        RECT  17.196 22.512 17.28 22.536 ;
    END
  END q[91]
  PIN q[92]
    DIRECTION OUTPUT ;
    USE SIGNAL ;
    PORT
      LAYER M4 ;
        RECT  17.196 22.608 17.28 22.632 ;
    END
  END q[92]
  PIN q[93]
    DIRECTION OUTPUT ;
    USE SIGNAL ;
    PORT
      LAYER M4 ;
        RECT  17.196 22.704 17.28 22.728 ;
    END
  END q[93]
  PIN q[94]
    DIRECTION OUTPUT ;
    USE SIGNAL ;
    PORT
      LAYER M4 ;
        RECT  17.196 22.8 17.28 22.824 ;
    END
  END q[94]
  PIN q[95]
    DIRECTION OUTPUT ;
    USE SIGNAL ;
    PORT
      LAYER M4 ;
        RECT  17.196 22.896 17.28 22.92 ;
    END
  END q[95]
  PIN q[96]
    DIRECTION OUTPUT ;
    USE SIGNAL ;
    PORT
      LAYER M4 ;
        RECT  17.196 22.992 17.28 23.016 ;
    END
  END q[96]
  PIN q[97]
    DIRECTION OUTPUT ;
    USE SIGNAL ;
    PORT
      LAYER M4 ;
        RECT  17.196 23.088 17.28 23.112 ;
    END
  END q[97]
  PIN q[98]
    DIRECTION OUTPUT ;
    USE SIGNAL ;
    PORT
      LAYER M4 ;
        RECT  17.196 23.184 17.28 23.208 ;
    END
  END q[98]
  PIN q[99]
    DIRECTION OUTPUT ;
    USE SIGNAL ;
    PORT
      LAYER M4 ;
        RECT  17.196 23.28 17.28 23.304 ;
    END
  END q[99]
  PIN q[9]
    DIRECTION OUTPUT ;
    USE SIGNAL ;
    PORT
      LAYER M4 ;
        RECT  17.196 30 17.28 30.024 ;
    END
  END q[9]
  PIN VDD
    DIRECTION INOUT ;
    USE POWER ;
    PORT
      LAYER M5 ;
        RECT  13.392 2.151 13.512 62.649 ;
        RECT  7.992 2.151 8.112 62.649 ;
        RECT  2.592 2.151 2.712 62.649 ;
    END
  END VDD
  PIN VSS
    DIRECTION INOUT ;
    USE GROUND ;
    PORT
      LAYER M5 ;
        RECT  13.2 2.137 13.32 62.663 ;
        RECT  7.8 2.137 7.92 62.663 ;
        RECT  2.4 2.137 2.52 62.663 ;
    END
  END VSS
  OBS
    LAYER RVTN ;
     RECT  2.16 2.16 15.12 2.295 ;
     RECT  2.16 2.565 15.12 2.835 ;
     RECT  2.16 3.105 15.12 3.375 ;
     RECT  2.16 3.645 15.12 3.915 ;
     RECT  2.16 4.185 15.12 4.455 ;
     RECT  2.16 4.725 15.12 4.995 ;
     RECT  2.16 5.265 15.12 5.535 ;
     RECT  2.16 5.805 15.12 6.075 ;
     RECT  2.16 6.345 15.12 6.615 ;
     RECT  2.16 6.885 15.12 7.155 ;
     RECT  2.16 7.425 15.12 7.695 ;
     RECT  2.16 7.965 15.12 8.235 ;
     RECT  2.16 8.505 15.12 8.775 ;
     RECT  2.16 9.045 15.12 9.315 ;
     RECT  2.16 9.585 15.12 9.855 ;
     RECT  2.16 10.125 15.12 10.395 ;
     RECT  2.16 10.665 15.12 10.935 ;
     RECT  2.16 11.205 15.12 11.475 ;
     RECT  2.16 11.745 15.12 12.015 ;
     RECT  2.16 12.285 15.12 12.555 ;
     RECT  2.16 12.825 15.12 13.095 ;
     RECT  2.16 13.365 15.12 13.635 ;
     RECT  2.16 13.905 15.12 14.175 ;
     RECT  2.16 14.445 15.12 14.715 ;
     RECT  2.16 14.985 15.12 15.255 ;
     RECT  2.16 15.525 15.12 15.795 ;
     RECT  2.16 16.065 15.12 16.335 ;
     RECT  2.16 16.605 15.12 16.875 ;
     RECT  2.16 17.145 15.12 17.415 ;
     RECT  2.16 17.685 15.12 17.955 ;
     RECT  2.16 18.225 15.12 18.495 ;
     RECT  2.16 18.765 15.12 19.035 ;
     RECT  2.16 19.305 15.12 19.575 ;
     RECT  2.16 19.845 15.12 20.115 ;
     RECT  2.16 20.385 15.12 20.655 ;
     RECT  2.16 20.925 15.12 21.195 ;
     RECT  2.16 21.465 15.12 21.735 ;
     RECT  2.16 22.005 15.12 22.275 ;
     RECT  2.16 22.545 15.12 22.815 ;
     RECT  2.16 23.085 15.12 23.355 ;
     RECT  2.16 23.625 15.12 23.895 ;
     RECT  2.16 24.165 15.12 24.435 ;
     RECT  2.16 24.705 15.12 24.975 ;
     RECT  2.16 25.245 15.12 25.515 ;
     RECT  2.16 25.785 15.12 26.055 ;
     RECT  2.16 26.325 15.12 26.595 ;
     RECT  2.16 26.865 15.12 27.135 ;
     RECT  2.16 27.405 15.12 27.675 ;
     RECT  2.16 27.945 15.12 28.215 ;
     RECT  2.16 28.485 15.12 28.755 ;
     RECT  2.16 29.025 15.12 29.295 ;
     RECT  2.16 29.565 15.12 29.835 ;
     RECT  2.16 30.105 15.12 30.375 ;
     RECT  2.16 30.645 15.12 30.915 ;
     RECT  2.16 31.185 15.12 31.455 ;
     RECT  2.16 31.725 15.12 31.995 ;
     RECT  2.16 32.265 15.12 32.535 ;
     RECT  2.16 32.805 15.12 33.075 ;
     RECT  2.16 33.345 15.12 33.615 ;
     RECT  2.16 33.885 15.12 34.155 ;
     RECT  2.16 34.425 15.12 34.695 ;
     RECT  2.16 34.965 15.12 35.235 ;
     RECT  2.16 35.505 15.12 35.775 ;
     RECT  2.16 36.045 15.12 36.315 ;
     RECT  2.16 36.585 15.12 36.855 ;
     RECT  2.16 37.125 15.12 37.395 ;
     RECT  2.16 37.665 15.12 37.935 ;
     RECT  2.16 38.205 15.12 38.475 ;
     RECT  2.16 38.745 15.12 39.015 ;
     RECT  2.16 39.285 15.12 39.555 ;
     RECT  2.16 39.825 15.12 40.095 ;
     RECT  2.16 40.365 15.12 40.635 ;
     RECT  2.16 40.905 15.12 41.175 ;
     RECT  2.16 41.445 15.12 41.715 ;
     RECT  2.16 41.985 15.12 42.255 ;
     RECT  2.16 42.525 15.12 42.795 ;
     RECT  2.16 43.065 15.12 43.335 ;
     RECT  2.16 43.605 15.12 43.875 ;
     RECT  2.16 44.145 15.12 44.415 ;
     RECT  2.16 44.685 15.12 44.955 ;
     RECT  2.16 45.225 15.12 45.495 ;
     RECT  2.16 45.765 15.12 46.035 ;
     RECT  2.16 46.305 15.12 46.575 ;
     RECT  2.16 46.845 15.12 47.115 ;
     RECT  2.16 47.385 15.12 47.655 ;
     RECT  2.16 47.925 15.12 48.195 ;
     RECT  2.16 48.465 15.12 48.735 ;
     RECT  2.16 49.005 15.12 49.275 ;
     RECT  2.16 49.545 15.12 49.815 ;
     RECT  2.16 50.085 15.12 50.355 ;
     RECT  2.16 50.625 15.12 50.895 ;
     RECT  2.16 51.165 15.12 51.435 ;
     RECT  2.16 51.705 15.12 51.975 ;
     RECT  2.16 52.245 15.12 52.515 ;
     RECT  2.16 52.785 15.12 53.055 ;
     RECT  2.16 53.325 15.12 53.595 ;
     RECT  2.16 53.865 15.12 54.135 ;
     RECT  2.16 54.405 15.12 54.675 ;
     RECT  2.16 54.945 15.12 55.215 ;
     RECT  2.16 55.485 15.12 55.755 ;
     RECT  2.16 56.025 15.12 56.295 ;
     RECT  2.16 56.565 15.12 56.835 ;
     RECT  2.16 57.105 15.12 57.375 ;
     RECT  2.16 57.645 15.12 57.915 ;
     RECT  2.16 58.185 15.12 58.455 ;
     RECT  2.16 58.725 15.12 58.995 ;
     RECT  2.16 59.265 15.12 59.535 ;
     RECT  2.16 59.805 15.12 60.075 ;
     RECT  2.16 60.345 15.12 60.615 ;
     RECT  2.16 60.885 15.12 61.155 ;
     RECT  2.16 61.425 15.12 61.695 ;
     RECT  2.16 61.965 15.12 62.235 ;
     RECT  2.16 62.505 15.12 62.64 ;
    LAYER RVTP ;
     RECT  2.16 2.295 15.12 2.565 ;
     RECT  2.16 2.835 15.12 3.105 ;
     RECT  2.16 3.375 15.12 3.645 ;
     RECT  2.16 3.915 15.12 4.185 ;
     RECT  2.16 4.455 15.12 4.725 ;
     RECT  2.16 4.995 15.12 5.265 ;
     RECT  2.16 5.535 15.12 5.805 ;
     RECT  2.16 6.075 15.12 6.345 ;
     RECT  2.16 6.615 15.12 6.885 ;
     RECT  2.16 7.155 15.12 7.425 ;
     RECT  2.16 7.695 15.12 7.965 ;
     RECT  2.16 8.235 15.12 8.505 ;
     RECT  2.16 8.775 15.12 9.045 ;
     RECT  2.16 9.315 15.12 9.585 ;
     RECT  2.16 9.855 15.12 10.125 ;
     RECT  2.16 10.395 15.12 10.665 ;
     RECT  2.16 10.935 15.12 11.205 ;
     RECT  2.16 11.475 15.12 11.745 ;
     RECT  2.16 12.015 15.12 12.285 ;
     RECT  2.16 12.555 15.12 12.825 ;
     RECT  2.16 13.095 15.12 13.365 ;
     RECT  2.16 13.635 15.12 13.905 ;
     RECT  2.16 14.175 15.12 14.445 ;
     RECT  2.16 14.715 15.12 14.985 ;
     RECT  2.16 15.255 15.12 15.525 ;
     RECT  2.16 15.795 15.12 16.065 ;
     RECT  2.16 16.335 15.12 16.605 ;
     RECT  2.16 16.875 15.12 17.145 ;
     RECT  2.16 17.415 15.12 17.685 ;
     RECT  2.16 17.955 15.12 18.225 ;
     RECT  2.16 18.495 15.12 18.765 ;
     RECT  2.16 19.035 15.12 19.305 ;
     RECT  2.16 19.575 15.12 19.845 ;
     RECT  2.16 20.115 15.12 20.385 ;
     RECT  2.16 20.655 15.12 20.925 ;
     RECT  2.16 21.195 15.12 21.465 ;
     RECT  2.16 21.735 15.12 22.005 ;
     RECT  2.16 22.275 15.12 22.545 ;
     RECT  2.16 22.815 15.12 23.085 ;
     RECT  2.16 23.355 15.12 23.625 ;
     RECT  2.16 23.895 15.12 24.165 ;
     RECT  2.16 24.435 15.12 24.705 ;
     RECT  2.16 24.975 15.12 25.245 ;
     RECT  2.16 25.515 15.12 25.785 ;
     RECT  2.16 26.055 15.12 26.325 ;
     RECT  2.16 26.595 15.12 26.865 ;
     RECT  2.16 27.135 15.12 27.405 ;
     RECT  2.16 27.675 15.12 27.945 ;
     RECT  2.16 28.215 15.12 28.485 ;
     RECT  2.16 28.755 15.12 29.025 ;
     RECT  2.16 29.295 15.12 29.565 ;
     RECT  2.16 29.835 15.12 30.105 ;
     RECT  2.16 30.375 15.12 30.645 ;
     RECT  2.16 30.915 15.12 31.185 ;
     RECT  2.16 31.455 15.12 31.725 ;
     RECT  2.16 31.995 15.12 32.265 ;
     RECT  2.16 32.535 15.12 32.805 ;
     RECT  2.16 33.075 15.12 33.345 ;
     RECT  2.16 33.615 15.12 33.885 ;
     RECT  2.16 34.155 15.12 34.425 ;
     RECT  2.16 34.695 15.12 34.965 ;
     RECT  2.16 35.235 15.12 35.505 ;
     RECT  2.16 35.775 15.12 36.045 ;
     RECT  2.16 36.315 15.12 36.585 ;
     RECT  2.16 36.855 15.12 37.125 ;
     RECT  2.16 37.395 15.12 37.665 ;
     RECT  2.16 37.935 15.12 38.205 ;
     RECT  2.16 38.475 15.12 38.745 ;
     RECT  2.16 39.015 15.12 39.285 ;
     RECT  2.16 39.555 15.12 39.825 ;
     RECT  2.16 40.095 15.12 40.365 ;
     RECT  2.16 40.635 15.12 40.905 ;
     RECT  2.16 41.175 15.12 41.445 ;
     RECT  2.16 41.715 15.12 41.985 ;
     RECT  2.16 42.255 15.12 42.525 ;
     RECT  2.16 42.795 15.12 43.065 ;
     RECT  2.16 43.335 15.12 43.605 ;
     RECT  2.16 43.875 15.12 44.145 ;
     RECT  2.16 44.415 15.12 44.685 ;
     RECT  2.16 44.955 15.12 45.225 ;
     RECT  2.16 45.495 15.12 45.765 ;
     RECT  2.16 46.035 15.12 46.305 ;
     RECT  2.16 46.575 15.12 46.845 ;
     RECT  2.16 47.115 15.12 47.385 ;
     RECT  2.16 47.655 15.12 47.925 ;
     RECT  2.16 48.195 15.12 48.465 ;
     RECT  2.16 48.735 15.12 49.005 ;
     RECT  2.16 49.275 15.12 49.545 ;
     RECT  2.16 49.815 15.12 50.085 ;
     RECT  2.16 50.355 15.12 50.625 ;
     RECT  2.16 50.895 15.12 51.165 ;
     RECT  2.16 51.435 15.12 51.705 ;
     RECT  2.16 51.975 15.12 52.245 ;
     RECT  2.16 52.515 15.12 52.785 ;
     RECT  2.16 53.055 15.12 53.325 ;
     RECT  2.16 53.595 15.12 53.865 ;
     RECT  2.16 54.135 15.12 54.405 ;
     RECT  2.16 54.675 15.12 54.945 ;
     RECT  2.16 55.215 15.12 55.485 ;
     RECT  2.16 55.755 15.12 56.025 ;
     RECT  2.16 56.295 15.12 56.565 ;
     RECT  2.16 56.835 15.12 57.105 ;
     RECT  2.16 57.375 15.12 57.645 ;
     RECT  2.16 57.915 15.12 58.185 ;
     RECT  2.16 58.455 15.12 58.725 ;
     RECT  2.16 58.995 15.12 59.265 ;
     RECT  2.16 59.535 15.12 59.805 ;
     RECT  2.16 60.075 15.12 60.345 ;
     RECT  2.16 60.615 15.12 60.885 ;
     RECT  2.16 61.155 15.12 61.425 ;
     RECT  2.16 61.695 15.12 61.965 ;
     RECT  2.16 62.235 15.12 62.505 ;
    LAYER M1 ;
     RECT  2.16 2.151 15.12 62.649 ;
    LAYER M2 ;
     RECT  0.031 22.014 0.103 22.032 ;
     RECT  0.067 27.486 0.103 27.504 ;
     RECT  0.031 30.618 0.103 30.636 ;
     RECT  0.031 31.536 0.103 31.554 ;
     RECT  0.103 6.012 0.139 6.03 ;
     RECT  0.103 9.09 0.139 9.306 ;
     RECT  0.103 20.934 0.139 22.608 ;
     RECT  0.103 24.831 0.139 24.966 ;
     RECT  0.031 25.758 0.139 25.776 ;
     RECT  0.103 29.034 0.139 31.554 ;
     RECT  0.103 32.31 0.139 32.328 ;
     RECT  0.103 33.39 0.139 33.912 ;
     RECT  0.103 38.142 0.139 38.16 ;
     RECT  0.103 39.06 0.139 39.618 ;
     RECT  0.103 47.43 0.139 47.448 ;
     RECT  0.103 27.486 0.167 27.9 ;
     RECT  0.139 17.694 0.175 17.712 ;
     RECT  0.139 29.034 0.175 33.912 ;
     RECT  0.103 34.74 0.175 34.758 ;
     RECT  0.139 54.612 0.175 54.63 ;
     RECT  0.103 7.902 0.211 7.92 ;
     RECT  0.175 17.694 0.211 17.784 ;
     RECT  0.175 19.62 0.211 19.638 ;
     RECT  0.167 27.684 0.211 27.9 ;
     RECT  0.175 54.612 0.211 54.666 ;
     RECT  0.139 6.012 0.247 6.678 ;
     RECT  0.211 7.74 0.247 7.92 ;
     RECT  0.139 20.43 0.247 22.608 ;
     RECT  0.103 49.554 0.247 50.148 ;
     RECT  0.103 14.22 0.283 14.238 ;
     RECT  0.247 20.43 0.283 22.644 ;
     RECT  0.067 23.67 0.283 23.688 ;
     RECT  0.103 42.066 0.347 42.75 ;
     RECT  0.283 20.43 0.355 23.688 ;
     RECT  0.139 24.831 0.355 25.776 ;
     RECT  0.355 20.43 0.419 25.776 ;
     RECT  0.211 27.684 0.427 28.206 ;
     RECT  0.175 29.034 0.427 34.758 ;
     RECT  0.211 19.35 0.499 19.638 ;
     RECT  0.419 20.43 0.499 24.228 ;
     RECT  0.139 8.82 0.535 9.306 ;
     RECT  0.103 15.84 0.535 15.858 ;
     RECT  0.419 25.056 0.535 25.776 ;
     RECT  0.139 38.142 0.535 39.618 ;
     RECT  0.247 49.482 0.535 50.148 ;
     RECT  0.139 56.304 0.599 56.322 ;
     RECT  0.427 27.684 0.895 34.758 ;
     RECT  0.247 6.012 1.147 7.92 ;
     RECT  0.535 25.056 1.147 25.848 ;
     RECT  0.895 27.072 1.147 34.758 ;
     RECT  0.103 45.54 1.147 46.134 ;
     RECT  0.499 19.35 1.211 24.228 ;
     RECT  1.147 6.012 1.687 7.956 ;
     RECT  0.571 57.582 1.723 57.6 ;
     RECT  0.103 58.662 1.723 58.68 ;
     RECT  1.723 58.662 1.759 58.716 ;
     RECT  1.759 58.392 1.795 58.716 ;
     RECT  0.211 59.472 1.795 59.49 ;
     RECT  0.211 54.612 1.975 54.972 ;
     RECT  1.975 54.612 2.047 55.008 ;
     RECT  1.687 5.85 2.16 7.956 ;
     RECT  0.535 8.82 2.16 9.612 ;
     RECT  0.103 12.528 2.16 13.392 ;
     RECT  0.283 14.22 2.16 14.508 ;
     RECT  0.535 15.336 2.16 15.858 ;
     RECT  1.723 16.65 2.16 16.668 ;
     RECT  0.211 17.46 2.16 17.784 ;
     RECT  1.211 19.35 2.16 24.156 ;
     RECT  1.147 25.056 2.16 34.758 ;
     RECT  0.535 36.054 2.16 36.072 ;
     RECT  0.535 37.476 2.16 39.888 ;
     RECT  0.347 42.732 2.16 42.75 ;
     RECT  1.147 45.54 2.16 46.26 ;
     RECT  0.139 47.43 2.16 47.88 ;
     RECT  0.535 48.816 2.16 50.148 ;
     RECT  2.047 54.612 2.16 55.242 ;
     RECT  1.723 57.312 2.16 57.6 ;
     RECT  1.795 58.392 2.16 59.49 ;
     RECT  2.16 2.151 15.12 62.649 ;
     RECT  15.12 4.536 15.719 60.408 ;
     RECT  15.719 4.536 15.791 60.336 ;
     RECT  15.791 4.536 16.007 60.066 ;
     RECT  16.007 4.968 16.043 60.066 ;
     RECT  16.043 4.968 16.079 7.524 ;
     RECT  16.043 8.316 16.259 60.066 ;
     RECT  16.259 8.316 16.475 59.994 ;
     RECT  16.079 5.076 16.511 7.524 ;
     RECT  16.475 8.316 16.511 18.414 ;
     RECT  16.475 19.206 16.511 42.624 ;
     RECT  16.475 43.506 16.511 56.124 ;
     RECT  16.511 8.316 16.547 15.174 ;
     RECT  16.511 21.474 16.547 22.23 ;
     RECT  16.511 23.058 16.547 27.054 ;
     RECT  16.511 31.356 16.547 35.694 ;
     RECT  16.511 42.336 16.547 42.624 ;
     RECT  16.511 5.076 16.583 7.182 ;
     RECT  16.547 11.646 16.583 15.174 ;
     RECT  16.511 16.038 16.583 18.414 ;
     RECT  16.547 31.356 16.583 35.496 ;
     RECT  16.583 6.858 16.619 7.182 ;
     RECT  16.583 12.951 16.655 15.174 ;
     RECT  16.583 11.646 16.691 12.204 ;
     RECT  16.655 12.951 16.691 13.086 ;
     RECT  16.619 6.858 16.727 6.876 ;
     RECT  16.475 56.916 16.871 59.994 ;
     RECT  16.871 56.916 16.907 59.796 ;
     RECT  16.907 56.916 16.943 59.724 ;
     RECT  16.943 56.916 16.979 59.328 ;
     RECT  16.511 50.526 17.015 56.124 ;
     RECT  16.979 57.276 17.015 59.328 ;
     RECT  17.015 50.526 17.087 56.052 ;
     RECT  17.015 57.276 17.087 59.094 ;
     RECT  16.547 8.316 17.123 10.854 ;
     RECT  16.583 16.038 17.123 16.056 ;
     RECT  16.583 17.046 17.123 18.414 ;
     RECT  16.511 19.584 17.123 20.574 ;
     RECT  16.511 37.602 17.123 41.094 ;
     RECT  16.511 46.386 17.123 47.574 ;
     RECT  17.087 50.526 17.123 53.244 ;
     RECT  17.087 57.276 17.123 57.672 ;
     RECT  16.583 5.076 17.159 6.102 ;
     RECT  17.123 8.676 17.159 10.854 ;
     RECT  16.691 11.646 17.159 11.934 ;
     RECT  16.691 12.951 17.159 12.969 ;
     RECT  16.655 14.346 17.159 15.174 ;
     RECT  17.123 18.036 17.159 18.414 ;
     RECT  17.123 19.926 17.159 20.574 ;
     RECT  16.511 29.196 17.159 30.294 ;
     RECT  16.583 32.166 17.159 35.496 ;
     RECT  17.123 38.178 17.159 41.094 ;
     RECT  16.511 43.506 17.159 45.486 ;
     RECT  17.123 46.386 17.159 47.304 ;
     RECT  17.123 50.904 17.159 52.776 ;
     RECT  17.087 54.306 17.159 55.476 ;
     RECT  17.123 57.276 17.159 57.366 ;
     RECT  17.159 6.084 17.195 6.102 ;
     RECT  17.159 8.676 17.195 9.108 ;
     RECT  17.159 10.206 17.195 10.854 ;
     RECT  17.159 11.646 17.195 11.772 ;
     RECT  17.159 14.616 17.195 15.174 ;
     RECT  17.159 18.396 17.195 18.414 ;
     RECT  17.159 20.556 17.195 20.574 ;
     RECT  16.547 22.212 17.195 22.23 ;
     RECT  16.547 23.436 17.195 23.454 ;
     RECT  16.547 24.48 17.195 27.054 ;
     RECT  16.511 28.188 17.195 28.206 ;
     RECT  17.159 29.196 17.195 29.628 ;
     RECT  16.583 31.356 17.195 31.374 ;
     RECT  17.159 32.436 17.195 32.454 ;
     RECT  17.159 33.786 17.195 34.524 ;
     RECT  17.159 35.478 17.195 35.496 ;
     RECT  17.159 39.06 17.195 39.474 ;
     RECT  17.159 40.266 17.195 41.094 ;
     RECT  17.159 43.686 17.195 44.784 ;
     RECT  17.159 47.286 17.195 47.304 ;
     RECT  17.159 50.904 17.195 51.624 ;
     RECT  17.159 52.758 17.195 52.776 ;
     RECT  17.159 54.531 17.195 55.476 ;
     RECT  17.195 54.846 17.231 55.476 ;
     RECT  17.159 57.348 17.231 57.366 ;
     RECT  17.159 5.076 17.267 5.094 ;
     RECT  17.195 8.946 17.267 8.964 ;
     RECT  17.159 38.178 17.267 38.196 ;
     RECT  17.195 40.878 17.267 40.896 ;
     RECT  16.547 42.606 17.267 42.624 ;
     RECT  17.195 44.766 17.267 44.784 ;
     RECT  17.195 51.606 17.267 51.624 ;
     RECT  17.231 54.846 17.267 54.864 ;
    LAYER M3 ;
     RECT  2.415 2.143 2.505 2.413 ;
     RECT  7.815 2.143 7.905 2.413 ;
     RECT  13.215 2.143 13.305 2.413 ;
     RECT  13.215 2.413 13.497 4.495 ;
     RECT  14.472 4.351 14.49 4.495 ;
     RECT  13.215 4.495 14.49 4.801 ;
     RECT  13.215 4.801 14.994 4.891 ;
     RECT  15.984 4.531 16.002 4.963 ;
     RECT  12.6 4.891 14.994 5.035 ;
     RECT  5.4 5.035 5.418 5.071 ;
     RECT  15.984 4.963 16.074 5.233 ;
     RECT  17.244 5.071 17.262 5.233 ;
     RECT  5.4 5.071 5.85 5.305 ;
     RECT  2.415 2.413 2.697 5.341 ;
     RECT  5.4 5.305 6.21 5.341 ;
     RECT  12.456 5.035 14.994 5.341 ;
     RECT  15.984 5.233 17.262 5.341 ;
     RECT  4.896 5.341 6.822 5.467 ;
     RECT  10.476 5.341 10.494 5.467 ;
     RECT  2.415 5.341 3.006 5.575 ;
     RECT  12.456 5.341 17.262 5.575 ;
     RECT  4.392 5.467 6.822 5.605 ;
     RECT  7.815 2.413 8.097 5.605 ;
     RECT  2.415 5.575 3.618 5.611 ;
     RECT  4.392 5.605 8.097 5.611 ;
     RECT  2.415 5.611 8.097 5.737 ;
     RECT  2.304 5.737 8.097 5.845 ;
     RECT  10.116 5.467 10.494 5.881 ;
     RECT  11.7 5.575 17.262 5.881 ;
     RECT  1.692 5.845 8.097 5.971 ;
     RECT  9.18 5.881 9.198 6.091 ;
     RECT  1.692 5.971 8.154 6.151 ;
     RECT  9.18 6.091 9.234 6.151 ;
     RECT  10.116 5.881 17.262 6.151 ;
     RECT  1.692 6.151 9.234 6.235 ;
     RECT  1.692 6.235 9.27 6.241 ;
     RECT  10.008 6.151 17.262 6.241 ;
     RECT  1.692 6.241 17.262 6.277 ;
     RECT  0.108 6.007 0.126 6.385 ;
     RECT  1.152 6.277 17.262 6.413 ;
     RECT  0.108 6.385 0.198 7.357 ;
     RECT  1.692 6.413 17.262 7.933 ;
     RECT  1.152 7.933 17.262 8.525 ;
     RECT  2.304 8.525 17.262 8.879 ;
     RECT  15.984 8.879 17.262 8.969 ;
     RECT  2.304 8.879 14.994 9.581 ;
     RECT  0.108 7.357 0.27 9.589 ;
     RECT  1.152 8.525 1.17 9.589 ;
     RECT  2.304 9.581 14.958 9.739 ;
     RECT  0.108 9.589 1.17 9.869 ;
     RECT  2.268 9.739 14.958 9.887 ;
     RECT  0.54 9.869 1.17 9.965 ;
     RECT  0.54 9.965 0.558 10.157 ;
     RECT  15.984 8.969 17.19 10.253 ;
     RECT  16.02 10.253 17.19 11.083 ;
     RECT  15.984 11.083 17.19 11.563 ;
     RECT  0.144 11.419 0.162 11.597 ;
     RECT  2.304 9.887 14.958 11.677 ;
     RECT  2.196 11.677 14.958 11.713 ;
     RECT  15.84 11.563 17.19 11.713 ;
     RECT  2.196 11.713 17.19 11.741 ;
     RECT  2.304 11.741 17.19 11.789 ;
     RECT  2.304 11.789 17.154 11.939 ;
     RECT  2.304 11.939 16.686 12.845 ;
     RECT  15.84 12.845 16.686 12.857 ;
     RECT  0.108 12.523 0.126 12.859 ;
     RECT  15.948 12.857 16.686 12.929 ;
     RECT  16.02 12.929 16.686 12.946 ;
     RECT  0.108 12.859 0.162 13.037 ;
     RECT  16.02 12.946 17.154 13.037 ;
     RECT  16.452 13.037 17.154 13.963 ;
     RECT  2.304 12.845 14.922 14.059 ;
     RECT  16.452 13.963 17.19 14.347 ;
     RECT  15.984 14.347 17.19 14.443 ;
     RECT  0.108 13.037 0.126 14.485 ;
     RECT  15.84 14.443 17.19 14.783 ;
     RECT  0.108 14.485 0.306 14.861 ;
     RECT  0.288 14.861 0.306 15.115 ;
     RECT  0.288 15.115 0.342 15.331 ;
     RECT  2.268 14.059 14.922 15.601 ;
     RECT  2.268 15.601 14.994 15.691 ;
     RECT  0.288 15.331 0.558 15.835 ;
     RECT  0.108 15.835 0.558 16.109 ;
     RECT  2.232 15.691 14.994 16.375 ;
     RECT  15.912 14.783 17.19 16.375 ;
     RECT  1.44 16.459 1.458 16.645 ;
     RECT  2.232 16.375 17.19 16.645 ;
     RECT  0.108 16.109 0.162 16.939 ;
     RECT  1.44 16.645 17.19 16.939 ;
     RECT  0.108 16.939 17.19 16.973 ;
     RECT  0.108 16.973 15.174 17.024 ;
     RECT  0.108 17.024 15.066 17.069 ;
     RECT  15.912 16.973 17.19 17.411 ;
     RECT  0.108 17.069 14.994 17.549 ;
     RECT  0.108 17.549 14.922 18.029 ;
     RECT  15.984 17.411 17.19 18.379 ;
     RECT  15.948 18.379 17.19 18.419 ;
     RECT  15.948 18.419 16.506 18.463 ;
     RECT  0.108 18.029 14.742 18.76 ;
     RECT  0.108 18.76 14.778 18.769 ;
     RECT  15.912 18.463 16.506 19.139 ;
     RECT  0.108 18.769 14.922 19.535 ;
     RECT  15.948 19.139 16.506 19.579 ;
     RECT  15.948 19.579 17.118 19.921 ;
     RECT  0.108 19.535 14.778 19.949 ;
     RECT  15.948 19.921 17.154 20.011 ;
     RECT  15.84 20.011 17.154 20.107 ;
     RECT  0.144 19.949 14.778 20.281 ;
     RECT  0.144 20.281 14.85 20.425 ;
     RECT  15.84 20.107 17.19 20.579 ;
     RECT  0.144 20.425 14.994 20.659 ;
     RECT  15.84 20.579 16.506 20.659 ;
     RECT  0.144 20.659 16.506 20.929 ;
     RECT  0.108 20.929 16.506 21.355 ;
     RECT  0.108 21.355 16.542 22.009 ;
     RECT  0.036 22.009 16.542 22.207 ;
     RECT  0.036 22.207 17.19 22.253 ;
     RECT  15.948 22.253 17.19 22.445 ;
     RECT  15.948 22.445 17.118 22.685 ;
     RECT  0.036 22.253 14.994 22.811 ;
     RECT  9.72 22.811 14.994 22.925 ;
     RECT  15.948 22.685 16.542 23.431 ;
     RECT  15.948 23.431 17.19 23.501 ;
     RECT  9.72 22.925 14.922 23.549 ;
     RECT  0.036 22.811 8.982 23.665 ;
     RECT  9.72 23.549 14.706 23.665 ;
     RECT  15.948 23.501 16.542 23.701 ;
     RECT  15.912 23.701 16.542 24.475 ;
     RECT  15.912 24.475 17.19 24.619 ;
     RECT  0.036 23.665 14.706 24.709 ;
     RECT  0.036 24.709 14.886 24.781 ;
     RECT  0.036 24.781 14.994 24.845 ;
     RECT  0.036 24.845 14.922 25.675 ;
     RECT  15.84 24.619 17.19 25.675 ;
     RECT  0.036 25.675 17.19 25.781 ;
     RECT  0.072 25.781 17.19 26.237 ;
     RECT  0.072 26.237 14.922 27.019 ;
     RECT  15.948 26.237 17.19 27.019 ;
     RECT  0.072 27.019 17.19 27.509 ;
     RECT  0.108 27.509 17.19 28.211 ;
     RECT  0.108 28.211 16.506 28.517 ;
     RECT  15.372 28.517 16.506 28.589 ;
     RECT  15.552 28.589 16.506 28.939 ;
     RECT  0.108 28.517 14.634 29.255 ;
     RECT  0.108 29.255 0.882 29.327 ;
     RECT  1.98 29.255 14.634 29.605 ;
     RECT  15.552 28.939 17.19 29.831 ;
     RECT  1.98 29.605 14.778 29.911 ;
     RECT  0.108 29.327 0.846 30.335 ;
     RECT  1.98 29.911 14.994 30.371 ;
     RECT  15.984 29.831 17.19 30.371 ;
     RECT  0.108 30.335 0.558 30.413 ;
     RECT  0.108 30.413 0.234 30.613 ;
     RECT  2.268 30.371 14.994 30.839 ;
     RECT  0.036 30.613 0.234 30.989 ;
     RECT  16.416 30.371 17.19 31.085 ;
     RECT  2.268 30.839 14.922 31.451 ;
     RECT  0.036 30.989 0.198 31.559 ;
     RECT  16.452 31.085 17.19 31.915 ;
     RECT  2.268 31.451 14.814 31.955 ;
     RECT  15.948 31.915 17.19 32.107 ;
     RECT  15.912 32.107 17.19 32.459 ;
     RECT  15.912 32.459 17.154 32.491 ;
     RECT  0.108 31.559 0.198 32.587 ;
     RECT  15.876 32.491 17.154 32.587 ;
     RECT  0.108 32.587 0.342 32.621 ;
     RECT  0.144 32.621 0.342 32.717 ;
     RECT  2.304 31.955 14.814 32.779 ;
     RECT  15.84 32.587 17.154 32.779 ;
     RECT  2.304 32.779 17.154 33.005 ;
     RECT  0.144 32.717 0.198 33.197 ;
     RECT  15.876 33.005 17.154 33.377 ;
     RECT  0.144 33.197 0.162 33.385 ;
     RECT  2.304 33.005 14.922 33.451 ;
     RECT  16.38 33.377 17.154 33.485 ;
     RECT  16.452 33.485 17.154 33.547 ;
     RECT  2.268 33.451 14.922 33.931 ;
     RECT  2.268 33.931 15.39 34.061 ;
     RECT  0.108 33.385 0.162 34.156 ;
     RECT  2.304 34.061 15.39 34.315 ;
     RECT  16.452 33.547 17.19 34.315 ;
     RECT  0.108 34.156 0.198 34.445 ;
     RECT  2.304 34.315 17.19 34.529 ;
     RECT  0.108 34.445 0.126 34.925 ;
     RECT  2.304 34.529 17.154 35.005 ;
     RECT  2.268 35.005 17.154 35.371 ;
     RECT  2.268 35.371 17.19 35.501 ;
     RECT  2.268 35.501 16.542 35.699 ;
     RECT  2.268 35.699 16.506 35.707 ;
     RECT  2.232 35.707 16.506 35.885 ;
     RECT  0.54 36.049 0.558 36.331 ;
     RECT  0.36 36.331 0.558 36.379 ;
     RECT  0.144 36.379 0.558 36.557 ;
     RECT  2.304 35.885 16.506 36.689 ;
     RECT  15.912 36.689 16.506 36.907 ;
     RECT  2.304 36.689 14.922 37.291 ;
     RECT  2.268 37.291 14.922 37.579 ;
     RECT  15.912 36.907 17.19 37.579 ;
     RECT  0.54 36.557 0.558 37.709 ;
     RECT  2.268 37.579 17.19 37.769 ;
     RECT  2.268 37.769 14.886 38.039 ;
     RECT  0.324 38.059 0.342 38.137 ;
     RECT  15.912 37.769 17.19 38.173 ;
     RECT  15.912 38.173 17.262 38.471 ;
     RECT  0.108 38.137 0.342 38.551 ;
     RECT  2.304 38.039 14.886 38.551 ;
     RECT  15.948 38.471 17.262 38.669 ;
     RECT  0.108 38.551 0.558 39.101 ;
     RECT  2.304 38.551 14.922 39.451 ;
     RECT  15.948 38.669 15.966 39.499 ;
     RECT  2.268 39.451 14.922 39.515 ;
     RECT  15.948 39.499 16.002 39.595 ;
     RECT  16.992 38.669 17.262 39.595 ;
     RECT  2.304 39.515 14.922 39.829 ;
     RECT  15.948 39.595 17.262 39.829 ;
     RECT  0.108 39.101 0.198 39.865 ;
     RECT  0.108 39.865 0.558 39.917 ;
     RECT  0.108 39.917 0.342 40.109 ;
     RECT  2.304 39.829 17.262 40.361 ;
     RECT  0.18 40.109 0.306 40.397 ;
     RECT  16.452 40.361 17.262 40.901 ;
     RECT  16.452 40.901 17.19 41.099 ;
     RECT  2.304 40.361 15.462 41.143 ;
     RECT  16.452 41.099 17.118 41.143 ;
     RECT  2.304 41.143 17.118 41.515 ;
     RECT  0.144 41.179 0.162 41.899 ;
     RECT  0.144 41.899 0.342 41.995 ;
     RECT  0.108 41.995 0.342 42.221 ;
     RECT  2.268 41.515 17.118 42.317 ;
     RECT  0.108 42.221 0.162 42.365 ;
     RECT  2.268 42.317 14.85 42.457 ;
     RECT  2.232 42.457 14.85 42.557 ;
     RECT  15.948 42.317 17.118 42.571 ;
     RECT  15.948 42.571 17.19 42.601 ;
     RECT  0.108 42.365 0.126 42.797 ;
     RECT  0.216 43.147 0.234 43.325 ;
     RECT  2.268 42.557 14.85 43.573 ;
     RECT  15.948 42.601 17.262 43.573 ;
     RECT  2.268 43.573 17.262 43.661 ;
     RECT  2.268 43.661 15.174 43.757 ;
     RECT  15.948 43.661 17.262 44.045 ;
     RECT  2.304 43.757 14.922 44.339 ;
     RECT  0.144 44.155 0.162 44.587 ;
     RECT  16.452 44.045 17.262 44.779 ;
     RECT  15.948 44.779 17.262 44.789 ;
     RECT  0.108 44.587 0.162 45.053 ;
     RECT  15.948 44.789 17.19 45.059 ;
     RECT  2.304 44.339 14.85 45.571 ;
     RECT  0.108 45.053 0.126 45.787 ;
     RECT  16.02 45.059 17.19 45.797 ;
     RECT  0.108 45.787 0.162 45.805 ;
     RECT  1.152 44.395 1.17 45.805 ;
     RECT  2.304 45.571 14.994 45.835 ;
     RECT  2.268 45.835 14.994 46.027 ;
     RECT  0.108 45.805 1.17 46.265 ;
     RECT  2.268 46.027 15.462 46.349 ;
     RECT  0.108 46.265 0.558 46.637 ;
     RECT  16.38 45.797 17.19 46.651 ;
     RECT  2.268 46.349 14.994 47.077 ;
     RECT  15.984 46.651 17.19 47.077 ;
     RECT  2.268 47.077 17.19 47.147 ;
     RECT  2.304 47.147 17.19 47.309 ;
     RECT  0.108 46.637 0.126 47.563 ;
     RECT  2.304 47.309 17.118 47.579 ;
     RECT  0.108 47.563 0.342 47.693 ;
     RECT  0.108 47.693 0.162 47.981 ;
     RECT  0.144 47.981 0.162 48.461 ;
     RECT  2.304 47.579 16.506 48.461 ;
     RECT  0.324 48.619 0.342 48.749 ;
     RECT  0.54 48.811 0.558 49.003 ;
     RECT  0.54 49.003 1.17 49.229 ;
     RECT  15.66 48.461 16.506 49.387 ;
     RECT  15.66 49.387 17.154 49.483 ;
     RECT  0.252 49.477 0.27 49.549 ;
     RECT  1.152 49.229 1.17 49.577 ;
     RECT  0.108 49.549 0.27 49.963 ;
     RECT  2.304 48.461 14.922 50.059 ;
     RECT  15.66 49.483 17.19 50.059 ;
     RECT  2.304 50.059 17.19 50.395 ;
     RECT  0.108 49.963 0.342 50.573 ;
     RECT  2.268 50.395 17.19 50.585 ;
     RECT  0.108 50.573 0.126 50.765 ;
     RECT  0.144 51.307 0.342 51.437 ;
     RECT  2.304 50.585 17.19 51.601 ;
     RECT  2.304 51.601 17.262 51.787 ;
     RECT  2.268 51.787 17.262 51.883 ;
     RECT  2.232 51.883 17.262 51.971 ;
     RECT  2.232 51.971 14.958 52.205 ;
     RECT  2.268 52.205 14.958 52.547 ;
     RECT  2.304 52.547 14.958 52.939 ;
     RECT  15.876 51.971 17.262 52.939 ;
     RECT  0.144 51.437 0.162 53.261 ;
     RECT  2.304 52.939 17.262 53.371 ;
     RECT  0.324 53.419 0.342 53.549 ;
     RECT  2.232 53.371 17.262 53.995 ;
     RECT  2.052 53.995 17.262 54.091 ;
     RECT  0.108 54.571 0.126 54.607 ;
     RECT  0.108 54.607 0.162 54.643 ;
     RECT  1.98 54.091 17.262 54.869 ;
     RECT  0.108 54.643 0.198 54.949 ;
     RECT  0.108 54.949 0.234 55.373 ;
     RECT  1.98 54.869 17.226 55.723 ;
     RECT  0.108 55.373 0.126 56.107 ;
     RECT  0.108 56.107 0.45 56.299 ;
     RECT  1.728 55.723 17.226 57.371 ;
     RECT  0.108 56.299 0.594 57.605 ;
     RECT  1.728 57.371 17.118 57.677 ;
     RECT  1.728 57.677 17.082 57.739 ;
     RECT  1.152 57.739 17.082 57.965 ;
     RECT  1.728 57.965 17.082 58.649 ;
     RECT  0.108 57.605 0.234 58.685 ;
     RECT  1.728 58.649 9.486 58.721 ;
     RECT  10.224 58.649 17.082 58.757 ;
     RECT  1.8 58.721 9.486 58.919 ;
     RECT  10.26 58.757 17.082 58.919 ;
     RECT  10.404 58.919 14.958 58.955 ;
     RECT  15.696 58.919 17.082 59.099 ;
     RECT  1.8 58.919 9.342 59.189 ;
     RECT  1.8 59.189 8.55 59.225 ;
     RECT  1.872 59.225 8.55 59.261 ;
     RECT  9.324 59.189 9.342 59.309 ;
     RECT  15.696 59.099 17.01 59.333 ;
     RECT  2.304 59.261 8.55 59.369 ;
     RECT  2.304 59.369 6.57 59.459 ;
     RECT  7.344 59.369 8.55 59.459 ;
     RECT  0.216 58.685 0.234 59.495 ;
     RECT  7.596 59.459 8.097 59.495 ;
     RECT  2.304 59.459 6.462 59.639 ;
     RECT  2.304 59.639 4.374 59.729 ;
     RECT  5.256 59.639 6.462 59.729 ;
     RECT  15.696 59.333 16.938 59.729 ;
     RECT  2.304 59.729 4.302 59.765 ;
     RECT  10.728 58.955 14.958 59.765 ;
     RECT  15.696 59.729 16.902 59.801 ;
     RECT  2.376 59.765 4.302 59.837 ;
     RECT  11.232 59.765 14.958 59.837 ;
     RECT  3.78 59.837 4.302 59.909 ;
     RECT  5.256 59.729 5.85 59.909 ;
     RECT  12.168 59.837 14.958 59.909 ;
     RECT  2.376 59.837 2.934 59.999 ;
     RECT  3.96 59.909 4.302 59.999 ;
     RECT  5.256 59.909 5.274 59.999 ;
     RECT  11.232 59.837 11.394 59.999 ;
     RECT  12.168 59.909 14.886 59.999 ;
     RECT  15.696 59.801 16.866 59.999 ;
     RECT  3.96 59.999 4.086 60.035 ;
     RECT  12.204 59.999 14.886 60.071 ;
     RECT  15.696 59.999 16.254 60.071 ;
     RECT  12.204 60.071 14.85 60.143 ;
     RECT  12.348 60.143 14.85 60.179 ;
     RECT  2.376 59.999 2.754 60.269 ;
     RECT  3.96 60.035 3.978 60.269 ;
     RECT  12.348 60.179 12.402 60.269 ;
     RECT  13.215 60.179 14.85 60.269 ;
     RECT  12.384 60.269 12.402 60.305 ;
     RECT  13.215 60.269 14.814 60.305 ;
     RECT  15.696 60.071 15.786 60.341 ;
     RECT  14.436 60.305 14.814 60.413 ;
     RECT  15.696 60.341 15.714 60.413 ;
     RECT  14.796 60.413 14.814 60.419 ;
     RECT  2.415 60.269 2.697 62.387 ;
     RECT  7.815 59.495 8.097 62.387 ;
     RECT  13.215 60.305 13.497 62.387 ;
     RECT  2.415 62.387 2.505 62.657 ;
     RECT  7.815 62.387 7.905 62.657 ;
     RECT  13.215 62.387 13.305 62.657 ;
    LAYER M4 ;
     RECT  0.06 7.248 1.141 57.864 ;
     RECT  1.141 7.248 2.408 57.96 ;
     RECT  2.293 59.184 2.408 59.208 ;
     RECT  2.341 0.144 2.437 0.168 ;
     RECT  2.437 0.048 2.483 0.168 ;
     RECT  2.408 2.148 2.512 62.652 ;
     RECT  2.512 2.418 2.704 62.382 ;
     RECT  2.704 5.616 4.241 59.544 ;
     RECT  4.241 5.616 4.741 59.496 ;
     RECT  2.483 0.048 4.931 0.072 ;
     RECT  4.741 5.52 5.357 59.496 ;
     RECT  5.357 5.52 5.804 59.4 ;
     RECT  5.804 5.088 5.897 59.4 ;
     RECT  5.897 7.392 6.373 59.4 ;
     RECT  5.897 5.088 6.805 6.36 ;
     RECT  6.805 4.896 7.693 6.36 ;
     RECT  7.693 4.896 7.808 6.408 ;
     RECT  6.373 7.392 7.808 59.88 ;
     RECT  7.808 2.148 7.912 62.652 ;
     RECT  7.912 2.418 8.104 62.382 ;
     RECT  8.104 6.096 9.245 59.88 ;
     RECT  9.245 6.192 9.317 59.88 ;
     RECT  9.317 6.192 9.821 7.752 ;
     RECT  9.317 8.736 10.357 59.88 ;
     RECT  9.821 6.192 10.969 7.416 ;
     RECT  10.357 8.544 10.969 59.88 ;
     RECT  10.969 6.192 11.221 59.88 ;
     RECT  11.221 6.192 11.905 59.928 ;
     RECT  11.905 6 12.179 59.928 ;
     RECT  12.179 6 12.227 59.88 ;
     RECT  8.104 4.896 12.517 4.92 ;
     RECT  12.227 6 12.517 58.68 ;
     RECT  12.517 4.896 13.208 58.68 ;
     RECT  12.227 59.856 13.208 59.88 ;
     RECT  13.208 2.148 13.312 62.652 ;
     RECT  13.312 2.418 13.504 62.382 ;
     RECT  13.504 4.512 13.817 60.408 ;
     RECT  13.817 4.512 14.033 56.52 ;
     RECT  13.817 57.504 14.069 60.408 ;
     RECT  14.033 4.512 14.213 4.536 ;
     RECT  14.033 5.856 14.321 56.52 ;
     RECT  14.321 5.856 14.357 9.864 ;
     RECT  14.321 10.992 14.357 54.84 ;
     RECT  14.357 19.776 14.393 54.84 ;
     RECT  14.321 56.064 14.429 56.52 ;
     RECT  14.069 57.504 14.524 59.064 ;
     RECT  14.524 57.6 14.537 59.064 ;
     RECT  14.357 5.904 14.579 9.864 ;
     RECT  14.393 20.16 14.579 54.84 ;
     RECT  14.579 6.768 14.609 9.864 ;
     RECT  14.357 10.992 14.609 18.792 ;
     RECT  14.579 20.16 14.645 54.696 ;
     RECT  14.537 57.696 14.675 58.92 ;
     RECT  14.645 32.784 14.681 54.696 ;
     RECT  14.675 58.896 14.681 58.92 ;
     RECT  14.645 20.16 14.717 31.8 ;
     RECT  14.717 20.16 14.753 31.56 ;
     RECT  14.609 14.832 14.789 18.792 ;
     RECT  14.069 60.384 14.825 60.408 ;
     RECT  14.681 32.784 14.897 54.552 ;
     RECT  14.675 57.696 15.185 57.816 ;
     RECT  14.429 56.064 15.361 56.328 ;
     RECT  14.897 52.464 15.685 54.552 ;
     RECT  15.361 55.92 15.685 56.328 ;
     RECT  15.685 55.92 15.757 56.616 ;
     RECT  14.789 15.024 15.829 18.024 ;
     RECT  14.753 20.208 15.829 31.56 ;
     RECT  14.897 32.784 15.829 51.432 ;
     RECT  15.829 20.016 15.865 31.56 ;
     RECT  15.829 32.592 15.865 51.432 ;
     RECT  15.685 52.464 15.865 54.696 ;
     RECT  15.829 14.448 15.901 18.024 ;
     RECT  15.865 20.016 15.901 54.696 ;
     RECT  15.757 55.92 15.901 57.384 ;
     RECT  15.901 14.448 15.937 18.696 ;
     RECT  14.609 6.864 15.973 9.864 ;
     RECT  14.609 10.992 15.973 13.416 ;
     RECT  15.937 14.448 15.973 18.792 ;
     RECT  15.973 6.864 16.405 18.792 ;
     RECT  15.901 20.016 16.405 57.384 ;
     RECT  16.405 6.864 16.873 57.384 ;
     RECT  16.873 6.864 17.244 57.48 ;
    LAYER M5 ;
     RECT  2.4 2.137 2.52 2.151 ;
     RECT  7.8 2.137 7.92 2.151 ;
     RECT  13.2 2.137 13.32 2.151 ;
     RECT  13.2 2.151 13.512 4.501 ;
     RECT  7.8 2.151 8.112 4.885 ;
     RECT  13.2 4.501 13.608 5.029 ;
     RECT  4.896 0.037 4.92 5.077 ;
     RECT  6.816 4.885 8.112 5.077 ;
     RECT  13.2 5.029 13.656 5.077 ;
     RECT  4.896 5.077 8.112 5.509 ;
     RECT  4.752 5.509 8.112 5.653 ;
     RECT  13.104 5.077 13.656 5.893 ;
     RECT  13.104 5.893 14.568 5.989 ;
     RECT  3.792 5.653 8.112 6.181 ;
     RECT  3.792 6.181 8.664 6.229 ;
     RECT  10.032 6.181 10.056 6.565 ;
     RECT  10.032 6.565 10.824 7.333 ;
     RECT  2.4 2.151 2.712 7.381 ;
     RECT  3.792 6.229 8.952 7.381 ;
     RECT  10.032 7.333 11.352 7.381 ;
     RECT  2.4 7.381 11.352 8.579 ;
     RECT  12.432 5.989 14.568 8.579 ;
     RECT  11.328 8.579 11.352 9.397 ;
     RECT  11.328 9.397 11.448 9.637 ;
     RECT  12.432 8.579 14.184 9.637 ;
     RECT  2.4 8.579 10.248 10.117 ;
     RECT  11.328 9.637 14.184 10.117 ;
     RECT  2.4 10.117 14.184 10.307 ;
     RECT  2.4 10.307 13.656 11.365 ;
     RECT  2.4 11.365 14.472 11.459 ;
     RECT  2.4 11.459 10.248 11.557 ;
     RECT  0.192 11.509 0.216 11.701 ;
     RECT  0.144 11.701 0.216 12.467 ;
     RECT  0.192 12.467 0.216 12.469 ;
     RECT  11.28 11.459 14.472 12.515 ;
     RECT  2.304 11.557 10.248 12.517 ;
     RECT  11.28 12.515 11.688 12.517 ;
     RECT  2.304 12.517 11.688 12.611 ;
     RECT  12.672 12.515 14.472 13.139 ;
     RECT  0.192 12.469 0.264 13.285 ;
     RECT  0.192 13.285 0.312 14.003 ;
     RECT  2.4 12.611 11.688 14.005 ;
     RECT  12.672 13.139 14.04 14.005 ;
     RECT  0.192 14.003 0.216 14.101 ;
     RECT  2.4 14.005 14.04 14.629 ;
     RECT  2.4 14.629 14.28 14.677 ;
     RECT  0.144 14.101 0.216 15.443 ;
     RECT  2.304 14.677 14.28 16.595 ;
     RECT  0.144 15.443 0.168 17.365 ;
     RECT  0.144 17.365 0.264 19.045 ;
     RECT  0.144 19.045 0.312 19.573 ;
     RECT  0.144 19.573 0.552 20.339 ;
     RECT  15.36 20.197 15.384 20.437 ;
     RECT  15.312 20.437 15.384 21.155 ;
     RECT  0.144 20.339 0.168 21.397 ;
     RECT  0.144 21.397 0.408 21.539 ;
     RECT  0.144 21.539 0.312 21.683 ;
     RECT  15.312 21.155 15.336 21.683 ;
     RECT  0.144 21.683 0.168 21.779 ;
     RECT  2.304 16.595 14.232 21.829 ;
     RECT  2.304 21.829 14.76 22.693 ;
     RECT  0.24 22.741 0.264 23.125 ;
     RECT  2.304 22.693 14.808 23.411 ;
     RECT  0.144 23.125 0.264 24.085 ;
     RECT  0.144 24.085 0.36 24.277 ;
     RECT  2.304 23.411 14.232 24.659 ;
     RECT  0.144 24.277 0.408 24.661 ;
     RECT  2.304 24.659 13.656 25.187 ;
     RECT  2.4 25.187 13.656 26.197 ;
     RECT  2.4 26.197 13.8 26.629 ;
     RECT  0.144 24.661 0.552 26.675 ;
     RECT  2.304 26.629 13.8 26.915 ;
     RECT  2.4 26.915 13.8 27.301 ;
     RECT  14.784 24.805 14.808 27.301 ;
     RECT  0.144 26.675 0.456 27.443 ;
     RECT  2.4 27.301 14.808 27.877 ;
     RECT  0.192 27.443 0.456 28.019 ;
     RECT  2.4 27.877 15 28.405 ;
     RECT  2.304 28.405 15 29.221 ;
     RECT  0.192 28.019 0.408 29.363 ;
     RECT  0.192 29.363 0.312 29.557 ;
     RECT  0.144 29.557 0.312 30.515 ;
     RECT  2.304 29.221 15.384 30.803 ;
     RECT  2.304 30.803 15 30.995 ;
     RECT  2.304 30.995 14.808 31.283 ;
     RECT  0.144 30.515 0.264 31.379 ;
     RECT  2.304 31.283 14.712 31.571 ;
     RECT  0.144 31.379 0.216 32.243 ;
     RECT  0.192 32.243 0.216 33.253 ;
     RECT  0.192 33.253 0.312 33.589 ;
     RECT  0.144 33.589 0.312 33.925 ;
     RECT  0.144 33.925 0.36 34.547 ;
     RECT  0.192 34.547 0.36 34.837 ;
     RECT  2.304 31.571 14.472 34.837 ;
     RECT  2.304 34.837 14.808 34.931 ;
     RECT  14.784 34.931 14.808 35.075 ;
     RECT  2.304 34.931 13.512 35.653 ;
     RECT  0.192 34.837 0.456 35.939 ;
     RECT  15.36 35.845 15.384 36.133 ;
     RECT  0.24 35.939 0.456 36.563 ;
     RECT  0.24 36.563 0.36 36.611 ;
     RECT  2.208 35.653 13.512 36.661 ;
     RECT  14.784 36.133 15.384 36.661 ;
     RECT  0.24 36.611 0.312 36.997 ;
     RECT  2.208 36.661 15.384 37.043 ;
     RECT  2.208 37.043 14.808 37.091 ;
     RECT  2.208 37.091 14.232 37.859 ;
     RECT  0.144 36.997 0.312 37.861 ;
     RECT  0.144 37.861 0.504 38.195 ;
     RECT  2.304 37.859 14.232 38.819 ;
     RECT  0.192 38.195 0.504 38.963 ;
     RECT  0.192 38.963 0.456 39.301 ;
     RECT  2.304 38.819 14.04 39.395 ;
     RECT  0.144 39.301 0.456 39.491 ;
     RECT  15.36 39.301 15.384 39.877 ;
     RECT  0.192 39.491 0.456 40.595 ;
     RECT  2.304 39.395 13.752 40.595 ;
     RECT  15.312 39.877 15.384 41.075 ;
     RECT  0.288 40.595 0.456 41.171 ;
     RECT  15.312 41.075 15.336 41.171 ;
     RECT  17.088 41.125 17.112 41.315 ;
     RECT  2.4 40.595 13.656 42.133 ;
     RECT  0.336 41.171 0.36 42.325 ;
     RECT  0.144 42.325 0.36 42.517 ;
     RECT  0.144 42.517 0.408 42.947 ;
     RECT  2.4 42.133 14.136 42.949 ;
     RECT  0.192 42.947 0.408 43.571 ;
     RECT  0.192 43.571 0.312 43.909 ;
     RECT  0.144 43.909 0.312 44.483 ;
     RECT  2.4 42.949 14.808 45.731 ;
     RECT  0.192 44.483 0.312 45.733 ;
     RECT  0.144 45.733 0.312 46.211 ;
     RECT  0.24 46.211 0.312 46.213 ;
     RECT  2.4 45.731 12.12 46.549 ;
     RECT  13.2 45.731 14.808 46.787 ;
     RECT  0.24 46.213 0.552 46.883 ;
     RECT  0.24 46.883 0.36 47.173 ;
     RECT  2.304 46.549 12.12 47.173 ;
     RECT  13.2 46.787 13.656 47.173 ;
     RECT  2.304 47.173 13.656 47.363 ;
     RECT  9.552 47.363 13.656 47.411 ;
     RECT  14.784 46.787 14.808 47.749 ;
     RECT  12.528 47.411 13.656 47.845 ;
     RECT  14.736 47.749 14.808 47.845 ;
     RECT  12.528 47.845 14.808 47.939 ;
     RECT  2.304 47.363 8.52 48.373 ;
     RECT  9.552 47.411 11.256 48.373 ;
     RECT  12.528 47.939 14.76 48.373 ;
     RECT  2.304 48.373 14.76 48.515 ;
     RECT  0.144 47.173 0.36 49.139 ;
     RECT  11.904 48.515 14.76 49.285 ;
     RECT  2.304 48.515 10.488 49.619 ;
     RECT  9.408 49.619 10.488 49.909 ;
     RECT  11.904 49.285 15.384 49.909 ;
     RECT  17.088 50.437 17.112 50.627 ;
     RECT  0.144 49.139 0.216 50.629 ;
     RECT  2.304 49.619 8.376 50.677 ;
     RECT  0.144 50.629 0.312 50.771 ;
     RECT  9.408 49.909 15.384 51.347 ;
     RECT  2.304 50.677 8.424 51.685 ;
     RECT  9.408 51.347 14.472 51.685 ;
     RECT  0.144 50.771 0.264 52.547 ;
     RECT  0.144 52.547 0.168 53.701 ;
     RECT  2.304 51.685 14.472 54.131 ;
     RECT  0.144 53.701 0.216 54.469 ;
     RECT  11.952 54.131 14.472 54.565 ;
     RECT  0.144 54.469 0.264 54.613 ;
     RECT  11.952 54.565 14.568 54.661 ;
     RECT  0.144 54.613 0.312 54.899 ;
     RECT  2.304 54.131 10.872 55.237 ;
     RECT  11.952 54.661 14.664 55.237 ;
     RECT  2.304 55.237 14.664 56.579 ;
     RECT  0.144 54.899 0.264 57.059 ;
     RECT  0.144 57.059 0.168 57.635 ;
     RECT  2.4 56.579 14.664 57.683 ;
     RECT  2.4 57.683 3.048 57.731 ;
     RECT  4.128 57.683 14.664 58.163 ;
     RECT  2.4 57.731 2.856 58.211 ;
     RECT  4.128 58.163 14.232 58.259 ;
     RECT  6.384 58.259 14.232 58.307 ;
     RECT  6.384 58.307 13.848 58.691 ;
     RECT  10.272 58.691 13.848 58.739 ;
     RECT  6.384 58.691 9.24 58.787 ;
     RECT  6.384 58.787 8.376 58.835 ;
     RECT  2.4 58.211 2.808 59.027 ;
     RECT  4.128 58.259 5.112 59.315 ;
     RECT  6.384 58.835 8.328 59.315 ;
     RECT  11.184 58.739 13.512 59.315 ;
     RECT  4.176 59.315 5.112 59.363 ;
     RECT  6.384 59.315 8.28 59.363 ;
     RECT  4.176 59.363 4.2 59.411 ;
     RECT  7.8 59.363 8.28 59.411 ;
     RECT  6.384 59.363 6.408 59.891 ;
     RECT  12.144 59.315 13.512 59.891 ;
     RECT  12.144 59.891 12.168 59.939 ;
     RECT  2.4 59.027 2.712 62.649 ;
     RECT  7.8 59.411 8.112 62.649 ;
     RECT  13.2 59.891 13.512 62.649 ;
     RECT  2.4 62.649 2.52 62.663 ;
     RECT  7.8 62.649 7.92 62.663 ;
     RECT  13.2 62.649 13.32 62.663 ;
  END
END ot_qwen_tree_delay2_t
END LIBRARY
